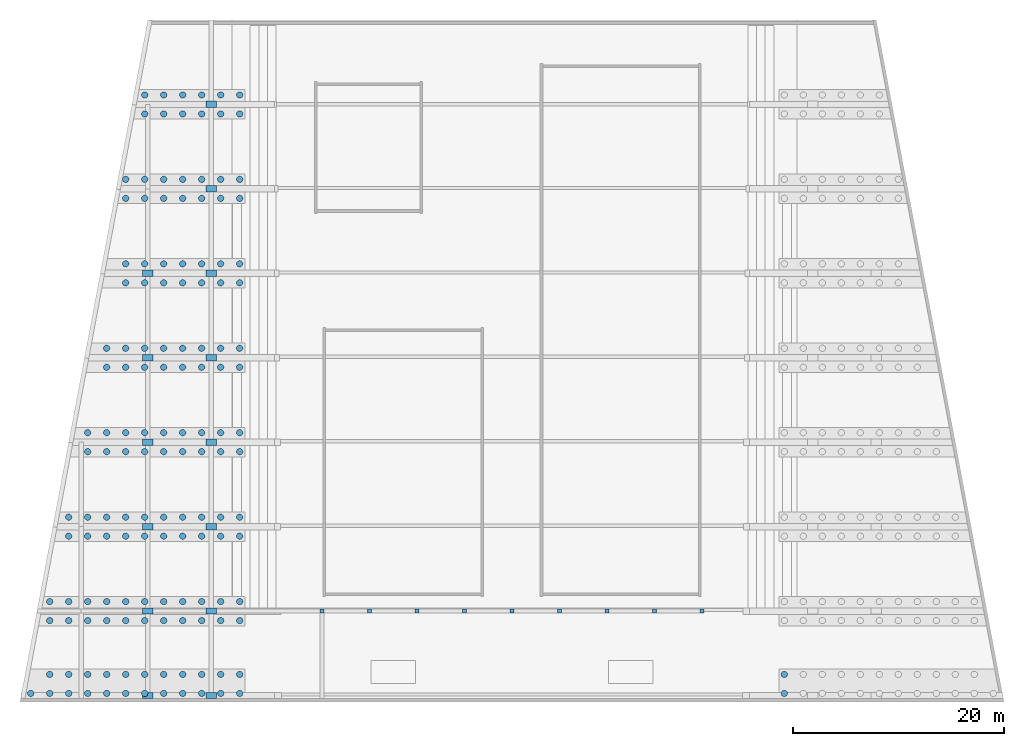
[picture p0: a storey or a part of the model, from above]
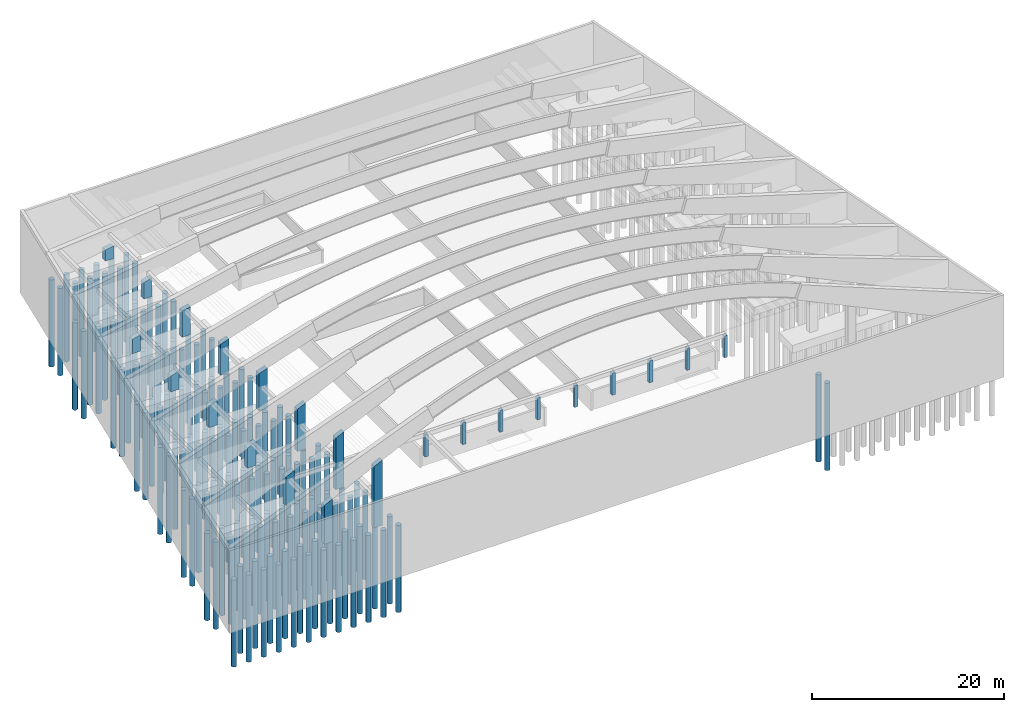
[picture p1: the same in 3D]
Properties of the parts of a building model (IFC2X3), part 1 of 5

# File
Description: ViewDefinition [CoordinationView_V2.0, QuantityTakeOffAddOnView]
File name: Project Number
Time: 2019-07-20T14:07:28
Written by: The EXPRESS Data Manager Version 5.02.0100.07 : 28 Aug 2013
Made in: 20170223_1515(x64) - Exporter 18.4.0.0 - Alternate UI 18.4.0.0
Comment: STEP Physical File produced by: The EXPRESS Data Manager Version 5.02.0100.07 : 28 Aug 2013 * Module: EDMstepFileFactory/EDMstandAlone * Creation date: Sat Jul 20 14:07:28 2019 * Host: ICIVEML714002 * Database: C:\Users\JL9E96~1.PON\AppData\Local\Temp\{ACF15B86-B727-4FDA-8734-9AC93CBAED3B}\ifc * Database version: 5507 * Database creation date: Sat Jul 20 14:07:22 2019 * Schema: IFC2X3 * Model: DataRepository.ifc * Model creation date: Sat Jul 20 14:07:23 2019 * Header model: DataRepository.ifc_HeaderModel * Header model creation date: Sat Jul 20 14:07:23 2019 * EDMuser: sdai-user * EDMgroup: sdai-group * License ID and type: 5605 : Permanent license. Expiry date: * EDMstepFileFactory options: 020000

# IfcProject, Project Number
LongName: Project Name; Phase: Project Status

# IfcSite, Default
RefLatitude: 42, 21, 31, 181945; RefLongitude: -71, -3, -24, -263305; RefElevation: 0 mm
Other - Category: Project Information; Client Name: Owner; Project Address: ## Street City, State Zip; Project Issue Date: Issue Date; Project Name: Project Name; Project Number: Project Number; Project Status: Project Status

# IfcBuilding
Pset_BuildingCommon - NumberOfStoreys: 2
Pset_ProductRequirements - Category: Project Information
Other - Category: Project Information; Client Name: Owner; Project Address: ## Street City, State Zip; Project Issue Date: Issue Date; Project Name: Project Name; Project Number: Project Number; Project Status: Project Status

# IfcBuildingStorey: Level:8mm Head, Default
LongName: Default; Elevation: 0 mm
Pset_AirSideSystemInformation - Name: Default
Pset_ProductRequirements - Name: Default; Category: Levels
Constraints - Elevation: 0 mm
Dimensions - Computation Height: 0 mm
Identity Data - Building Story: yes; Name: Default; Structural: no
Other - Category: Levels; Family: Level: 8mm Head; Family and Type: Level: 8mm Head; Type: Level: 8mm Head; Type Id: Level: 8mm Head
Constraints(Type) - Elevation Base: Project Base Point
Graphics(Type) - Color: 0; Line Pattern: Center; Line Weight: 1; Symbol: M_Level Head - Circle: M_Level Head - Circle; Symbol at End 1 Default: no; Symbol at End 2 Default: yes
Identity Data(Type) - Type Name: 8mm Head
Other(Type) - Category: Levels; Family Name: Level

# IfcBuildingElementProxy: 1000*2800, 1000*2800:1000*2800:212590
In: Default
Type - Classification: A1010130 Pile Caps (Uniformat); Material: CONCRETE/28MPa
Type - Identity Data - Assembly Code: A1010130; Assembly Description: Pile Caps; Type Name: 1000*2800
Type - Materials and Finishes - Material: CONCRETE/28MPa
Type - Other - Category: Structural Framing; Family Name: 1000*2800
Type - Structural - Section Shape: 0
Type - Pset_BuildingElementProxyCommon - Reference: 1000*2800
Type - Pset_ProductRequirements - Category: Structural Framing
Type - Pset_QuantityTakeOff - Reference: 1000*2800
Pset_BuildingElementProxyCommon - sets with these values: 2
Constraints - Moves With Nearby Elements: no; Level: Level: Default; Host: Level : Default; Offset: -3800 mm
Dimensions - Area: 65.1248 m2; Volume: 45.9055 m3
Other - Family: 1000*2800: 1000*2800; Family and Type: 1000*2800: 1000*2800; Type: 1000*2800: 1000*2800; Type Id: 1000*2800: 1000*2800
Phasing - Phase Created: New Construction
Structural - Rebar Cover - Other Faces: Rebar Cover Settings: Rebar Cover 1; Rebar Cover - Bottom Face: Rebar Cover Settings: Rebar Cover 1; Rebar Cover - Top Face: Rebar Cover Settings: Rebar Cover 1

# IfcBuildingElementProxy: 1000*2800 1594, 1000*2800 1594:1000*2800 1594:212589
In: Default
Type - Classification: A1010130 Pile Caps (Uniformat); Material: CONCRETE/28MPa
Type - Identity Data - Assembly Code: A1010130; Assembly Description: Pile Caps; Type Name: 1000*2800 1594
Type - Materials and Finishes - Material: CONCRETE/28MPa
Type - Other - Category: Structural Framing; Family Name: 1000*2800 1594
Type - Structural - Section Shape: 0
Type - Pset_BuildingElementProxyCommon - Reference: 1000*2800 1594
Type - Pset_ProductRequirements - Category: Structural Framing
Type - Pset_QuantityTakeOff - Reference: 1000*2800 1594
Pset_BuildingElementProxyCommon - sets with these values: 2
Constraints - Moves With Nearby Elements: no; Level: Level: Default; Host: Level : Default; Offset: -3800 mm
Dimensions - Area: 42.325 m2; Volume: 29.1057 m3
Other - Family: 1000*2800 1594: 1000*2800 1594; Family and Type: 1000*2800 1594: 1000*2800 1594; Type: 1000*2800 1594: 1000*2800 1594; Type Id: 1000*2800 1594: 1000*2800 1594
Phasing - Phase Created: New Construction
Structural - Rebar Cover - Other Faces: Rebar Cover Settings: Rebar Cover 1; Rebar Cover - Bottom Face: Rebar Cover Settings: Rebar Cover 1; Rebar Cover - Top Face: Rebar Cover Settings: Rebar Cover 1

# IfcBuildingElementProxy: 1000*2800 1628, 1000*2800 1628:1000*2800 1628:212588
In: Default
Type - Classification: A1010130 Pile Caps (Uniformat); Material: CONCRETE/28MPa
Type - Identity Data - Assembly Code: A1010130; Assembly Description: Pile Caps; Type Name: 1000*2800 1628
Type - Materials and Finishes - Material: CONCRETE/28MPa
Type - Other - Category: Structural Framing; Family Name: 1000*2800 1628
Type - Structural - Section Shape: 0
Type - Pset_BuildingElementProxyCommon - Reference: 1000*2800 1628
Type - Pset_ProductRequirements - Category: Structural Framing
Type - Pset_QuantityTakeOff - Reference: 1000*2800 1628
Pset_BuildingElementProxyCommon - sets with these values: 2
Constraints - Moves With Nearby Elements: no; Level: Level: Default; Host: Level : Default; Offset: -3800 mm
Dimensions - Area: 48.0363 m2; Volume: 33.3136 m3
Other - Family: 1000*2800 1628: 1000*2800 1628; Family and Type: 1000*2800 1628: 1000*2800 1628; Type: 1000*2800 1628: 1000*2800 1628; Type Id: 1000*2800 1628: 1000*2800 1628
Phasing - Phase Created: New Construction
Structural - Rebar Cover - Other Faces: Rebar Cover Settings: Rebar Cover 1; Rebar Cover - Bottom Face: Rebar Cover Settings: Rebar Cover 1; Rebar Cover - Top Face: Rebar Cover Settings: Rebar Cover 1

# IfcBuildingElementProxy: 1000*2800 1660, 1000*2800 1660:1000*2800 1660:212587
In: Default
Type - Classification: A1010130 Pile Caps (Uniformat); Material: CONCRETE/28MPa
Type - Identity Data - Assembly Code: A1010130; Assembly Description: Pile Caps; Type Name: 1000*2800 1660
Type - Materials and Finishes - Material: CONCRETE/28MPa
Type - Other - Category: Structural Framing; Family Name: 1000*2800 1660
Type - Structural - Section Shape: 0
Type - Pset_BuildingElementProxyCommon - Reference: 1000*2800 1660
Type - Pset_ProductRequirements - Category: Structural Framing
Type - Pset_QuantityTakeOff - Reference: 1000*2800 1660
Pset_BuildingElementProxyCommon - sets with these values: 2
Constraints - Moves With Nearby Elements: no; Level: Level: Default; Host: Level : Default; Offset: -3800 mm
Dimensions - Area: 53.7249 m2; Volume: 37.5056 m3
Other - Family: 1000*2800 1660: 1000*2800 1660; Family and Type: 1000*2800 1660: 1000*2800 1660; Type: 1000*2800 1660: 1000*2800 1660; Type Id: 1000*2800 1660: 1000*2800 1660
Phasing - Phase Created: New Construction
Structural - Rebar Cover - Other Faces: Rebar Cover Settings: Rebar Cover 1; Rebar Cover - Bottom Face: Rebar Cover Settings: Rebar Cover 1; Rebar Cover - Top Face: Rebar Cover Settings: Rebar Cover 1

# IfcBuildingElementProxy: 1000*2800 1692, 1000*2800 1692:1000*2800 1692:212586
In: Default
Type - Classification: A1010130 Pile Caps (Uniformat); Material: CONCRETE/28MPa
Type - Identity Data - Assembly Code: A1010130; Assembly Description: Pile Caps; Type Name: 1000*2800 1692
Type - Materials and Finishes - Material: CONCRETE/28MPa
Type - Other - Category: Structural Framing; Family Name: 1000*2800 1692
Type - Structural - Section Shape: 0
Type - Pset_BuildingElementProxyCommon - Reference: 1000*2800 1692
Type - Pset_ProductRequirements - Category: Structural Framing
Type - Pset_QuantityTakeOff - Reference: 1000*2800 1692
Pset_BuildingElementProxyCommon - sets with these values: 2
Constraints - Moves With Nearby Elements: no; Level: Level: Default; Host: Level : Default; Offset: -3800 mm
Dimensions - Area: 59.4248 m2; Volume: 41.7056 m3
Other - Family: 1000*2800 1692: 1000*2800 1692; Family and Type: 1000*2800 1692: 1000*2800 1692; Type: 1000*2800 1692: 1000*2800 1692; Type Id: 1000*2800 1692: 1000*2800 1692
Phasing - Phase Created: New Construction
Structural - Rebar Cover - Other Faces: Rebar Cover Settings: Rebar Cover 1; Rebar Cover - Bottom Face: Rebar Cover Settings: Rebar Cover 1; Rebar Cover - Top Face: Rebar Cover Settings: Rebar Cover 1

# IfcBuildingElementProxy: 1000*2800 1722, 1000*2800 1722:1000*2800 1722:212585
In: Default
Type - Classification: A1010130 Pile Caps (Uniformat); Material: CONCRETE/28MPa
Type - Identity Data - Assembly Code: A1010130; Assembly Description: Pile Caps; Type Name: 1000*2800 1722
Type - Materials and Finishes - Material: CONCRETE/28MPa
Type - Other - Category: Structural Framing; Family Name: 1000*2800 1722
Type - Structural - Section Shape: 0
Type - Pset_BuildingElementProxyCommon - Reference: 1000*2800 1722
Type - Pset_ProductRequirements - Category: Structural Framing
Type - Pset_QuantityTakeOff - Reference: 1000*2800 1722
Pset_BuildingElementProxyCommon - sets with these values: 2
Constraints - Moves With Nearby Elements: no; Level: Level: Default; Host: Level : Default; Offset: -3800 mm
Dimensions - Area: 70.8247 m2; Volume: 50.1055 m3
Other - Family: 1000*2800 1722: 1000*2800 1722; Family and Type: 1000*2800 1722: 1000*2800 1722; Type: 1000*2800 1722: 1000*2800 1722; Type Id: 1000*2800 1722: 1000*2800 1722
Phasing - Phase Created: New Construction
Structural - Rebar Cover - Other Faces: Rebar Cover Settings: Rebar Cover 1; Rebar Cover - Bottom Face: Rebar Cover Settings: Rebar Cover 1; Rebar Cover - Top Face: Rebar Cover Settings: Rebar Cover 1

# IfcBuildingElementProxy: 1000*2800 1754, 1000*2800 1754:1000*2800 1754:212584
In: Default
Type - Classification: A1010130 Pile Caps (Uniformat); Material: CONCRETE/28MPa
Type - Identity Data - Assembly Code: A1010130; Assembly Description: Pile Caps; Type Name: 1000*2800 1754
Type - Materials and Finishes - Material: CONCRETE/28MPa
Type - Other - Category: Structural Framing; Family Name: 1000*2800 1754
Type - Structural - Section Shape: 0
Type - Pset_BuildingElementProxyCommon - Reference: 1000*2800 1754
Type - Pset_ProductRequirements - Category: Structural Framing
Type - Pset_QuantityTakeOff - Reference: 1000*2800 1754
Pset_BuildingElementProxyCommon - sets with these values: 2
Constraints - Moves With Nearby Elements: no; Level: Level: Default; Host: Level : Default; Offset: -3800 mm
Dimensions - Area: 76.5246 m2; Volume: 54.3054 m3
Other - Family: 1000*2800 1754: 1000*2800 1754; Family and Type: 1000*2800 1754: 1000*2800 1754; Type: 1000*2800 1754: 1000*2800 1754; Type Id: 1000*2800 1754: 1000*2800 1754
Phasing - Phase Created: New Construction
Structural - Rebar Cover - Other Faces: Rebar Cover Settings: Rebar Cover 1; Rebar Cover - Bottom Face: Rebar Cover Settings: Rebar Cover 1; Rebar Cover - Top Face: Rebar Cover Settings: Rebar Cover 1

# IfcBuildingElementProxy: 1000*2800 1835, 1000*2800 1835:1000*2800 1835:212583
In: Default
Type - Classification: A1010130 Pile Caps (Uniformat); Material: CONCRETE/28MPa
Type - Identity Data - Assembly Code: A1010130; Assembly Description: Pile Caps; Type Name: 1000*2800 1835
Type - Materials and Finishes - Material: CONCRETE/28MPa
Type - Other - Category: Structural Framing; Family Name: 1000*2800 1835
Type - Structural - Section Shape: 0
Type - Pset_BuildingElementProxyCommon - Reference: 1000*2800 1835
Type - Pset_ProductRequirements - Category: Structural Framing
Type - Pset_QuantityTakeOff - Reference: 1000*2800 1835
Pset_BuildingElementProxyCommon - sets with these values: 2
Constraints - Moves With Nearby Elements: no; Level: Level: Default; Host: Level : Default; Offset: -3800 mm
Dimensions - Area: 81.4408 m2; Volume: 57.9279 m3
Other - Family: 1000*2800 1835: 1000*2800 1835; Family and Type: 1000*2800 1835: 1000*2800 1835; Type: 1000*2800 1835: 1000*2800 1835; Type Id: 1000*2800 1835: 1000*2800 1835
Phasing - Phase Created: New Construction
Structural - Rebar Cover - Other Faces: Rebar Cover Settings: Rebar Cover 1; Rebar Cover - Bottom Face: Rebar Cover Settings: Rebar Cover 1; Rebar Cover - Top Face: Rebar Cover Settings: Rebar Cover 1

# IfcBuildingElementProxy: 1000*2800 3217, 1000*2800 3217:1000*2800 3217:212544
In: Default
Type - Classification: A1010130 Pile Caps (Uniformat); Material: CONCRETE/28MPa
Type - Identity Data - Assembly Code: A1010130; Assembly Description: Pile Caps; Type Name: 1000*2800 3217
Type - Materials and Finishes - Material: CONCRETE/28MPa
Type - Other - Category: Structural Framing; Family Name: 1000*2800 3217
Type - Structural - Section Shape: 0
Type - Pset_BuildingElementProxyCommon - Reference: 1000*2800 3217
Type - Pset_ProductRequirements - Category: Structural Framing
Type - Pset_QuantityTakeOff - Reference: 1000*2800 3217
Pset_BuildingElementProxyCommon - sets with these values: 2
Constraints - Moves With Nearby Elements: no; Level: Level: Default; Host: Level : Default; Offset: -3800 mm
Dimensions - Area: 65.1248 m2; Volume: 45.9055 m3
Other - Family: 1000*2800 3217: 1000*2800 3217; Family and Type: 1000*2800 3217: 1000*2800 3217; Type: 1000*2800 3217: 1000*2800 3217; Type Id: 1000*2800 3217: 1000*2800 3217
Phasing - Phase Created: New Construction
Structural - Rebar Cover - Other Faces: Rebar Cover Settings: Rebar Cover 1; Rebar Cover - Bottom Face: Rebar Cover Settings: Rebar Cover 1; Rebar Cover - Top Face: Rebar Cover Settings: Rebar Cover 1

# IfcBuildingElementProxy: 1000*2800 4924, 1000*2800 4924:1000*2800 4924:212262
In: Default
Type - Classification: A1010130 Pile Caps (Uniformat); Material: CONCRETE/28MPa
Type - Identity Data - Assembly Code: A1010130; Assembly Description: Pile Caps; Type Name: 1000*2800 4924
Type - Materials and Finishes - Material: CONCRETE/28MPa
Type - Other - Category: Structural Framing; Family Name: 1000*2800 4924
Type - Structural - Section Shape: 0
Type - Pset_BuildingElementProxyCommon - Reference: 1000*2800 4924
Type - Pset_ProductRequirements - Category: Structural Framing
Type - Pset_QuantityTakeOff - Reference: 1000*2800 4924
Pset_BuildingElementProxyCommon - sets with these values: 2
Constraints - Moves With Nearby Elements: no; Level: Level: Default; Host: Level : Default; Offset: -3800 mm
Dimensions - Area: 42.325 m2; Volume: 29.1057 m3
Other - Family: 1000*2800 4924: 1000*2800 4924; Family and Type: 1000*2800 4924: 1000*2800 4924; Type: 1000*2800 4924: 1000*2800 4924; Type Id: 1000*2800 4924: 1000*2800 4924
Phasing - Phase Created: New Construction
Structural - Rebar Cover - Other Faces: Rebar Cover Settings: Rebar Cover 1; Rebar Cover - Bottom Face: Rebar Cover Settings: Rebar Cover 1; Rebar Cover - Top Face: Rebar Cover Settings: Rebar Cover 1

# IfcBuildingElementProxy: 1000*2800 4946, 1000*2800 4946:1000*2800 4946:212261
In: Default
Type - Classification: A1010130 Pile Caps (Uniformat); Material: CONCRETE/28MPa
Type - Identity Data - Assembly Code: A1010130; Assembly Description: Pile Caps; Type Name: 1000*2800 4946
Type - Materials and Finishes - Material: CONCRETE/28MPa
Type - Other - Category: Structural Framing; Family Name: 1000*2800 4946
Type - Structural - Section Shape: 0
Type - Pset_BuildingElementProxyCommon - Reference: 1000*2800 4946
Type - Pset_ProductRequirements - Category: Structural Framing
Type - Pset_QuantityTakeOff - Reference: 1000*2800 4946
Pset_BuildingElementProxyCommon - sets with these values: 2
Constraints - Moves With Nearby Elements: no; Level: Level: Default; Host: Level : Default; Offset: -3800 mm
Dimensions - Area: 48.0363 m2; Volume: 33.3136 m3
Other - Family: 1000*2800 4946: 1000*2800 4946; Family and Type: 1000*2800 4946: 1000*2800 4946; Type: 1000*2800 4946: 1000*2800 4946; Type Id: 1000*2800 4946: 1000*2800 4946
Phasing - Phase Created: New Construction
Structural - Rebar Cover - Other Faces: Rebar Cover Settings: Rebar Cover 1; Rebar Cover - Bottom Face: Rebar Cover Settings: Rebar Cover 1; Rebar Cover - Top Face: Rebar Cover Settings: Rebar Cover 1

# IfcBuildingElementProxy: 1000*2800 4966, 1000*2800 4966:1000*2800 4966:212260
In: Default
Type - Classification: A1010130 Pile Caps (Uniformat); Material: CONCRETE/28MPa
Type - Identity Data - Assembly Code: A1010130; Assembly Description: Pile Caps; Type Name: 1000*2800 4966
Type - Materials and Finishes - Material: CONCRETE/28MPa
Type - Other - Category: Structural Framing; Family Name: 1000*2800 4966
Type - Structural - Section Shape: 0
Type - Pset_BuildingElementProxyCommon - Reference: 1000*2800 4966
Type - Pset_ProductRequirements - Category: Structural Framing
Type - Pset_QuantityTakeOff - Reference: 1000*2800 4966
Pset_BuildingElementProxyCommon - sets with these values: 2
Constraints - Moves With Nearby Elements: no; Level: Level: Default; Host: Level : Default; Offset: -3800 mm
Dimensions - Area: 53.7249 m2; Volume: 37.5056 m3
Other - Family: 1000*2800 4966: 1000*2800 4966; Family and Type: 1000*2800 4966: 1000*2800 4966; Type: 1000*2800 4966: 1000*2800 4966; Type Id: 1000*2800 4966: 1000*2800 4966
Phasing - Phase Created: New Construction
Structural - Rebar Cover - Other Faces: Rebar Cover Settings: Rebar Cover 1; Rebar Cover - Bottom Face: Rebar Cover Settings: Rebar Cover 1; Rebar Cover - Top Face: Rebar Cover Settings: Rebar Cover 1

# IfcBuildingElementProxy: 1000*2800 4986, 1000*2800 4986:1000*2800 4986:212259
In: Default
Type - Classification: A1010130 Pile Caps (Uniformat); Material: CONCRETE/28MPa
Type - Identity Data - Assembly Code: A1010130; Assembly Description: Pile Caps; Type Name: 1000*2800 4986
Type - Materials and Finishes - Material: CONCRETE/28MPa
Type - Other - Category: Structural Framing; Family Name: 1000*2800 4986
Type - Structural - Section Shape: 0
Type - Pset_BuildingElementProxyCommon - Reference: 1000*2800 4986
Type - Pset_ProductRequirements - Category: Structural Framing
Type - Pset_QuantityTakeOff - Reference: 1000*2800 4986
Pset_BuildingElementProxyCommon - sets with these values: 2
Constraints - Moves With Nearby Elements: no; Level: Level: Default; Host: Level : Default; Offset: -3800 mm
Dimensions - Area: 59.4248 m2; Volume: 41.7056 m3
Other - Family: 1000*2800 4986: 1000*2800 4986; Family and Type: 1000*2800 4986: 1000*2800 4986; Type: 1000*2800 4986: 1000*2800 4986; Type Id: 1000*2800 4986: 1000*2800 4986
Phasing - Phase Created: New Construction
Structural - Rebar Cover - Other Faces: Rebar Cover Settings: Rebar Cover 1; Rebar Cover - Bottom Face: Rebar Cover Settings: Rebar Cover 1; Rebar Cover - Top Face: Rebar Cover Settings: Rebar Cover 1

# IfcBuildingElementProxy: 1000*2800 5003, 1000*2800 5003:1000*2800 5003:212258
In: Default
Type - Classification: A1010130 Pile Caps (Uniformat); Material: CONCRETE/28MPa
Type - Identity Data - Assembly Code: A1010130; Assembly Description: Pile Caps; Type Name: 1000*2800 5003
Type - Materials and Finishes - Material: CONCRETE/28MPa
Type - Other - Category: Structural Framing; Family Name: 1000*2800 5003
Type - Structural - Section Shape: 0
Type - Pset_BuildingElementProxyCommon - Reference: 1000*2800 5003
Type - Pset_ProductRequirements - Category: Structural Framing
Type - Pset_QuantityTakeOff - Reference: 1000*2800 5003
Pset_BuildingElementProxyCommon - sets with these values: 2
Constraints - Moves With Nearby Elements: no; Level: Level: Default; Host: Level : Default; Offset: -3800 mm
Dimensions - Area: 70.8247 m2; Volume: 50.1055 m3
Other - Family: 1000*2800 5003: 1000*2800 5003; Family and Type: 1000*2800 5003: 1000*2800 5003; Type: 1000*2800 5003: 1000*2800 5003; Type Id: 1000*2800 5003: 1000*2800 5003
Phasing - Phase Created: New Construction
Structural - Rebar Cover - Other Faces: Rebar Cover Settings: Rebar Cover 1; Rebar Cover - Bottom Face: Rebar Cover Settings: Rebar Cover 1; Rebar Cover - Top Face: Rebar Cover Settings: Rebar Cover 1

# IfcBuildingElementProxy: 1000*2800 5022, 1000*2800 5022:1000*2800 5022:212257
In: Default
Type - Classification: A1010130 Pile Caps (Uniformat); Material: CONCRETE/28MPa
Type - Identity Data - Assembly Code: A1010130; Assembly Description: Pile Caps; Type Name: 1000*2800 5022
Type - Materials and Finishes - Material: CONCRETE/28MPa
Type - Other - Category: Structural Framing; Family Name: 1000*2800 5022
Type - Structural - Section Shape: 0
Type - Pset_BuildingElementProxyCommon - Reference: 1000*2800 5022
Type - Pset_ProductRequirements - Category: Structural Framing
Type - Pset_QuantityTakeOff - Reference: 1000*2800 5022
Pset_BuildingElementProxyCommon - sets with these values: 2
Constraints - Moves With Nearby Elements: no; Host: Level : Default; Level: Level: Default; Offset: -3800 mm
Dimensions - Area: 76.5246 m2; Volume: 54.3054 m3
Other - Family: 1000*2800 5022: 1000*2800 5022; Family and Type: 1000*2800 5022: 1000*2800 5022; Type: 1000*2800 5022: 1000*2800 5022; Type Id: 1000*2800 5022: 1000*2800 5022
Phasing - Phase Created: New Construction
Structural - Rebar Cover - Other Faces: Rebar Cover Settings: Rebar Cover 1; Rebar Cover - Bottom Face: Rebar Cover Settings: Rebar Cover 1; Rebar Cover - Top Face: Rebar Cover Settings: Rebar Cover 1

# IfcBuildingElementProxy: 1000*2800 5068, 1000*2800 5068:1000*2800 5068:212256
In: Default
Type - Classification: A1010130 Pile Caps (Uniformat); Material: CONCRETE/28MPa
Type - Identity Data - Assembly Code: A1010130; Assembly Description: Pile Caps; Type Name: 1000*2800 5068
Type - Materials and Finishes - Material: CONCRETE/28MPa
Type - Other - Category: Structural Framing; Family Name: 1000*2800 5068
Type - Structural - Section Shape: 0
Type - Pset_BuildingElementProxyCommon - Reference: 1000*2800 5068
Type - Pset_ProductRequirements - Category: Structural Framing
Type - Pset_QuantityTakeOff - Reference: 1000*2800 5068
Pset_BuildingElementProxyCommon - sets with these values: 2
Constraints - Moves With Nearby Elements: no; Host: Level : Default; Level: Level: Default; Offset: -3800 mm
Dimensions - Area: 81.4408 m2; Volume: 57.9279 m3
Other - Family: 1000*2800 5068: 1000*2800 5068; Family and Type: 1000*2800 5068: 1000*2800 5068; Type: 1000*2800 5068: 1000*2800 5068; Type Id: 1000*2800 5068: 1000*2800 5068
Phasing - Phase Created: New Construction
Structural - Rebar Cover - Other Faces: Rebar Cover Settings: Rebar Cover 1; Rebar Cover - Bottom Face: Rebar Cover Settings: Rebar Cover 1; Rebar Cover - Top Face: Rebar Cover Settings: Rebar Cover 1

# IfcBuildingElementProxy: 500*400 (4)
In: Default
Type - Classification: B1010310 Beams - CIP (Uniformat); Material: CONCRETE/28MPa 4258
Type - Identity Data - Assembly Code: B1010310; Assembly Description: Beams - CIP; Type Name: 500*400
Type - Materials and Finishes - Material: CONCRETE/28MPa 4258
Type - Other - Category: Structural Framing; Family Name: 500*400
Type - Structural - Section Shape: 0
Type - Pset_BuildingElementProxyCommon - Reference: 500*400
Type - Pset_ProductRequirements - Category: Structural Framing
Type - Pset_QuantityTakeOff - Reference: 500*400
Pset_BuildingElementProxyCommon - sets with these values: 2
Constraints - Moves With Nearby Elements: no; Level: Level: Default; Host: Level : Default; Offset: -150 mm
Dimensions - Area: 7.67 m2; Volume: 1.66 m3
Other - Family: 500*400: 500*400; Family and Type: 500*400: 500*400; Type: 500*400: 500*400; Type Id: 500*400: 500*400
Phasing - Phase Created: New Construction
Structural - Rebar Cover - Other Faces: Rebar Cover Settings: Rebar Cover 1; Rebar Cover - Bottom Face: Rebar Cover Settings: Rebar Cover 1; Rebar Cover - Top Face: Rebar Cover Settings: Rebar Cover 1
Name (500*400:500*400:...)
212263
212271
212286
212301

# IfcBuildingElementProxy: 500*400 4300 (8)
In: Default
Type - Classification: B1010310 Beams - CIP (Uniformat); Material: CONCRETE/28MPa 4258
Type - Identity Data - Assembly Code: B1010310; Assembly Description: Beams - CIP; Type Name: 500*400 4300
Type - Materials and Finishes - Material: CONCRETE/28MPa 4258
Type - Other - Category: Structural Framing; Family Name: 500*400 4300
Type - Structural - Section Shape: 0
Type - Pset_BuildingElementProxyCommon - Reference: 500*400 4300
Type - Pset_ProductRequirements - Category: Structural Framing
Type - Pset_QuantityTakeOff - Reference: 500*400 4300
Pset_BuildingElementProxyCommon - sets with these values: 2
Constraints - Moves With Nearby Elements: no; Level: Level: Default; Host: Level : Default; Offset: -150 mm
Dimensions - Area: 4.25 m2; Volume: 0.9 m3
Other - Family: 500*400 4300: 500*400 4300; Family and Type: 500*400 4300: 500*400 4300; Type: 500*400 4300: 500*400 4300; Type Id: 500*400 4300: 500*400 4300
Phasing - Phase Created: New Construction
Structural - Rebar Cover - Other Faces: Rebar Cover Settings: Rebar Cover 1; Rebar Cover - Bottom Face: Rebar Cover Settings: Rebar Cover 1; Rebar Cover - Top Face: Rebar Cover Settings: Rebar Cover 1
Name (500*400 4300:500*400 4300:...)
212293
212294
212295
212296
212297
212298
212299
212300

# IfcBuildingElementProxy: 500*400 4394, 500*400 4394:500*400 4394:212292
In: Default
Type - Classification: B1010310 Beams - CIP (Uniformat); Material: CONCRETE/28MPa 4258
Type - Identity Data - Assembly Code: B1010310; Assembly Description: Beams - CIP; Type Name: 500*400 4394
Type - Materials and Finishes - Material: CONCRETE/28MPa 4258
Type - Other - Category: Structural Framing; Family Name: 500*400 4394
Type - Structural - Section Shape: 0
Type - Pset_BuildingElementProxyCommon - Reference: 500*400 4394
Type - Pset_ProductRequirements - Category: Structural Framing
Type - Pset_QuantityTakeOff - Reference: 500*400 4394
Pset_BuildingElementProxyCommon - sets with these values: 2
Constraints - Moves With Nearby Elements: no; Level: Level: Default; Host: Level : Default; Offset: -150 mm
Dimensions - Area: 9.65 m2; Volume: 2.1 m3
Other - Family: 500*400 4394: 500*400 4394; Family and Type: 500*400 4394: 500*400 4394; Type: 500*400 4394: 500*400 4394; Type Id: 500*400 4394: 500*400 4394
Phasing - Phase Created: New Construction
Structural - Rebar Cover - Other Faces: Rebar Cover Settings: Rebar Cover 1; Rebar Cover - Bottom Face: Rebar Cover Settings: Rebar Cover 1; Rebar Cover - Top Face: Rebar Cover Settings: Rebar Cover 1

# IfcBuildingElementProxy: 500*400 4419, 500*400 4419:500*400 4419:212291
In: Default
Type - Classification: B1010310 Beams - CIP (Uniformat); Material: CONCRETE/28MPa 4258
Type - Identity Data - Assembly Code: B1010310; Assembly Description: Beams - CIP; Type Name: 500*400 4419
Type - Materials and Finishes - Material: CONCRETE/28MPa 4258
Type - Other - Category: Structural Framing; Family Name: 500*400 4419
Type - Structural - Section Shape: 0
Type - Pset_BuildingElementProxyCommon - Reference: 500*400 4419
Type - Pset_ProductRequirements - Category: Structural Framing
Type - Pset_QuantityTakeOff - Reference: 500*400 4419
Pset_BuildingElementProxyCommon - sets with these values: 2
Constraints - Moves With Nearby Elements: no; Level: Level: Default; Host: Level : Default; Offset: -150 mm
Dimensions - Area: 5.6 m2; Volume: 1.2 m3
Other - Family: 500*400 4419: 500*400 4419; Family and Type: 500*400 4419: 500*400 4419; Type: 500*400 4419: 500*400 4419; Type Id: 500*400 4419: 500*400 4419
Phasing - Phase Created: New Construction
Structural - Rebar Cover - Other Faces: Rebar Cover Settings: Rebar Cover 1; Rebar Cover - Bottom Face: Rebar Cover Settings: Rebar Cover 1; Rebar Cover - Top Face: Rebar Cover Settings: Rebar Cover 1

# IfcBuildingElementProxy: 500*400 4444, 500*400 4444:500*400 4444:212290
In: Default
Type - Classification: B1010310 Beams - CIP (Uniformat); Material: CONCRETE/28MPa 4258
Type - Identity Data - Assembly Code: B1010310; Assembly Description: Beams - CIP; Type Name: 500*400 4444
Type - Materials and Finishes - Material: CONCRETE/28MPa 4258
Type - Other - Category: Structural Framing; Family Name: 500*400 4444
Type - Structural - Section Shape: 0
Type - Pset_BuildingElementProxyCommon - Reference: 500*400 4444
Type - Pset_ProductRequirements - Category: Structural Framing
Type - Pset_QuantityTakeOff - Reference: 500*400 4444
Pset_BuildingElementProxyCommon - sets with these values: 2
Constraints - Moves With Nearby Elements: no; Level: Level: Default; Host: Level : Default; Offset: -150 mm
Dimensions - Area: 5.879 m2; Volume: 1.262 m3
Other - Family: 500*400 4444: 500*400 4444; Family and Type: 500*400 4444: 500*400 4444; Type: 500*400 4444: 500*400 4444; Type Id: 500*400 4444: 500*400 4444
Phasing - Phase Created: New Construction
Structural - Rebar Cover - Other Faces: Rebar Cover Settings: Rebar Cover 1; Rebar Cover - Bottom Face: Rebar Cover Settings: Rebar Cover 1; Rebar Cover - Top Face: Rebar Cover Settings: Rebar Cover 1

# IfcBuildingElementProxy: 500*400 4468, 500*400 4468:500*400 4468:212289
In: Default
Type - Classification: B1010310 Beams - CIP (Uniformat); Material: CONCRETE/28MPa 4258
Type - Identity Data - Assembly Code: B1010310; Assembly Description: Beams - CIP; Type Name: 500*400 4468
Type - Materials and Finishes - Material: CONCRETE/28MPa 4258
Type - Other - Category: Structural Framing; Family Name: 500*400 4468
Type - Structural - Section Shape: 0
Type - Pset_BuildingElementProxyCommon - Reference: 500*400 4468
Type - Pset_ProductRequirements - Category: Structural Framing
Type - Pset_QuantityTakeOff - Reference: 500*400 4468
Pset_BuildingElementProxyCommon - sets with these values: 2
Constraints - Moves With Nearby Elements: no; Level: Level: Default; Host: Level : Default; Offset: -150 mm
Dimensions - Area: 3.93324 m2; Volume: 0.82961 m3
Other - Family: 500*400 4468: 500*400 4468; Family and Type: 500*400 4468: 500*400 4468; Type: 500*400 4468: 500*400 4468; Type Id: 500*400 4468: 500*400 4468
Phasing - Phase Created: New Construction
Structural - Rebar Cover - Other Faces: Rebar Cover Settings: Rebar Cover 1; Rebar Cover - Bottom Face: Rebar Cover Settings: Rebar Cover 1; Rebar Cover - Top Face: Rebar Cover Settings: Rebar Cover 1

# IfcBuildingElementProxy: 500*400 4495 (14)
In: Default
Type - Classification: B1010310 Beams - CIP (Uniformat); Material: CONCRETE/28MPa 4258
Type - Identity Data - Assembly Code: B1010310; Assembly Description: Beams - CIP; Type Name: 500*400 4495
Type - Materials and Finishes - Material: CONCRETE/28MPa 4258
Type - Other - Category: Structural Framing; Family Name: 500*400 4495
Type - Structural - Section Shape: 0
Type - Pset_BuildingElementProxyCommon - Reference: 500*400 4495
Type - Pset_ProductRequirements - Category: Structural Framing
Type - Pset_QuantityTakeOff - Reference: 500*400 4495
Pset_BuildingElementProxyCommon - sets with these values: 2
Constraints - Moves With Nearby Elements: no; Level: Level: Default; Host: Level : Default; Offset: -150 mm
Dimensions - Area: 7.4 m2; Volume: 1.6 m3
Other - Family: 500*400 4495: 500*400 4495; Family and Type: 500*400 4495: 500*400 4495; Type: 500*400 4495: 500*400 4495; Type Id: 500*400 4495: 500*400 4495
Phasing - Phase Created: New Construction
Structural - Rebar Cover - Other Faces: Rebar Cover Settings: Rebar Cover 1; Rebar Cover - Bottom Face: Rebar Cover Settings: Rebar Cover 1; Rebar Cover - Top Face: Rebar Cover Settings: Rebar Cover 1
Name (500*400 4495:500*400 4495:...)
212264
212265
212266
212267
212268
212269
212272
212273
212274
212275
212276
212277
212287
212288

# IfcBuildingElementProxy: 500*400 4543, 500*400 4543:500*400 4543:212285
In: Default
Type - Classification: B1010310 Beams - CIP (Uniformat); Material: CONCRETE/28MPa 4258
Type - Identity Data - Assembly Code: B1010310; Assembly Description: Beams - CIP; Type Name: 500*400 4543
Type - Materials and Finishes - Material: CONCRETE/28MPa 4258
Type - Other - Category: Structural Framing; Family Name: 500*400 4543
Type - Structural - Section Shape: 0
Type - Pset_BuildingElementProxyCommon - Reference: 500*400 4543
Type - Pset_ProductRequirements - Category: Structural Framing
Type - Pset_QuantityTakeOff - Reference: 500*400 4543
Pset_BuildingElementProxyCommon - sets with these values: 2
Constraints - Moves With Nearby Elements: no; Level: Level: Default; Host: Level : Default; Offset: -150 mm
Dimensions - Area: 7.52527 m2; Volume: 1.62784 m3
Other - Family: 500*400 4543: 500*400 4543; Family and Type: 500*400 4543: 500*400 4543; Type: 500*400 4543: 500*400 4543; Type Id: 500*400 4543: 500*400 4543
Phasing - Phase Created: New Construction
Structural - Rebar Cover - Other Faces: Rebar Cover Settings: Rebar Cover 1; Rebar Cover - Bottom Face: Rebar Cover Settings: Rebar Cover 1; Rebar Cover - Top Face: Rebar Cover Settings: Rebar Cover 1

# IfcBuildingElementProxy: 500*400 4569 (6)
In: Default
Type - Classification: B1010310 Beams - CIP (Uniformat); Material: CONCRETE/28MPa 4258
Type - Identity Data - Assembly Code: B1010310; Assembly Description: Beams - CIP; Type Name: 500*400 4569
Type - Materials and Finishes - Material: CONCRETE/28MPa 4258
Type - Other - Category: Structural Framing; Family Name: 500*400 4569
Type - Structural - Section Shape: 0
Type - Pset_BuildingElementProxyCommon - Reference: 500*400 4569
Type - Pset_ProductRequirements - Category: Structural Framing
Type - Pset_QuantityTakeOff - Reference: 500*400 4569
Pset_BuildingElementProxyCommon - sets with these values: 2
Constraints - Moves With Nearby Elements: no; Level: Level: Default; Host: Level : Default; Offset: -150 mm
Dimensions - Area: 7.52547 m2; Volume: 1.62788 m3
Other - Family: 500*400 4569: 500*400 4569; Family and Type: 500*400 4569: 500*400 4569; Type: 500*400 4569: 500*400 4569; Type Id: 500*400 4569: 500*400 4569
Phasing - Phase Created: New Construction
Structural - Rebar Cover - Other Faces: Rebar Cover Settings: Rebar Cover 1; Rebar Cover - Bottom Face: Rebar Cover Settings: Rebar Cover 1; Rebar Cover - Top Face: Rebar Cover Settings: Rebar Cover 1
Name (500*400 4569:500*400 4569:...)
212279
212280
212281
212282
212283
212284

# IfcBuildingElementProxy: 500*400 4658, 500*400 4658:500*400 4658:212278
In: Default
Type - Classification: B1010310 Beams - CIP (Uniformat); Material: CONCRETE/28MPa 4258
Type - Identity Data - Assembly Code: B1010310; Assembly Description: Beams - CIP; Type Name: 500*400 4658
Type - Materials and Finishes - Material: CONCRETE/28MPa 4258
Type - Other - Category: Structural Framing; Family Name: 500*400 4658
Type - Structural - Section Shape: 0
Type - Pset_BuildingElementProxyCommon - Reference: 500*400 4658
Type - Pset_ProductRequirements - Category: Structural Framing
Type - Pset_QuantityTakeOff - Reference: 500*400 4658
Pset_BuildingElementProxyCommon - sets with these values: 2
Constraints - Moves With Nearby Elements: no; Level: Level: Default; Host: Level : Default; Offset: -150 mm
Dimensions - Area: 7.72797 m2; Volume: 1.67288 m3
Other - Family: 500*400 4658: 500*400 4658; Family and Type: 500*400 4658: 500*400 4658; Type: 500*400 4658: 500*400 4658; Type Id: 500*400 4658: 500*400 4658
Phasing - Phase Created: New Construction
Structural - Rebar Cover - Other Faces: Rebar Cover Settings: Rebar Cover 1; Rebar Cover - Bottom Face: Rebar Cover Settings: Rebar Cover 1; Rebar Cover - Top Face: Rebar Cover Settings: Rebar Cover 1

# IfcBuildingElementProxy: 500*400 4752, 500*400 4752:500*400 4752:212270
In: Default
Type - Classification: B1010310 Beams - CIP (Uniformat); Material: CONCRETE/28MPa 4258
Type - Identity Data - Assembly Code: B1010310; Assembly Description: Beams - CIP; Type Name: 500*400 4752
Type - Materials and Finishes - Material: CONCRETE/28MPa 4258
Type - Other - Category: Structural Framing; Family Name: 500*400 4752
Type - Structural - Section Shape: 0
Type - Pset_BuildingElementProxyCommon - Reference: 500*400 4752
Type - Pset_ProductRequirements - Category: Structural Framing
Type - Pset_QuantityTakeOff - Reference: 500*400 4752
Pset_BuildingElementProxyCommon - sets with these values: 2
Constraints - Moves With Nearby Elements: no; Level: Level: Default; Host: Level : Default; Offset: -150 mm
Dimensions - Area: 7.39858 m2; Volume: 1.59968 m3
Other - Family: 500*400 4752: 500*400 4752; Family and Type: 500*400 4752: 500*400 4752; Type: 500*400 4752: 500*400 4752; Type Id: 500*400 4752: 500*400 4752
Phasing - Phase Created: New Construction
Structural - Rebar Cover - Other Faces: Rebar Cover Settings: Rebar Cover 1; Rebar Cover - Bottom Face: Rebar Cover Settings: Rebar Cover 1; Rebar Cover - Top Face: Rebar Cover Settings: Rebar Cover 1

# IfcBuildingElementProxy: VIGA, VIGA:VIGA:224966
In: Default
Type - Description: IARM1800; Classification: B1020250 Joists - Steel (Uniformat)
Type - Identity Data - Assembly Code: B1020250; Assembly Description: Joists - Steel; Type Name: VIGA
Type - Other - Category: Structural Framing; Family Name: VIGA
Type - Structural - Section Shape: 0
Type - Pset_BuildingElementProxyCommon - Reference: Pr/0(?)
Type - Pset_ProductRequirements - Name: VIGA; Category: Structural Framing
Type - Pset_QuantityTakeOff - Reference: Pr/0(?)
Pset_BuildingElementProxyCommon - sets with these values: 2
Constraints - Moves With Nearby Elements: no
Dimensions - Area: 106.863 m2
Other - Family: VIGA: VIGA; Family and Type: VIGA: VIGA; Type: VIGA: VIGA; Type Id: VIGA: VIGA
Phasing - Phase Created: New Construction
Structural - Rebar Cover: Rebar Cover Settings: Rebar Cover 1

# IfcBuildingElementProxy: VIGA, VIGA 189:VIGA 189:224973
In: Default
Type - Description: IARM1800; Classification: B1020250 Joists - Steel (Uniformat)
Type - Identity Data - Assembly Code: B1020250; Assembly Description: Joists - Steel; Type Name: VIGA 189
Type - Other - Category: Structural Framing; Family Name: VIGA 189
Type - Structural - Section Shape: 0
Type - Pset_BuildingElementProxyCommon - Reference: Pr/0(?)
Type - Pset_ProductRequirements - Name: VIGA; Category: Structural Framing
Type - Pset_QuantityTakeOff - Reference: Pr/0(?)
Pset_BuildingElementProxyCommon - sets with these values: 2
Constraints - Moves With Nearby Elements: no
Dimensions - Area: 106.797 m2
Other - Family: VIGA 189: VIGA 189; Family and Type: VIGA 189: VIGA 189; Type: VIGA 189: VIGA 189; Type Id: VIGA 189: VIGA 189
Phasing - Phase Created: New Construction
Structural - Rebar Cover: Rebar Cover Settings: Rebar Cover 1

# IfcBuildingElementProxy: VIGA, VIGA 221:VIGA 221:224980
In: Default
Type - Description: IARM1800; Classification: B1020250 Joists - Steel (Uniformat)
Type - Identity Data - Assembly Code: B1020250; Assembly Description: Joists - Steel; Type Name: VIGA 221
Type - Other - Category: Structural Framing; Family Name: VIGA 221
Type - Structural - Section Shape: 0
Type - Pset_BuildingElementProxyCommon - Reference: Pr/0(?)
Type - Pset_ProductRequirements - Name: VIGA; Category: Structural Framing
Type - Pset_QuantityTakeOff - Reference: Pr/0(?)
Pset_BuildingElementProxyCommon - sets with these values: 2
Constraints - Moves With Nearby Elements: no
Dimensions - Area: 106.814 m2
Other - Family: VIGA 221: VIGA 221; Family and Type: VIGA 221: VIGA 221; Type: VIGA 221: VIGA 221; Type Id: VIGA 221: VIGA 221
Phasing - Phase Created: New Construction
Structural - Rebar Cover: Rebar Cover Settings: Rebar Cover 1

# IfcBuildingElementProxy: VIGA, VIGA 252:VIGA 252:224987
In: Default
Type - Description: IARM1800; Classification: B1020250 Joists - Steel (Uniformat)
Type - Identity Data - Assembly Code: B1020250; Assembly Description: Joists - Steel; Type Name: VIGA 252
Type - Other - Category: Structural Framing; Family Name: VIGA 252
Type - Structural - Section Shape: 0
Type - Pset_BuildingElementProxyCommon - Reference: Pr/0(?)
Type - Pset_ProductRequirements - Name: VIGA; Category: Structural Framing
Type - Pset_QuantityTakeOff - Reference: Pr/0(?)
Pset_BuildingElementProxyCommon - sets with these values: 2
Constraints - Moves With Nearby Elements: no
Dimensions - Area: 106.917 m2
Other - Family: VIGA 252: VIGA 252; Family and Type: VIGA 252: VIGA 252; Type: VIGA 252: VIGA 252; Type Id: VIGA 252: VIGA 252
Phasing - Phase Created: New Construction
Structural - Rebar Cover: Rebar Cover Settings: Rebar Cover 1

# IfcBuildingElementProxy: VIGA, VIGA 284:VIGA 284:224994
In: Default
Type - Description: IARM1800; Classification: B1020250 Joists - Steel (Uniformat)
Type - Identity Data - Assembly Code: B1020250; Assembly Description: Joists - Steel; Type Name: VIGA 284
Type - Other - Category: Structural Framing; Family Name: VIGA 284
Type - Structural - Section Shape: 0
Type - Pset_BuildingElementProxyCommon - Reference: Pr/0(?)
Type - Pset_ProductRequirements - Name: VIGA; Category: Structural Framing
Type - Pset_QuantityTakeOff - Reference: Pr/0(?)
Pset_BuildingElementProxyCommon - sets with these values: 2
Constraints - Moves With Nearby Elements: no
Dimensions - Area: 107.111 m2
Other - Family: VIGA 284: VIGA 284; Family and Type: VIGA 284: VIGA 284; Type: VIGA 284: VIGA 284; Type Id: VIGA 284: VIGA 284
Phasing - Phase Created: New Construction
Structural - Rebar Cover: Rebar Cover Settings: Rebar Cover 1

# IfcBuildingElementProxy: VIGA, VIGA 316:VIGA 316:225001
In: Default
Type - Description: IARM1800; Classification: B1020250 Joists - Steel (Uniformat)
Type - Identity Data - Assembly Code: B1020250; Assembly Description: Joists - Steel; Type Name: VIGA 316
Type - Other - Category: Structural Framing; Family Name: VIGA 316
Type - Structural - Section Shape: 0
Type - Pset_BuildingElementProxyCommon - Reference: Pr/0(?)
Type - Pset_ProductRequirements - Name: VIGA; Category: Structural Framing
Type - Pset_QuantityTakeOff - Reference: Pr/0(?)
Pset_BuildingElementProxyCommon - sets with these values: 2
Constraints - Moves With Nearby Elements: no
Dimensions - Area: 107.395 m2
Other - Family: VIGA 316: VIGA 316; Family and Type: VIGA 316: VIGA 316; Type: VIGA 316: VIGA 316; Type Id: VIGA 316: VIGA 316
Phasing - Phase Created: New Construction
Structural - Rebar Cover: Rebar Cover Settings: Rebar Cover 1

# IfcBuildingElementProxy: VIGA, VIGA 348:VIGA 348:225008
In: Default
Type - Description: IARM1800; Classification: B1020250 Joists - Steel (Uniformat)
Type - Identity Data - Assembly Code: B1020250; Assembly Description: Joists - Steel; Type Name: VIGA 348
Type - Other - Category: Structural Framing; Family Name: VIGA 348
Type - Structural - Section Shape: 0
Type - Pset_BuildingElementProxyCommon - Reference: Pr/0(?)
Type - Pset_ProductRequirements - Name: VIGA; Category: Structural Framing
Type - Pset_QuantityTakeOff - Reference: Pr/0(?)
Pset_BuildingElementProxyCommon - sets with these values: 2
Constraints - Moves With Nearby Elements: no
Dimensions - Area: 108.232 m2
Other - Family: VIGA 348: VIGA 348; Family and Type: VIGA 348: VIGA 348; Type: VIGA 348: VIGA 348; Type Id: VIGA 348: VIGA 348
Phasing - Phase Created: New Construction
Structural - Rebar Cover: Rebar Cover Settings: Rebar Cover 1

# IfcBuildingElementProxy: VIGA, VIGA 380:VIGA 380:225015
In: Default
Type - Description: IARM1800; Classification: B1020250 Joists - Steel (Uniformat)
Type - Identity Data - Assembly Code: B1020250; Assembly Description: Joists - Steel; Type Name: VIGA 380
Type - Other - Category: Structural Framing; Family Name: VIGA 380
Type - Structural - Section Shape: 0
Type - Pset_BuildingElementProxyCommon - Reference: Pr/0(?)
Type - Pset_ProductRequirements - Name: VIGA; Category: Structural Framing
Type - Pset_QuantityTakeOff - Reference: Pr/0(?)
Pset_BuildingElementProxyCommon - sets with these values: 2
Constraints - Moves With Nearby Elements: no
Dimensions - Area: 107.768 m2
Other - Family: VIGA 380: VIGA 380; Family and Type: VIGA 380: VIGA 380; Type: VIGA 380: VIGA 380; Type Id: VIGA 380: VIGA 380
Phasing - Phase Created: New Construction
Structural - Rebar Cover: Rebar Cover Settings: Rebar Cover 1

# IfcColumn: 400*400 (9)
In: Default
Type - PredefinedType: COLUMN
Type - Graphics - Coarse Scale Fill Color: 0
Type - Identity Data - Assembly Code: B1010240; Assembly Description: Columns - CIP; Type Name: 400*400
Type - Materials and Finishes - Material: CONCRETE/28MPa 1864
Type - Other - Category: Structural Columns; Family Name: 400*400
Type - Structural - Section Shape: 0
Type - Pset_ColumnCommon - IsExternal: no; LoadBearing: yes; Reference: 400*400
Type - Pset_ProductRequirements - Category: Structural Columns
Type - Pset_QuantityTakeOff - Reference: 400*400
Type - Pset_ReinforcementBarPitchOfColumn - Reference: 400*400
Classification: B1010240 Columns - CIP (Uniformat); Material: CONCRETE/28MPa 1864
BaseQuantities - GrossVolume: 0.448 m3
Pset_ColumnCommon - Slope: 0 rad
Pset_QuantityTakeOff - sets with these values: 2
Constraints - Moves With Grids: yes; Base Level: Level: Default; Base Offset: -3000 mm; Column Style: Vertical; Top Level: Level: Default; Top Offset: -200 mm
Dimensions - Area: 2.4 m2; Length: 2800 mm; Volume: 0.448 m3
Materials and Finishes - Structural Material: CONCRETE/28MPa 1864
Other - Family: 400*400: 400*400; Family and Type: 400*400: 400*400; Type: 400*400: 400*400; Type Id: 400*400: 400*400
Phasing - Phase Created: New Construction
Structural - Enable Analytical Model: yes
Name (400*400:400*400:...)
212214
212240
212242
212244
212246
212248
212250
212252
212254

# IfcColumn: COLUMNA, COLUMNA:COLUMNA:202887
In: Default
Type - Description: 600*1000; PredefinedType: COLUMN; Classification: B1010240 Columns - CIP (Uniformat)
Type - Graphics - Coarse Scale Fill Color: 0
Type - Identity Data - Assembly Code: B1010240; Assembly Description: Columns - CIP; Type Name: COLUMNA
Type - Other - Category: Columns; Family Name: COLUMNA
Type - Pset_ColumnCommon - IsExternal: no; LoadBearing: yes; Reference: CC/0(?)
Type - Pset_ProductRequirements - Name: COLUMNA; Category: Columns
Type - Pset_QuantityTakeOff - Reference: CC/0(?)
Type - Pset_ReinforcementBarPitchOfColumn - Reference: CC/0(?)
BaseQuantities - GrossVolume: 0.890212 m3
Pset_ColumnCommon - Slope: 0 rad
Pset_QuantityTakeOff - sets with these values: 2
Constraints - Moves With Grids: yes; Moves With Nearby Elements: yes; Room Bounding: yes
Dimensions - Area: 0.604563 m2; Volume: 0.890212 m3
Other - Family: COLUMNA: COLUMNA; Family and Type: COLUMNA: COLUMNA; Type: COLUMNA: COLUMNA; Type Id: COLUMNA: COLUMNA
Phasing - Phase Created: New Construction

# IfcColumn: COLUMNA, COLUMNA 1923:COLUMNA 1923:202909
In: Default
Type - Description: 600*1000; PredefinedType: COLUMN; Classification: B1010240 Columns - CIP (Uniformat)
Type - Graphics - Coarse Scale Fill Color: 0
Type - Identity Data - Assembly Code: B1010240; Assembly Description: Columns - CIP; Type Name: COLUMNA 1923
Type - Other - Category: Columns; Family Name: COLUMNA 1923
Type - Pset_ColumnCommon - IsExternal: no; LoadBearing: yes; Reference: CC/0(?)
Type - Pset_ProductRequirements - Name: COLUMNA; Category: Columns
Type - Pset_QuantityTakeOff - Reference: CC/0(?)
Type - Pset_ReinforcementBarPitchOfColumn - Reference: CC/0(?)
BaseQuantities - GrossVolume: 1.35017 m3
Pset_ColumnCommon - Slope: 0 rad
Pset_QuantityTakeOff - sets with these values: 2
Constraints - Moves With Grids: yes; Moves With Nearby Elements: yes; Room Bounding: yes
Dimensions - Area: 0.608904 m2; Volume: 1.35017 m3
Other - Family: COLUMNA 1923: COLUMNA 1923; Family and Type: COLUMNA 1923: COLUMNA 1923; Type: COLUMNA 1923: COLUMNA 1923; Type Id: COLUMNA 1923: COLUMNA 1923
Phasing - Phase Created: New Construction

# IfcColumn: COLUMNA, COLUMNA 1958:COLUMNA 1958:202931
In: Default
Type - Description: 600*1000; PredefinedType: COLUMN; Classification: B1010240 Columns - CIP (Uniformat)
Type - Graphics - Coarse Scale Fill Color: 0
Type - Identity Data - Assembly Code: B1010240; Assembly Description: Columns - CIP; Type Name: COLUMNA 1958
Type - Other - Category: Columns; Family Name: COLUMNA 1958
Type - Pset_ColumnCommon - IsExternal: no; LoadBearing: yes; Reference: P/0(?)
Type - Pset_ProductRequirements - Name: COLUMNA; Category: Columns
Type - Pset_QuantityTakeOff - Reference: P/0(?)
Type - Pset_ReinforcementBarPitchOfColumn - Reference: P/0(?)
BaseQuantities - GrossVolume: 4.83015 m3
Pset_ColumnCommon - Slope: 0 rad
Pset_QuantityTakeOff - sets with these values: 2
Constraints - Moves With Grids: yes; Moves With Nearby Elements: yes; Room Bounding: yes
Dimensions - Area: 0.632119 m2; Volume: 4.83015 m3
Other - Family: COLUMNA 1958: COLUMNA 1958; Family and Type: COLUMNA 1958: COLUMNA 1958; Type: COLUMNA 1958: COLUMNA 1958; Type Id: COLUMNA 1958: COLUMNA 1958
Phasing - Phase Created: New Construction

# IfcColumn: COLUMNA, COLUMNA 1994:COLUMNA 1994:202953
In: Default
Type - Description: 600*1000; PredefinedType: COLUMN; Classification: B1010240 Columns - CIP (Uniformat)
Type - Graphics - Coarse Scale Fill Color: 0
Type - Identity Data - Assembly Code: B1010240; Assembly Description: Columns - CIP; Type Name: COLUMNA 1994
Type - Other - Category: Columns; Family Name: COLUMNA 1994
Type - Pset_ColumnCommon - IsExternal: no; LoadBearing: yes; Reference: P/0(?)
Type - Pset_ProductRequirements - Name: COLUMNA; Category: Columns
Type - Pset_QuantityTakeOff - Reference: P/0(?)
Type - Pset_ReinforcementBarPitchOfColumn - Reference: P/0(?)
BaseQuantities - GrossVolume: 4.0901 m3
Pset_ColumnCommon - Slope: 0 rad
Pset_QuantityTakeOff - sets with these values: 2
Constraints - Moves With Grids: yes; Moves With Nearby Elements: yes; Room Bounding: yes
Dimensions - Area: 0.632119 m2; Volume: 4.0901 m3
Other - Family: COLUMNA 1994: COLUMNA 1994; Family and Type: COLUMNA 1994: COLUMNA 1994; Type: COLUMNA 1994: COLUMNA 1994; Type Id: COLUMNA 1994: COLUMNA 1994
Phasing - Phase Created: New Construction

# IfcColumn: COLUMNA, COLUMNA 2029:COLUMNA 2029:202975
In: Default
Type - Description: 600*1000; PredefinedType: COLUMN; Classification: B1010240 Columns - CIP (Uniformat)
Type - Graphics - Coarse Scale Fill Color: 0
Type - Identity Data - Assembly Code: B1010240; Assembly Description: Columns - CIP; Type Name: COLUMNA 2029
Type - Other - Category: Columns; Family Name: COLUMNA 2029
Type - Pset_ColumnCommon - IsExternal: no; LoadBearing: yes; Reference: CC/0(?)
Type - Pset_ProductRequirements - Name: COLUMNA; Category: Columns
Type - Pset_QuantityTakeOff - Reference: CC/0(?)
Type - Pset_ReinforcementBarPitchOfColumn - Reference: CC/0(?)
BaseQuantities - GrossVolume: 2.0634 m3
Pset_ColumnCommon - Slope: 0 rad
Pset_QuantityTakeOff - sets with these values: 2
Constraints - Moves With Grids: yes; Moves With Nearby Elements: yes; Room Bounding: yes
Dimensions - Area: 0.608904 m2; Volume: 2.0634 m3
Other - Family: COLUMNA 2029: COLUMNA 2029; Family and Type: COLUMNA 2029: COLUMNA 2029; Type: COLUMNA 2029: COLUMNA 2029; Type Id: COLUMNA 2029: COLUMNA 2029
Phasing - Phase Created: New Construction

# IfcColumn: COLUMNA, COLUMNA 2064:COLUMNA 2064:202997
In: Default
Type - Description: 600*1000; PredefinedType: COLUMN; Classification: B1010240 Columns - CIP (Uniformat)
Type - Graphics - Coarse Scale Fill Color: 0
Type - Identity Data - Assembly Code: B1010240; Assembly Description: Columns - CIP; Type Name: COLUMNA 2064
Type - Other - Category: Columns; Family Name: COLUMNA 2064
Type - Pset_ColumnCommon - IsExternal: no; LoadBearing: yes; Reference: CC/0(?)
Type - Pset_ProductRequirements - Name: COLUMNA; Category: Columns
Type - Pset_QuantityTakeOff - Reference: CC/0(?)
Type - Pset_ReinforcementBarPitchOfColumn - Reference: CC/0(?)
BaseQuantities - GrossVolume: 2.4857 m3
Pset_ColumnCommon - Slope: 0 rad
Pset_QuantityTakeOff - sets with these values: 2
Constraints - Moves With Grids: yes; Moves With Nearby Elements: yes; Room Bounding: yes
Dimensions - Area: 0.615557 m2; Volume: 2.4857 m3
Other - Family: COLUMNA 2064: COLUMNA 2064; Family and Type: COLUMNA 2064: COLUMNA 2064; Type: COLUMNA 2064: COLUMNA 2064; Type Id: COLUMNA 2064: COLUMNA 2064
Phasing - Phase Created: New Construction

# IfcColumn: COLUMNA, COLUMNA 2100:COLUMNA 2100:203019
In: Default
Type - Description: 600*1000; PredefinedType: COLUMN; Classification: B1010240 Columns - CIP (Uniformat)
Type - Graphics - Coarse Scale Fill Color: 0
Type - Identity Data - Assembly Code: B1010240; Assembly Description: Columns - CIP; Type Name: COLUMNA 2100
Type - Other - Category: Columns; Family Name: COLUMNA 2100
Type - Pset_ColumnCommon - IsExternal: no; LoadBearing: yes; Reference: CC/0(?)
Type - Pset_ProductRequirements - Name: COLUMNA; Category: Columns
Type - Pset_QuantityTakeOff - Reference: CC/0(?)
Type - Pset_ReinforcementBarPitchOfColumn - Reference: CC/0(?)
BaseQuantities - GrossVolume: 2.9668 m3
Pset_ColumnCommon - Slope: 0 rad
Pset_QuantityTakeOff - sets with these values: 2
Constraints - Moves With Grids: yes; Moves With Nearby Elements: yes; Room Bounding: yes
Dimensions - Area: 0.616662 m2; Volume: 2.9668 m3
Other - Family: COLUMNA 2100: COLUMNA 2100; Family and Type: COLUMNA 2100: COLUMNA 2100; Type: COLUMNA 2100: COLUMNA 2100; Type Id: COLUMNA 2100: COLUMNA 2100
Phasing - Phase Created: New Construction

# IfcColumn: COLUMNA, COLUMNA 2136:COLUMNA 2136:203041
In: Default
Type - Description: 600*1000; PredefinedType: COLUMN; Classification: B1010240 Columns - CIP (Uniformat)
Type - Graphics - Coarse Scale Fill Color: 0
Type - Identity Data - Assembly Code: B1010240; Assembly Description: Columns - CIP; Type Name: COLUMNA 2136
Type - Other - Category: Columns; Family Name: COLUMNA 2136
Type - Pset_ColumnCommon - IsExternal: no; LoadBearing: yes; Reference: P/0(?)
Type - Pset_ProductRequirements - Name: COLUMNA; Category: Columns
Type - Pset_QuantityTakeOff - Reference: P/0(?)
Type - Pset_ReinforcementBarPitchOfColumn - Reference: P/0(?)
BaseQuantities - GrossVolume: 3.37685 m3
Pset_ColumnCommon - Slope: 0 rad
Pset_QuantityTakeOff - sets with these values: 2
Constraints - Moves With Grids: yes; Moves With Nearby Elements: yes; Room Bounding: yes
Dimensions - Area: 0.632118 m2; Volume: 3.37685 m3
Other - Family: COLUMNA 2136: COLUMNA 2136; Family and Type: COLUMNA 2136: COLUMNA 2136; Type: COLUMNA 2136: COLUMNA 2136; Type Id: COLUMNA 2136: COLUMNA 2136
Phasing - Phase Created: New Construction

# IfcColumn: COLUMNA, COLUMNA 2170:COLUMNA 2170:203063
In: Default
Type - Description: 600*1000; PredefinedType: COLUMN; Classification: B1010240 Columns - CIP (Uniformat)
Type - Graphics - Coarse Scale Fill Color: 0
Type - Identity Data - Assembly Code: B1010240; Assembly Description: Columns - CIP; Type Name: COLUMNA 2170
Type - Other - Category: Columns; Family Name: COLUMNA 2170
Type - Pset_ColumnCommon - IsExternal: no; LoadBearing: yes; Reference: P/0(?)
Type - Pset_ProductRequirements - Name: COLUMNA; Category: Columns
Type - Pset_QuantityTakeOff - Reference: P/0(?)
Type - Pset_ReinforcementBarPitchOfColumn - Reference: P/0(?)
BaseQuantities - GrossVolume: 3.12031 m3
Pset_ColumnCommon - Slope: 0 rad
Pset_QuantityTakeOff - sets with these values: 2
Constraints - Moves With Grids: yes; Moves With Nearby Elements: yes; Room Bounding: yes
Dimensions - Area: 0.632118 m2; Volume: 3.12031 m3
Other - Family: COLUMNA 2170: COLUMNA 2170; Family and Type: COLUMNA 2170: COLUMNA 2170; Type: COLUMNA 2170: COLUMNA 2170; Type Id: COLUMNA 2170: COLUMNA 2170
Phasing - Phase Created: New Construction

# IfcColumn: COLUMNA, COLUMNA 2203:COLUMNA 2203:203085
In: Default
Type - Description: 600*1000; PredefinedType: COLUMN; Classification: B1010240 Columns - CIP (Uniformat)
Type - Graphics - Coarse Scale Fill Color: 0
Type - Identity Data - Assembly Code: B1010240; Assembly Description: Columns - CIP; Type Name: COLUMNA 2203
Type - Other - Category: Columns; Family Name: COLUMNA 2203
Type - Pset_ColumnCommon - IsExternal: no; LoadBearing: yes; Reference: P/0(?)
Type - Pset_ProductRequirements - Name: COLUMNA; Category: Columns
Type - Pset_QuantityTakeOff - Reference: P/0(?)
Type - Pset_ReinforcementBarPitchOfColumn - Reference: P/0(?)
BaseQuantities - GrossVolume: 2.38025 m3
Pset_ColumnCommon - Slope: 0 rad
Pset_QuantityTakeOff - sets with these values: 2
Constraints - Moves With Grids: yes; Moves With Nearby Elements: yes; Room Bounding: yes
Dimensions - Area: 0.632118 m2; Volume: 2.38025 m3
Other - Family: COLUMNA 2203: COLUMNA 2203; Family and Type: COLUMNA 2203: COLUMNA 2203; Type: COLUMNA 2203: COLUMNA 2203; Type Id: COLUMNA 2203: COLUMNA 2203
Phasing - Phase Created: New Construction

# IfcColumn: COLUMNA, COLUMNA 2498:COLUMNA 2498:203305
In: Default
Type - Description: 600*1000; PredefinedType: COLUMN; Classification: B1010240 Columns - CIP (Uniformat)
Type - Graphics - Coarse Scale Fill Color: 0
Type - Identity Data - Assembly Code: B1010240; Assembly Description: Columns - CIP; Type Name: COLUMNA 2498
Type - Other - Category: Columns; Family Name: COLUMNA 2498
Type - Pset_ColumnCommon - IsExternal: no; LoadBearing: yes; Reference: CC/0(?)
Type - Pset_ProductRequirements - Name: COLUMNA; Category: Columns
Type - Pset_QuantityTakeOff - Reference: CC/0(?)
Type - Pset_ReinforcementBarPitchOfColumn - Reference: CC/0(?)
BaseQuantities - GrossVolume: 1.17984 m3
Pset_ColumnCommon - Slope: 0 rad
Pset_QuantityTakeOff - sets with these values: 2
Constraints - Moves With Grids: yes; Moves With Nearby Elements: yes; Room Bounding: yes
Dimensions - Area: 0.608909 m2; Volume: 1.17984 m3
Other - Family: COLUMNA 2498: COLUMNA 2498; Family and Type: COLUMNA 2498: COLUMNA 2498; Type: COLUMNA 2498: COLUMNA 2498; Type Id: COLUMNA 2498: COLUMNA 2498
Phasing - Phase Created: New Construction

# IfcColumn: COLUMNA, COLUMNA 2534:COLUMNA 2534:203327
In: Default
Type - Description: 600*1000; PredefinedType: COLUMN; Classification: B1010240 Columns - CIP (Uniformat)
Type - Graphics - Coarse Scale Fill Color: 0
Type - Identity Data - Assembly Code: B1010240; Assembly Description: Columns - CIP; Type Name: COLUMNA 2534
Type - Other - Category: Columns; Family Name: COLUMNA 2534
Type - Pset_ColumnCommon - IsExternal: no; LoadBearing: yes; Reference: CC/0(?)
Type - Pset_ProductRequirements - Name: COLUMNA; Category: Columns
Type - Pset_QuantityTakeOff - Reference: CC/0(?)
Type - Pset_ReinforcementBarPitchOfColumn - Reference: CC/0(?)
BaseQuantities - GrossVolume: 1.31141 m3
Pset_ColumnCommon - Slope: 0 rad
Pset_QuantityTakeOff - sets with these values: 2
Constraints - Moves With Grids: yes; Moves With Nearby Elements: yes; Room Bounding: yes
Dimensions - Area: 0.615557 m2; Volume: 1.31141 m3
Other - Family: COLUMNA 2534: COLUMNA 2534; Family and Type: COLUMNA 2534: COLUMNA 2534; Type: COLUMNA 2534: COLUMNA 2534; Type Id: COLUMNA 2534: COLUMNA 2534
Phasing - Phase Created: New Construction

# IfcColumn: COLUMNA, COLUMNA 2567:COLUMNA 2567:203349
In: Default
Type - Description: 600*1000; PredefinedType: COLUMN; Classification: B1010240 Columns - CIP (Uniformat)
Type - Graphics - Coarse Scale Fill Color: 0
Type - Identity Data - Assembly Code: B1010240; Assembly Description: Columns - CIP; Type Name: COLUMNA 2567
Type - Other - Category: Columns; Family Name: COLUMNA 2567
Type - Pset_ColumnCommon - IsExternal: no; LoadBearing: yes; Reference: CC/0(?)
Type - Pset_ProductRequirements - Name: COLUMNA; Category: Columns
Type - Pset_QuantityTakeOff - Reference: CC/0(?)
Type - Pset_ReinforcementBarPitchOfColumn - Reference: CC/0(?)
BaseQuantities - GrossVolume: 1.75044 m3
Pset_ColumnCommon - Slope: 0 rad
Pset_QuantityTakeOff - sets with these values: 2
Constraints - Moves With Grids: yes; Moves With Nearby Elements: yes; Room Bounding: yes
Dimensions - Area: 0.616662 m2; Volume: 1.75044 m3
Other - Family: COLUMNA 2567: COLUMNA 2567; Family and Type: COLUMNA 2567: COLUMNA 2567; Type: COLUMNA 2567: COLUMNA 2567; Type Id: COLUMNA 2567: COLUMNA 2567
Phasing - Phase Created: New Construction

# IfcColumn: COLUMNA, COLUMNA 2600:COLUMNA 2600:203371
In: Default
Type - Description: 600*1000; PredefinedType: COLUMN; Classification: B1010240 Columns - CIP (Uniformat)
Type - Graphics - Coarse Scale Fill Color: 0
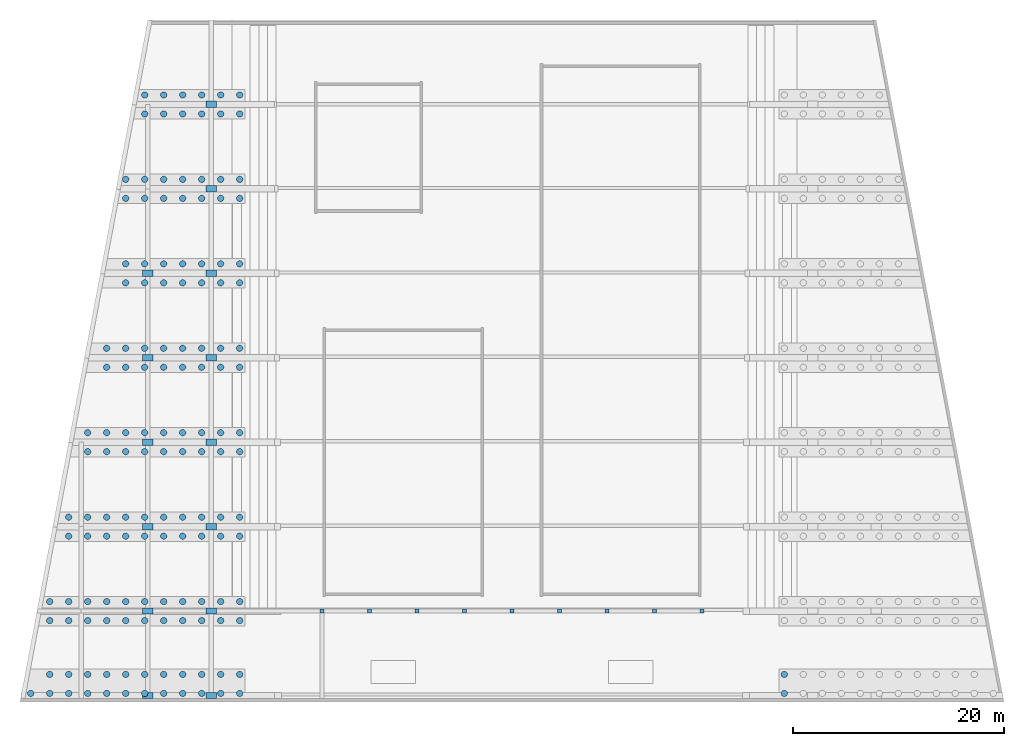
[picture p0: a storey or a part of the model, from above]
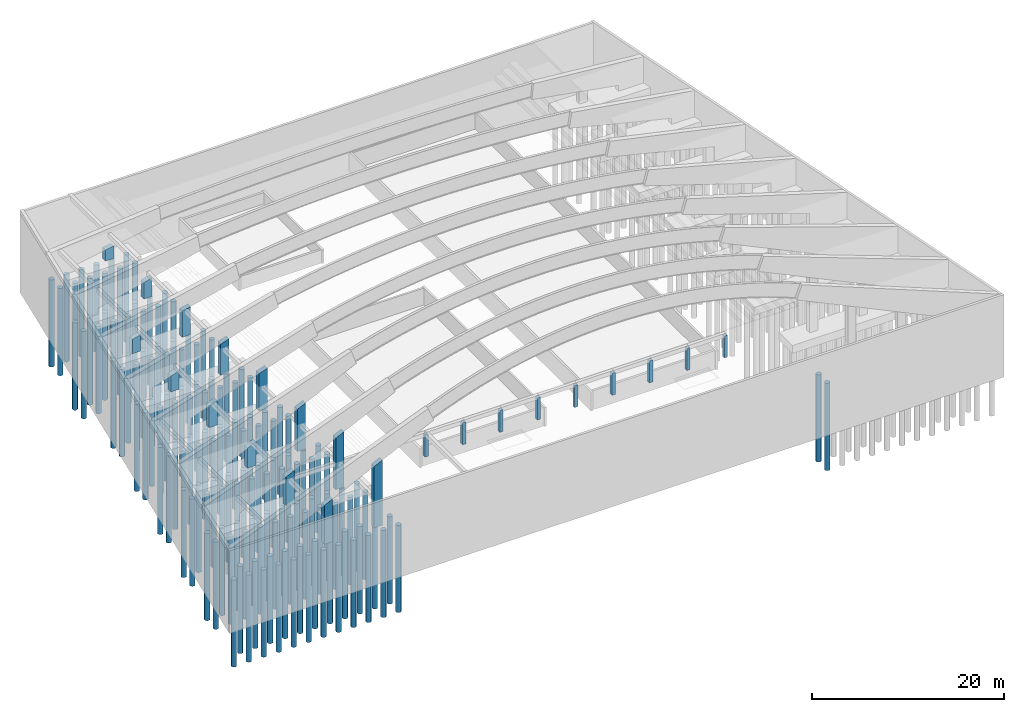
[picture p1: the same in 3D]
Properties of the parts of a building model (IFC2X3), part 2 of 5

# IfcColumn: COLUMNA, COLUMNA 2600:COLUMNA 2600:203371
Type - Identity Data - Assembly Code: B1010240; Assembly Description: Columns - CIP; Type Name: COLUMNA 2600
Type - Other - Category: Columns; Family Name: COLUMNA 2600
Type - Pset_ColumnCommon - IsExternal: no; LoadBearing: yes; Reference: P/0(?)
Type - Pset_ProductRequirements - Name: COLUMNA; Category: Columns
Type - Pset_QuantityTakeOff - Reference: P/0(?)
Type - Pset_ReinforcementBarPitchOfColumn - Reference: P/0(?)
BaseQuantities - GrossVolume: 1.66701 m3
Pset_ColumnCommon - Slope: 0 rad
Pset_QuantityTakeOff - sets with these values: 2
Constraints - Moves With Grids: yes; Moves With Nearby Elements: yes; Room Bounding: yes
Dimensions - Area: 0.632118 m2; Volume: 1.66701 m3
Other - Family: COLUMNA 2600: COLUMNA 2600; Family and Type: COLUMNA 2600: COLUMNA 2600; Type: COLUMNA 2600: COLUMNA 2600; Type Id: COLUMNA 2600: COLUMNA 2600
Phasing - Phase Created: New Construction

# IfcColumn: COLUMNA, COLUMNA 5091:COLUMNA 5091:203524
In: Default
Type - Description: 600*1000; PredefinedType: COLUMN; Classification: B1010240 Columns - CIP (Uniformat)
Type - Graphics - Coarse Scale Fill Color: 0
Type - Identity Data - Assembly Code: B1010240; Assembly Description: Columns - CIP; Type Name: COLUMNA 5091
Type - Other - Category: Columns; Family Name: COLUMNA 5091
Type - Pset_ColumnCommon - IsExternal: no; LoadBearing: yes; Reference: CC/0(?)
Type - Pset_ProductRequirements - Name: COLUMNA; Category: Columns
Type - Pset_QuantityTakeOff - Reference: CC/0(?)
Type - Pset_ReinforcementBarPitchOfColumn - Reference: CC/0(?)
BaseQuantities - GrossVolume: 0.890212 m3
Pset_ColumnCommon - Slope: 0 rad
Pset_QuantityTakeOff - sets with these values: 2
Constraints - Moves With Grids: yes; Moves With Nearby Elements: yes; Room Bounding: yes
Dimensions - Area: 0.604563 m2; Volume: 0.890212 m3
Other - Family: COLUMNA 5091: COLUMNA 5091; Family and Type: COLUMNA 5091: COLUMNA 5091; Type: COLUMNA 5091: COLUMNA 5091; Type Id: COLUMNA 5091: COLUMNA 5091
Phasing - Phase Created: New Construction

# IfcColumn: COLUMNA, COLUMNA 5110:COLUMNA 5110:203546
In: Default
Type - Description: 600*1000; PredefinedType: COLUMN; Classification: B1010240 Columns - CIP (Uniformat)
Type - Graphics - Coarse Scale Fill Color: 0
Type - Identity Data - Assembly Code: B1010240; Assembly Description: Columns - CIP; Type Name: COLUMNA 5110
Type - Other - Category: Columns; Family Name: COLUMNA 5110
Type - Pset_ColumnCommon - IsExternal: no; LoadBearing: yes; Reference: CC/0(?)
Type - Pset_ProductRequirements - Name: COLUMNA; Category: Columns
Type - Pset_QuantityTakeOff - Reference: CC/0(?)
Type - Pset_ReinforcementBarPitchOfColumn - Reference: CC/0(?)
BaseQuantities - GrossVolume: 1.35017 m3
Pset_ColumnCommon - Slope: 0 rad
Pset_QuantityTakeOff - sets with these values: 2
Constraints - Moves With Grids: yes; Moves With Nearby Elements: yes; Room Bounding: yes
Dimensions - Area: 0.608904 m2; Volume: 1.35017 m3
Other - Family: COLUMNA 5110: COLUMNA 5110; Family and Type: COLUMNA 5110: COLUMNA 5110; Type: COLUMNA 5110: COLUMNA 5110; Type Id: COLUMNA 5110: COLUMNA 5110
Phasing - Phase Created: New Construction

# IfcColumn: COLUMNA, COLUMNA 5129:COLUMNA 5129:203568
In: Default
Type - Description: 600*1000; PredefinedType: COLUMN; Classification: B1010240 Columns - CIP (Uniformat)
Type - Graphics - Coarse Scale Fill Color: 0
Type - Identity Data - Assembly Code: B1010240; Assembly Description: Columns - CIP; Type Name: COLUMNA 5129
Type - Other - Category: Columns; Family Name: COLUMNA 5129
Type - Pset_ColumnCommon - IsExternal: no; LoadBearing: yes; Reference: P/0(?)
Type - Pset_ProductRequirements - Name: COLUMNA; Category: Columns
Type - Pset_QuantityTakeOff - Reference: P/0(?)
Type - Pset_ReinforcementBarPitchOfColumn - Reference: P/0(?)
BaseQuantities - GrossVolume: 4.83015 m3
Pset_ColumnCommon - Slope: 0 rad
Pset_QuantityTakeOff - sets with these values: 2
Constraints - Moves With Grids: yes; Moves With Nearby Elements: yes; Room Bounding: yes
Dimensions - Area: 0.632119 m2; Volume: 4.83015 m3
Other - Family: COLUMNA 5129: COLUMNA 5129; Family and Type: COLUMNA 5129: COLUMNA 5129; Type: COLUMNA 5129: COLUMNA 5129; Type Id: COLUMNA 5129: COLUMNA 5129
Phasing - Phase Created: New Construction

# IfcColumn: COLUMNA, COLUMNA 5144:COLUMNA 5144:203590
In: Default
Type - Description: 600*1000; PredefinedType: COLUMN; Classification: B1010240 Columns - CIP (Uniformat)
Type - Graphics - Coarse Scale Fill Color: 0
Type - Identity Data - Assembly Code: B1010240; Assembly Description: Columns - CIP; Type Name: COLUMNA 5144
Type - Other - Category: Columns; Family Name: COLUMNA 5144
Type - Pset_ColumnCommon - IsExternal: no; LoadBearing: yes; Reference: P/0(?)
Type - Pset_ProductRequirements - Name: COLUMNA; Category: Columns
Type - Pset_QuantityTakeOff - Reference: P/0(?)
Type - Pset_ReinforcementBarPitchOfColumn - Reference: P/0(?)
BaseQuantities - GrossVolume: 4.0901 m3
Pset_ColumnCommon - Slope: 0 rad
Pset_QuantityTakeOff - sets with these values: 2
Constraints - Moves With Grids: yes; Moves With Nearby Elements: yes; Room Bounding: yes
Dimensions - Area: 0.632119 m2; Volume: 4.0901 m3
Other - Family: COLUMNA 5144: COLUMNA 5144; Family and Type: COLUMNA 5144: COLUMNA 5144; Type: COLUMNA 5144: COLUMNA 5144; Type Id: COLUMNA 5144: COLUMNA 5144
Phasing - Phase Created: New Construction

# IfcColumn: COLUMNA, COLUMNA 5165:COLUMNA 5165:203612
In: Default
Type - Description: 600*1000; PredefinedType: COLUMN; Classification: B1010240 Columns - CIP (Uniformat)
Type - Graphics - Coarse Scale Fill Color: 0
Type - Identity Data - Assembly Code: B1010240; Assembly Description: Columns - CIP; Type Name: COLUMNA 5165
Type - Other - Category: Columns; Family Name: COLUMNA 5165
Type - Pset_ColumnCommon - IsExternal: no; LoadBearing: yes; Reference: CC/0(?)
Type - Pset_ProductRequirements - Name: COLUMNA; Category: Columns
Type - Pset_QuantityTakeOff - Reference: CC/0(?)
Type - Pset_ReinforcementBarPitchOfColumn - Reference: CC/0(?)
BaseQuantities - GrossVolume: 2.0634 m3
Pset_ColumnCommon - Slope: 0 rad
Pset_QuantityTakeOff - sets with these values: 2
Constraints - Moves With Grids: yes; Moves With Nearby Elements: yes; Room Bounding: yes
Dimensions - Area: 0.608904 m2; Volume: 2.0634 m3
Other - Family: COLUMNA 5165: COLUMNA 5165; Family and Type: COLUMNA 5165: COLUMNA 5165; Type: COLUMNA 5165: COLUMNA 5165; Type Id: COLUMNA 5165: COLUMNA 5165
Phasing - Phase Created: New Construction

# IfcColumn: COLUMNA, COLUMNA 5184:COLUMNA 5184:203634
In: Default
Type - Description: 600*1000; PredefinedType: COLUMN; Classification: B1010240 Columns - CIP (Uniformat)
Type - Graphics - Coarse Scale Fill Color: 0
Type - Identity Data - Assembly Code: B1010240; Assembly Description: Columns - CIP; Type Name: COLUMNA 5184
Type - Other - Category: Columns; Family Name: COLUMNA 5184
Type - Pset_ColumnCommon - IsExternal: no; LoadBearing: yes; Reference: CC/0(?)
Type - Pset_ProductRequirements - Name: COLUMNA; Category: Columns
Type - Pset_QuantityTakeOff - Reference: CC/0(?)
Type - Pset_ReinforcementBarPitchOfColumn - Reference: CC/0(?)
BaseQuantities - GrossVolume: 2.4857 m3
Pset_ColumnCommon - Slope: 0 rad
Pset_QuantityTakeOff - sets with these values: 2
Constraints - Moves With Grids: yes; Moves With Nearby Elements: yes; Room Bounding: yes
Dimensions - Area: 0.615557 m2; Volume: 2.4857 m3
Other - Family: COLUMNA 5184: COLUMNA 5184; Family and Type: COLUMNA 5184: COLUMNA 5184; Type: COLUMNA 5184: COLUMNA 5184; Type Id: COLUMNA 5184: COLUMNA 5184
Phasing - Phase Created: New Construction

# IfcColumn: COLUMNA, COLUMNA 5203:COLUMNA 5203:203656
In: Default
Type - Description: 600*1000; PredefinedType: COLUMN; Classification: B1010240 Columns - CIP (Uniformat)
Type - Graphics - Coarse Scale Fill Color: 0
Type - Identity Data - Assembly Code: B1010240; Assembly Description: Columns - CIP; Type Name: COLUMNA 5203
Type - Other - Category: Columns; Family Name: COLUMNA 5203
Type - Pset_ColumnCommon - IsExternal: no; LoadBearing: yes; Reference: CC/0(?)
Type - Pset_ProductRequirements - Name: COLUMNA; Category: Columns
Type - Pset_QuantityTakeOff - Reference: CC/0(?)
Type - Pset_ReinforcementBarPitchOfColumn - Reference: CC/0(?)
BaseQuantities - GrossVolume: 2.9668 m3
Pset_ColumnCommon - Slope: 0 rad
Pset_QuantityTakeOff - sets with these values: 2
Constraints - Moves With Grids: yes; Moves With Nearby Elements: yes; Room Bounding: yes
Dimensions - Area: 0.616662 m2; Volume: 2.9668 m3
Other - Family: COLUMNA 5203: COLUMNA 5203; Family and Type: COLUMNA 5203: COLUMNA 5203; Type: COLUMNA 5203: COLUMNA 5203; Type Id: COLUMNA 5203: COLUMNA 5203
Phasing - Phase Created: New Construction

# IfcColumn: COLUMNA, COLUMNA 5224:COLUMNA 5224:203678
In: Default
Type - Description: 600*1000; PredefinedType: COLUMN; Classification: B1010240 Columns - CIP (Uniformat)
Type - Graphics - Coarse Scale Fill Color: 0
Type - Identity Data - Assembly Code: B1010240; Assembly Description: Columns - CIP; Type Name: COLUMNA 5224
Type - Other - Category: Columns; Family Name: COLUMNA 5224
Type - Pset_ColumnCommon - IsExternal: no; LoadBearing: yes; Reference: P/0(?)
Type - Pset_ProductRequirements - Name: COLUMNA; Category: Columns
Type - Pset_QuantityTakeOff - Reference: P/0(?)
Type - Pset_ReinforcementBarPitchOfColumn - Reference: P/0(?)
BaseQuantities - GrossVolume: 3.37685 m3
Pset_ColumnCommon - Slope: 0 rad
Pset_QuantityTakeOff - sets with these values: 2
Constraints - Moves With Grids: yes; Moves With Nearby Elements: yes; Room Bounding: yes
Dimensions - Area: 0.632118 m2; Volume: 3.37685 m3
Other - Family: COLUMNA 5224: COLUMNA 5224; Family and Type: COLUMNA 5224: COLUMNA 5224; Type: COLUMNA 5224: COLUMNA 5224; Type Id: COLUMNA 5224: COLUMNA 5224
Phasing - Phase Created: New Construction

# IfcColumn: COLUMNA, COLUMNA 5244:COLUMNA 5244:203700
In: Default
Type - Description: 600*1000; PredefinedType: COLUMN; Classification: B1010240 Columns - CIP (Uniformat)
Type - Graphics - Coarse Scale Fill Color: 0
Type - Identity Data - Assembly Code: B1010240; Assembly Description: Columns - CIP; Type Name: COLUMNA 5244
Type - Other - Category: Columns; Family Name: COLUMNA 5244
Type - Pset_ColumnCommon - IsExternal: no; LoadBearing: yes; Reference: P/0(?)
Type - Pset_ProductRequirements - Name: COLUMNA; Category: Columns
Type - Pset_QuantityTakeOff - Reference: P/0(?)
Type - Pset_ReinforcementBarPitchOfColumn - Reference: P/0(?)
BaseQuantities - GrossVolume: 3.12031 m3
Pset_ColumnCommon - Slope: 0 rad
Pset_QuantityTakeOff - sets with these values: 2
Constraints - Moves With Grids: yes; Moves With Nearby Elements: yes; Room Bounding: yes
Dimensions - Area: 0.632118 m2; Volume: 3.12031 m3
Other - Family: COLUMNA 5244: COLUMNA 5244; Family and Type: COLUMNA 5244: COLUMNA 5244; Type: COLUMNA 5244: COLUMNA 5244; Type Id: COLUMNA 5244: COLUMNA 5244
Phasing - Phase Created: New Construction

# IfcColumn: COLUMNA, COLUMNA 5262:COLUMNA 5262:203722
In: Default
Type - Description: 600*1000; PredefinedType: COLUMN; Classification: B1010240 Columns - CIP (Uniformat)
Type - Graphics - Coarse Scale Fill Color: 0
Type - Identity Data - Assembly Code: B1010240; Assembly Description: Columns - CIP; Type Name: COLUMNA 5262
Type - Other - Category: Columns; Family Name: COLUMNA 5262
Type - Pset_ColumnCommon - IsExternal: no; LoadBearing: yes; Reference: P/0(?)
Type - Pset_ProductRequirements - Name: COLUMNA; Category: Columns
Type - Pset_QuantityTakeOff - Reference: P/0(?)
Type - Pset_ReinforcementBarPitchOfColumn - Reference: P/0(?)
BaseQuantities - GrossVolume: 2.38025 m3
Pset_ColumnCommon - Slope: 0 rad
Pset_QuantityTakeOff - sets with these values: 2
Constraints - Moves With Grids: yes; Moves With Nearby Elements: yes; Room Bounding: yes
Dimensions - Area: 0.632118 m2; Volume: 2.38025 m3
Other - Family: COLUMNA 5262: COLUMNA 5262; Family and Type: COLUMNA 5262: COLUMNA 5262; Type: COLUMNA 5262: COLUMNA 5262; Type Id: COLUMNA 5262: COLUMNA 5262
Phasing - Phase Created: New Construction

# IfcColumn: COLUMNA, COLUMNA 5800:COLUMNA 5800:204014
In: Default
Type - Description: 600*1000; PredefinedType: COLUMN; Classification: B1010240 Columns - CIP (Uniformat)
Type - Graphics - Coarse Scale Fill Color: 0
Type - Identity Data - Assembly Code: B1010240; Assembly Description: Columns - CIP; Type Name: COLUMNA 5800
Type - Other - Category: Columns; Family Name: COLUMNA 5800
Type - Pset_ColumnCommon - IsExternal: no; LoadBearing: yes; Reference: CC/0(?)
Type - Pset_ProductRequirements - Name: COLUMNA; Category: Columns
Type - Pset_QuantityTakeOff - Reference: CC/0(?)
Type - Pset_ReinforcementBarPitchOfColumn - Reference: CC/0(?)
BaseQuantities - GrossVolume: 1.17984 m3
Pset_ColumnCommon - Slope: 0 rad
Pset_QuantityTakeOff - sets with these values: 2
Constraints - Moves With Grids: yes; Moves With Nearby Elements: yes; Room Bounding: yes
Dimensions - Area: 0.608909 m2; Volume: 1.17984 m3
Other - Family: COLUMNA 5800: COLUMNA 5800; Family and Type: COLUMNA 5800: COLUMNA 5800; Type: COLUMNA 5800: COLUMNA 5800; Type Id: COLUMNA 5800: COLUMNA 5800
Phasing - Phase Created: New Construction

# IfcColumn: COLUMNA, COLUMNA 5822:COLUMNA 5822:204037
In: Default
Type - Description: 600*1000; PredefinedType: COLUMN; Classification: B1010240 Columns - CIP (Uniformat)
Type - Graphics - Coarse Scale Fill Color: 0
Type - Identity Data - Assembly Code: B1010240; Assembly Description: Columns - CIP; Type Name: COLUMNA 5822
Type - Other - Category: Columns; Family Name: COLUMNA 5822
Type - Pset_ColumnCommon - IsExternal: no; LoadBearing: yes; Reference: CC/0(?)
Type - Pset_ProductRequirements - Name: COLUMNA; Category: Columns
Type - Pset_QuantityTakeOff - Reference: CC/0(?)
Type - Pset_ReinforcementBarPitchOfColumn - Reference: CC/0(?)
BaseQuantities - GrossVolume: 1.31141 m3
Pset_ColumnCommon - Slope: 0 rad
Pset_QuantityTakeOff - sets with these values: 2
Constraints - Moves With Grids: yes; Moves With Nearby Elements: yes; Room Bounding: yes
Dimensions - Area: 0.615557 m2; Volume: 1.31141 m3
Other - Family: COLUMNA 5822: COLUMNA 5822; Family and Type: COLUMNA 5822: COLUMNA 5822; Type: COLUMNA 5822: COLUMNA 5822; Type Id: COLUMNA 5822: COLUMNA 5822
Phasing - Phase Created: New Construction

# IfcColumn: COLUMNA, COLUMNA 5844:COLUMNA 5844:204059
In: Default
Type - Description: 600*1000; PredefinedType: COLUMN; Classification: B1010240 Columns - CIP (Uniformat)
Type - Graphics - Coarse Scale Fill Color: 0
Type - Identity Data - Assembly Code: B1010240; Assembly Description: Columns - CIP; Type Name: COLUMNA 5844
Type - Other - Category: Columns; Family Name: COLUMNA 5844
Type - Pset_ColumnCommon - IsExternal: no; LoadBearing: yes; Reference: CC/0(?)
Type - Pset_ProductRequirements - Name: COLUMNA; Category: Columns
Type - Pset_QuantityTakeOff - Reference: CC/0(?)
Type - Pset_ReinforcementBarPitchOfColumn - Reference: CC/0(?)
BaseQuantities - GrossVolume: 1.75044 m3
Pset_ColumnCommon - Slope: 0 rad
Pset_QuantityTakeOff - sets with these values: 2
Constraints - Moves With Grids: yes; Moves With Nearby Elements: yes; Room Bounding: yes
Dimensions - Area: 0.616662 m2; Volume: 1.75044 m3
Other - Family: COLUMNA 5844: COLUMNA 5844; Family and Type: COLUMNA 5844: COLUMNA 5844; Type: COLUMNA 5844: COLUMNA 5844; Type Id: COLUMNA 5844: COLUMNA 5844
Phasing - Phase Created: New Construction

# IfcColumn: COLUMNA, COLUMNA 5866:COLUMNA 5866:204081
In: Default
Type - Description: 600*1000; PredefinedType: COLUMN; Classification: B1010240 Columns - CIP (Uniformat)
Type - Graphics - Coarse Scale Fill Color: 0
Type - Identity Data - Assembly Code: B1010240; Assembly Description: Columns - CIP; Type Name: COLUMNA 5866
Type - Other - Category: Columns; Family Name: COLUMNA 5866
Type - Pset_ColumnCommon - IsExternal: no; LoadBearing: yes; Reference: P/0(?)
Type - Pset_ProductRequirements - Name: COLUMNA; Category: Columns
Type - Pset_QuantityTakeOff - Reference: P/0(?)
Type - Pset_ReinforcementBarPitchOfColumn - Reference: P/0(?)
BaseQuantities - GrossVolume: 1.66701 m3
Pset_ColumnCommon - Slope: 0 rad
Pset_QuantityTakeOff - sets with these values: 2
Constraints - Moves With Grids: yes; Moves With Nearby Elements: yes; Room Bounding: yes
Dimensions - Area: 0.632118 m2; Volume: 1.66701 m3
Other - Family: COLUMNA 5866: COLUMNA 5866; Family and Type: COLUMNA 5866: COLUMNA 5866; Type: COLUMNA 5866: COLUMNA 5866; Type Id: COLUMNA 5866: COLUMNA 5866
Phasing - Phase Created: New Construction

# IfcColumn: D600 (139)
In: Default
Type - PredefinedType: COLUMN
Type - Graphics - Coarse Scale Fill Color: 0
Type - Identity Data - Assembly Code: A1020110; Assembly Description: Piles - CIP; Type Name: D600
Type - Materials and Finishes - Material: CONCRETE/28MPa 117
Type - Other - Category: Structural Columns; Family Name: D600
Type - Structural - Section Shape: 0
Type - Pset_ColumnCommon - IsExternal: no; LoadBearing: yes; Reference: D600
Type - Pset_ProductRequirements - Category: Structural Columns
Type - Pset_QuantityTakeOff - Reference: D600
Type - Pset_ReinforcementBarPitchOfColumn - Reference: D600
Classification: A1020110 Piles - CIP (Uniformat); Material: CONCRETE/28MPa 117
BaseQuantities - GrossVolume: 3.13841 m3
Pset_ColumnCommon - Slope: 0 rad
Pset_QuantityTakeOff - sets with these values: 2
Constraints - Moves With Grids: yes; Column Style: Vertical; Top Level: Level: Default; Base Level: Level: Default; Base Offset: -15300 mm; Top Offset: -4200 mm
Dimensions - Area: 10.7442 m2; Length: 11100 mm; Volume: 3.13841 m3
Materials and Finishes - Structural Material: CONCRETE/28MPa 117
Other - Family: D600: D600; Family and Type: D600: D600; Type: D600: D600; Type Id: D600: D600
Phasing - Phase Created: New Construction
Structural - Enable Analytical Model: yes
Name (D600:D600:...)
212302
212304
212306
212308
212310
212312
212314
212316
212318
212320
212322
212324
212326
212328
212330
212332
212334
212336
212338
212340
212342
212344
212346
212348
212350
212352
212354
212356
212358
212360
212362
212364
212366
212368
212370
212372
212374
212376
212378
212380
212382
212384
212386
212388
212390
212392
212394
212396
212398
212400
212402
212404
212406
212408
212410
212412
212414
212416
212418
212420
212422
212424
212426
212428
212430
212432
212434
212436
212438
212440
212442
212444
212446
212448
212450
212452
212454
212456
212458
212460
212462
212464
212466
212468
212470
212472
212474
212476
212478
212480
212482
212484
212486
212488
212490
212492
212494
212496
212498
212500
212502
212504
212506
212508
212510
212512
212514
212516
212518
212520
212522
212524
212526
212528
212530
212532
212534
212536
212538
212540
212542
212545
212547
212549
212551
212553
212555
212557
212559
212561
212563
212565
212567
212569
212571
212573
212575
212577
212579

# IfcColumn: PILOTE, PILOTE:PILOTE:201082
In: Default
Type - Description: D600; PredefinedType: COLUMN; Classification: A1020110 Piles - CIP (Uniformat)
Type - Graphics - Coarse Scale Fill Color: 0
Type - Identity Data - Assembly Code: A1020110; Assembly Description: Piles - CIP; Type Name: PILOTE
Type - Other - Category: Columns; Family Name: PILOTE
Type - Pset_ColumnCommon - Reference: Hormigón_PI-1/0(?); IsExternal: no; LoadBearing: yes
Type - Pset_ProductRequirements - Name: PILOTE; Category: Columns
Type - Pset_QuantityTakeOff - Reference: Hormigón_PI-1/0(?)
Type - Pset_ReinforcementBarPitchOfColumn - Reference: Hormigón_PI-1/0(?)
Material: CONCRETE/28MPa 117
BaseQuantities - GrossVolume: 3.13841 m3
Pset_ColumnCommon - Slope: 0 rad
Pset_QuantityTakeOff - sets with these values: 2
Constraints - Moves With Grids: yes; Moves With Nearby Elements: yes; Room Bounding: yes
Dimensions - Area: 0.282732 m2; Volume: 3.13841 m3
Other - Family: PILOTE: PILOTE; Family and Type: PILOTE: PILOTE; Type: PILOTE: PILOTE; Type Id: PILOTE: PILOTE
Phasing - Phase Created: New Construction

# IfcColumn: PILOTE, PILOTE 1002:PILOTE 1002:202305
In: Default
Type - Description: D600; PredefinedType: COLUMN; Classification: A1020110 Piles - CIP (Uniformat)
Type - Graphics - Coarse Scale Fill Color: 0
Type - Identity Data - Assembly Code: A1020110; Assembly Description: Piles - CIP; Type Name: PILOTE 1002
Type - Other - Category: Columns; Family Name: PILOTE 1002
Type - Pset_ColumnCommon - Reference: Hormigón_PI-1/0(?); IsExternal: no; LoadBearing: yes
Type - Pset_ProductRequirements - Name: PILOTE; Category: Columns
Type - Pset_QuantityTakeOff - Reference: Hormigón_PI-1/0(?)
Type - Pset_ReinforcementBarPitchOfColumn - Reference: Hormigón_PI-1/0(?)
Material: CONCRETE/28MPa 117
BaseQuantities - GrossVolume: 3.13841 m3
Pset_ColumnCommon - Slope: 0 rad
Pset_QuantityTakeOff - sets with these values: 2
Constraints - Moves With Grids: yes; Moves With Nearby Elements: yes; Room Bounding: yes
Dimensions - Area: 0.282732 m2; Volume: 3.13841 m3
Other - Family: PILOTE 1002: PILOTE 1002; Family and Type: PILOTE 1002: PILOTE 1002; Type: PILOTE 1002: PILOTE 1002; Type Id: PILOTE 1002: PILOTE 1002
Phasing - Phase Created: New Construction

# IfcColumn: PILOTE, PILOTE 1010:PILOTE 1010:202317
In: Default
Type - Description: D600; PredefinedType: COLUMN; Classification: A1020110 Piles - CIP (Uniformat)
Type - Graphics - Coarse Scale Fill Color: 0
Type - Identity Data - Assembly Code: A1020110; Assembly Description: Piles - CIP; Type Name: PILOTE 1010
Type - Other - Category: Columns; Family Name: PILOTE 1010
Type - Pset_ColumnCommon - Reference: Hormigón_PI-1/0(?); IsExternal: no; LoadBearing: yes
Type - Pset_ProductRequirements - Name: PILOTE; Category: Columns
Type - Pset_QuantityTakeOff - Reference: Hormigón_PI-1/0(?)
Type - Pset_ReinforcementBarPitchOfColumn - Reference: Hormigón_PI-1/0(?)
Material: CONCRETE/28MPa 117
BaseQuantities - GrossVolume: 3.13841 m3
Pset_ColumnCommon - Slope: 0 rad
Pset_QuantityTakeOff - sets with these values: 2
Constraints - Moves With Grids: yes; Moves With Nearby Elements: yes; Room Bounding: yes
Dimensions - Area: 0.282732 m2; Volume: 3.13841 m3
Other - Family: PILOTE 1010: PILOTE 1010; Family and Type: PILOTE 1010: PILOTE 1010; Type: PILOTE 1010: PILOTE 1010; Type Id: PILOTE 1010: PILOTE 1010
Phasing - Phase Created: New Construction

# IfcColumn: PILOTE, PILOTE 1018:PILOTE 1018:202329
In: Default
Type - Description: D600; PredefinedType: COLUMN; Classification: A1020110 Piles - CIP (Uniformat)
Type - Graphics - Coarse Scale Fill Color: 0
Type - Identity Data - Assembly Code: A1020110; Assembly Description: Piles - CIP; Type Name: PILOTE 1018
Type - Other - Category: Columns; Family Name: PILOTE 1018
Type - Pset_ColumnCommon - Reference: Hormigón_PI-1/0(?); IsExternal: no; LoadBearing: yes
Type - Pset_ProductRequirements - Name: PILOTE; Category: Columns
Type - Pset_QuantityTakeOff - Reference: Hormigón_PI-1/0(?)
Type - Pset_ReinforcementBarPitchOfColumn - Reference: Hormigón_PI-1/0(?)
Material: CONCRETE/28MPa 117
BaseQuantities - GrossVolume: 3.13841 m3
Pset_ColumnCommon - Slope: 0 rad
Pset_QuantityTakeOff - sets with these values: 2
Constraints - Moves With Grids: yes; Moves With Nearby Elements: yes; Room Bounding: yes
Dimensions - Area: 0.282732 m2; Volume: 3.13841 m3
Other - Family: PILOTE 1018: PILOTE 1018; Family and Type: PILOTE 1018: PILOTE 1018; Type: PILOTE 1018: PILOTE 1018; Type Id: PILOTE 1018: PILOTE 1018
Phasing - Phase Created: New Construction

# IfcColumn: PILOTE, PILOTE 1026:PILOTE 1026:202341
In: Default
Type - Description: D600; PredefinedType: COLUMN; Classification: A1020110 Piles - CIP (Uniformat)
Type - Graphics - Coarse Scale Fill Color: 0
Type - Identity Data - Assembly Code: A1020110; Assembly Description: Piles - CIP; Type Name: PILOTE 1026
Type - Other - Category: Columns; Family Name: PILOTE 1026
Type - Pset_ColumnCommon - Reference: Hormigón_PI-1/0(?); IsExternal: no; LoadBearing: yes
Type - Pset_ProductRequirements - Name: PILOTE; Category: Columns
Type - Pset_QuantityTakeOff - Reference: Hormigón_PI-1/0(?)
Type - Pset_ReinforcementBarPitchOfColumn - Reference: Hormigón_PI-1/0(?)
Material: CONCRETE/28MPa 117
BaseQuantities - GrossVolume: 3.13841 m3
Pset_ColumnCommon - Slope: 0 rad
Pset_QuantityTakeOff - sets with these values: 2
Constraints - Moves With Grids: yes; Moves With Nearby Elements: yes; Room Bounding: yes
Dimensions - Area: 0.282732 m2; Volume: 3.13841 m3
Other - Family: PILOTE 1026: PILOTE 1026; Family and Type: PILOTE 1026: PILOTE 1026; Type: PILOTE 1026: PILOTE 1026; Type Id: PILOTE 1026: PILOTE 1026
Phasing - Phase Created: New Construction

# IfcColumn: PILOTE, PILOTE 1034:PILOTE 1034:202353
In: Default
Type - Description: D600; PredefinedType: COLUMN; Classification: A1020110 Piles - CIP (Uniformat)
Type - Graphics - Coarse Scale Fill Color: 0
Type - Identity Data - Assembly Code: A1020110; Assembly Description: Piles - CIP; Type Name: PILOTE 1034
Type - Other - Category: Columns; Family Name: PILOTE 1034
Type - Pset_ColumnCommon - Reference: Hormigón_PI-1/0(?); IsExternal: no; LoadBearing: yes
Type - Pset_ProductRequirements - Name: PILOTE; Category: Columns
Type - Pset_QuantityTakeOff - Reference: Hormigón_PI-1/0(?)
Type - Pset_ReinforcementBarPitchOfColumn - Reference: Hormigón_PI-1/0(?)
Material: CONCRETE/28MPa 117
BaseQuantities - GrossVolume: 3.13841 m3
Pset_ColumnCommon - Slope: 0 rad
Pset_QuantityTakeOff - sets with these values: 2
Constraints - Moves With Grids: yes; Moves With Nearby Elements: yes; Room Bounding: yes
Dimensions - Area: 0.282732 m2; Volume: 3.13841 m3
Other - Family: PILOTE 1034: PILOTE 1034; Family and Type: PILOTE 1034: PILOTE 1034; Type: PILOTE 1034: PILOTE 1034; Type Id: PILOTE 1034: PILOTE 1034
Phasing - Phase Created: New Construction

# IfcColumn: PILOTE, PILOTE 1042:PILOTE 1042:202365
In: Default
Type - Description: D600; PredefinedType: COLUMN; Classification: A1020110 Piles - CIP (Uniformat)
Type - Graphics - Coarse Scale Fill Color: 0
Type - Identity Data - Assembly Code: A1020110; Assembly Description: Piles - CIP; Type Name: PILOTE 1042
Type - Other - Category: Columns; Family Name: PILOTE 1042
Type - Pset_ColumnCommon - Reference: Hormigón_PI-1/0(?); IsExternal: no; LoadBearing: yes
Type - Pset_ProductRequirements - Name: PILOTE; Category: Columns
Type - Pset_QuantityTakeOff - Reference: Hormigón_PI-1/0(?)
Type - Pset_ReinforcementBarPitchOfColumn - Reference: Hormigón_PI-1/0(?)
Material: CONCRETE/28MPa 117
BaseQuantities - GrossVolume: 3.13841 m3
Pset_ColumnCommon - Slope: 0 rad
Pset_QuantityTakeOff - sets with these values: 2
Constraints - Moves With Grids: yes; Moves With Nearby Elements: yes; Room Bounding: yes
Dimensions - Area: 0.282732 m2; Volume: 3.13841 m3
Other - Family: PILOTE 1042: PILOTE 1042; Family and Type: PILOTE 1042: PILOTE 1042; Type: PILOTE 1042: PILOTE 1042; Type Id: PILOTE 1042: PILOTE 1042
Phasing - Phase Created: New Construction

# IfcColumn: PILOTE, PILOTE 1050:PILOTE 1050:202377
In: Default
Type - Description: D600; PredefinedType: COLUMN; Classification: A1020110 Piles - CIP (Uniformat)
Type - Graphics - Coarse Scale Fill Color: 0
Type - Identity Data - Assembly Code: A1020110; Assembly Description: Piles - CIP; Type Name: PILOTE 1050
Type - Other - Category: Columns; Family Name: PILOTE 1050
Type - Pset_ColumnCommon - Reference: Hormigón_PI-1/0(?); IsExternal: no; LoadBearing: yes
Type - Pset_ProductRequirements - Name: PILOTE; Category: Columns
Type - Pset_QuantityTakeOff - Reference: Hormigón_PI-1/0(?)
Type - Pset_ReinforcementBarPitchOfColumn - Reference: Hormigón_PI-1/0(?)
Material: CONCRETE/28MPa 117
BaseQuantities - GrossVolume: 3.13841 m3
Pset_ColumnCommon - Slope: 0 rad
Pset_QuantityTakeOff - sets with these values: 2
Constraints - Moves With Grids: yes; Moves With Nearby Elements: yes; Room Bounding: yes
Dimensions - Area: 0.282732 m2; Volume: 3.13841 m3
Other - Family: PILOTE 1050: PILOTE 1050; Family and Type: PILOTE 1050: PILOTE 1050; Type: PILOTE 1050: PILOTE 1050; Type Id: PILOTE 1050: PILOTE 1050
Phasing - Phase Created: New Construction

# IfcColumn: PILOTE, PILOTE 1060:PILOTE 1060:202389
In: Default
Type - Description: D600; PredefinedType: COLUMN; Classification: A1020110 Piles - CIP (Uniformat)
Type - Graphics - Coarse Scale Fill Color: 0
Type - Identity Data - Assembly Code: A1020110; Assembly Description: Piles - CIP; Type Name: PILOTE 1060
Type - Other - Category: Columns; Family Name: PILOTE 1060
Type - Pset_ColumnCommon - Reference: Hormigón_PI-1/0(?); IsExternal: no; LoadBearing: yes
Type - Pset_ProductRequirements - Name: PILOTE; Category: Columns
Type - Pset_QuantityTakeOff - Reference: Hormigón_PI-1/0(?)
Type - Pset_ReinforcementBarPitchOfColumn - Reference: Hormigón_PI-1/0(?)
Material: CONCRETE/28MPa 117
BaseQuantities - GrossVolume: 3.13841 m3
Pset_ColumnCommon - Slope: 0 rad
Pset_QuantityTakeOff - sets with these values: 2
Constraints - Moves With Grids: yes; Moves With Nearby Elements: yes; Room Bounding: yes
Dimensions - Area: 0.282732 m2; Volume: 3.13841 m3
Other - Family: PILOTE 1060: PILOTE 1060; Family and Type: PILOTE 1060: PILOTE 1060; Type: PILOTE 1060: PILOTE 1060; Type Id: PILOTE 1060: PILOTE 1060
Phasing - Phase Created: New Construction

# IfcColumn: PILOTE, PILOTE 1070:PILOTE 1070:202401
In: Default
Type - Description: D600; PredefinedType: COLUMN; Classification: A1020110 Piles - CIP (Uniformat)
Type - Graphics - Coarse Scale Fill Color: 0
Type - Identity Data - Assembly Code: A1020110; Assembly Description: Piles - CIP; Type Name: PILOTE 1070
Type - Other - Category: Columns; Family Name: PILOTE 1070
Type - Pset_ColumnCommon - Reference: Hormigón_PI-1/0(?); IsExternal: no; LoadBearing: yes
Type - Pset_ProductRequirements - Name: PILOTE; Category: Columns
Type - Pset_QuantityTakeOff - Reference: Hormigón_PI-1/0(?)
Type - Pset_ReinforcementBarPitchOfColumn - Reference: Hormigón_PI-1/0(?)
Material: CONCRETE/28MPa 117
BaseQuantities - GrossVolume: 3.13841 m3
Pset_ColumnCommon - Slope: 0 rad
Pset_QuantityTakeOff - sets with these values: 2
Constraints - Moves With Grids: yes; Moves With Nearby Elements: yes; Room Bounding: yes
Dimensions - Area: 0.282732 m2; Volume: 3.13841 m3
Other - Family: PILOTE 1070: PILOTE 1070; Family and Type: PILOTE 1070: PILOTE 1070; Type: PILOTE 1070: PILOTE 1070; Type Id: PILOTE 1070: PILOTE 1070
Phasing - Phase Created: New Construction

# IfcColumn: PILOTE, PILOTE 1078:PILOTE 1078:202413
In: Default
Type - Description: D600; PredefinedType: COLUMN; Classification: A1020110 Piles - CIP (Uniformat)
Type - Graphics - Coarse Scale Fill Color: 0
Type - Identity Data - Assembly Code: A1020110; Assembly Description: Piles - CIP; Type Name: PILOTE 1078
Type - Other - Category: Columns; Family Name: PILOTE 1078
Type - Pset_ColumnCommon - Reference: Hormigón_PI-1/0(?); IsExternal: no; LoadBearing: yes
Type - Pset_ProductRequirements - Name: PILOTE; Category: Columns
Type - Pset_QuantityTakeOff - Reference: Hormigón_PI-1/0(?)
Type - Pset_ReinforcementBarPitchOfColumn - Reference: Hormigón_PI-1/0(?)
Material: CONCRETE/28MPa 117
BaseQuantities - GrossVolume: 3.13841 m3
Pset_ColumnCommon - Slope: 0 rad
Pset_QuantityTakeOff - sets with these values: 2
Constraints - Moves With Grids: yes; Moves With Nearby Elements: yes; Room Bounding: yes
Dimensions - Area: 0.282732 m2; Volume: 3.13841 m3
Other - Family: PILOTE 1078: PILOTE 1078; Family and Type: PILOTE 1078: PILOTE 1078; Type: PILOTE 1078: PILOTE 1078; Type Id: PILOTE 1078: PILOTE 1078
Phasing - Phase Created: New Construction

# IfcColumn: PILOTE, PILOTE 1086:PILOTE 1086:202425
In: Default
Type - Description: D600; PredefinedType: COLUMN; Classification: A1020110 Piles - CIP (Uniformat)
Type - Graphics - Coarse Scale Fill Color: 0
Type - Identity Data - Assembly Code: A1020110; Assembly Description: Piles - CIP; Type Name: PILOTE 1086
Type - Other - Category: Columns; Family Name: PILOTE 1086
Type - Pset_ColumnCommon - Reference: Hormigón_PI-1/0(?); IsExternal: no; LoadBearing: yes
Type - Pset_ProductRequirements - Name: PILOTE; Category: Columns
Type - Pset_QuantityTakeOff - Reference: Hormigón_PI-1/0(?)
Type - Pset_ReinforcementBarPitchOfColumn - Reference: Hormigón_PI-1/0(?)
Material: CONCRETE/28MPa 117
BaseQuantities - GrossVolume: 3.13841 m3
Pset_ColumnCommon - Slope: 0 rad
Pset_QuantityTakeOff - sets with these values: 2
Constraints - Moves With Grids: yes; Moves With Nearby Elements: yes; Room Bounding: yes
Dimensions - Area: 0.282732 m2; Volume: 3.13841 m3
Other - Family: PILOTE 1086: PILOTE 1086; Family and Type: PILOTE 1086: PILOTE 1086; Type: PILOTE 1086: PILOTE 1086; Type Id: PILOTE 1086: PILOTE 1086
Phasing - Phase Created: New Construction

# IfcColumn: PILOTE, PILOTE 1094:PILOTE 1094:202437
In: Default
Type - Description: D600; PredefinedType: COLUMN; Classification: A1020110 Piles - CIP (Uniformat)
Type - Graphics - Coarse Scale Fill Color: 0
Type - Identity Data - Assembly Code: A1020110; Assembly Description: Piles - CIP; Type Name: PILOTE 1094
Type - Other - Category: Columns; Family Name: PILOTE 1094
Type - Pset_ColumnCommon - Reference: Hormigón_PI-1/0(?); IsExternal: no; LoadBearing: yes
Type - Pset_ProductRequirements - Name: PILOTE; Category: Columns
Type - Pset_QuantityTakeOff - Reference: Hormigón_PI-1/0(?)
Type - Pset_ReinforcementBarPitchOfColumn - Reference: Hormigón_PI-1/0(?)
Material: CONCRETE/28MPa 117
BaseQuantities - GrossVolume: 3.13841 m3
Pset_ColumnCommon - Slope: 0 rad
Pset_QuantityTakeOff - sets with these values: 2
Constraints - Moves With Grids: yes; Moves With Nearby Elements: yes; Room Bounding: yes
Dimensions - Area: 0.282732 m2; Volume: 3.13841 m3
Other - Family: PILOTE 1094: PILOTE 1094; Family and Type: PILOTE 1094: PILOTE 1094; Type: PILOTE 1094: PILOTE 1094; Type Id: PILOTE 1094: PILOTE 1094
Phasing - Phase Created: New Construction

# IfcColumn: PILOTE, PILOTE 1102:PILOTE 1102:202449
In: Default
Type - Description: D600; PredefinedType: COLUMN; Classification: A1020110 Piles - CIP (Uniformat)
Type - Graphics - Coarse Scale Fill Color: 0
Type - Identity Data - Assembly Code: A1020110; Assembly Description: Piles - CIP; Type Name: PILOTE 1102
Type - Other - Category: Columns; Family Name: PILOTE 1102
Type - Pset_ColumnCommon - Reference: Hormigón_PI-1/0(?); IsExternal: no; LoadBearing: yes
Type - Pset_ProductRequirements - Name: PILOTE; Category: Columns
Type - Pset_QuantityTakeOff - Reference: Hormigón_PI-1/0(?)
Type - Pset_ReinforcementBarPitchOfColumn - Reference: Hormigón_PI-1/0(?)
Material: CONCRETE/28MPa 117
BaseQuantities - GrossVolume: 3.13841 m3
Pset_ColumnCommon - Slope: 0 rad
Pset_QuantityTakeOff - sets with these values: 2
Constraints - Moves With Grids: yes; Moves With Nearby Elements: yes; Room Bounding: yes
Dimensions - Area: 0.282732 m2; Volume: 3.13841 m3
Other - Family: PILOTE 1102: PILOTE 1102; Family and Type: PILOTE 1102: PILOTE 1102; Type: PILOTE 1102: PILOTE 1102; Type Id: PILOTE 1102: PILOTE 1102
Phasing - Phase Created: New Construction

# IfcColumn: PILOTE, PILOTE 1112:PILOTE 1112:202461
In: Default
Type - Description: D600; PredefinedType: COLUMN; Classification: A1020110 Piles - CIP (Uniformat)
Type - Graphics - Coarse Scale Fill Color: 0
Type - Identity Data - Assembly Code: A1020110; Assembly Description: Piles - CIP; Type Name: PILOTE 1112
Type - Other - Category: Columns; Family Name: PILOTE 1112
Type - Pset_ColumnCommon - Reference: Hormigón_PI-1/0(?); IsExternal: no; LoadBearing: yes
Type - Pset_ProductRequirements - Name: PILOTE; Category: Columns
Type - Pset_QuantityTakeOff - Reference: Hormigón_PI-1/0(?)
Type - Pset_ReinforcementBarPitchOfColumn - Reference: Hormigón_PI-1/0(?)
Material: CONCRETE/28MPa 117
BaseQuantities - GrossVolume: 3.13841 m3
Pset_ColumnCommon - Slope: 0 rad
Pset_QuantityTakeOff - sets with these values: 2
Constraints - Moves With Grids: yes; Moves With Nearby Elements: yes; Room Bounding: yes
Dimensions - Area: 0.282732 m2; Volume: 3.13841 m3
Other - Family: PILOTE 1112: PILOTE 1112; Family and Type: PILOTE 1112: PILOTE 1112; Type: PILOTE 1112: PILOTE 1112; Type Id: PILOTE 1112: PILOTE 1112
Phasing - Phase Created: New Construction

# IfcColumn: PILOTE, PILOTE 1120:PILOTE 1120:202473
In: Default
Type - Description: D600; PredefinedType: COLUMN; Classification: A1020110 Piles - CIP (Uniformat)
Type - Graphics - Coarse Scale Fill Color: 0
Type - Identity Data - Assembly Code: A1020110; Assembly Description: Piles - CIP; Type Name: PILOTE 1120
Type - Other - Category: Columns; Family Name: PILOTE 1120
Type - Pset_ColumnCommon - Reference: Hormigón_PI-1/0(?); IsExternal: no; LoadBearing: yes
Type - Pset_ProductRequirements - Name: PILOTE; Category: Columns
Type - Pset_QuantityTakeOff - Reference: Hormigón_PI-1/0(?)
Type - Pset_ReinforcementBarPitchOfColumn - Reference: Hormigón_PI-1/0(?)
Material: CONCRETE/28MPa 117
BaseQuantities - GrossVolume: 3.13841 m3
Pset_ColumnCommon - Slope: 0 rad
Pset_QuantityTakeOff - sets with these values: 2
Constraints - Moves With Grids: yes; Moves With Nearby Elements: yes; Room Bounding: yes
Dimensions - Area: 0.282732 m2; Volume: 3.13841 m3
Other - Family: PILOTE 1120: PILOTE 1120; Family and Type: PILOTE 1120: PILOTE 1120; Type: PILOTE 1120: PILOTE 1120; Type Id: PILOTE 1120: PILOTE 1120
Phasing - Phase Created: New Construction

# IfcColumn: PILOTE, PILOTE 1130:PILOTE 1130:202485
In: Default
Type - Description: D600; PredefinedType: COLUMN; Classification: A1020110 Piles - CIP (Uniformat)
Type - Graphics - Coarse Scale Fill Color: 0
Type - Identity Data - Assembly Code: A1020110; Assembly Description: Piles - CIP; Type Name: PILOTE 1130
Type - Other - Category: Columns; Family Name: PILOTE 1130
Type - Pset_ColumnCommon - Reference: Hormigón_PI-1/0(?); IsExternal: no; LoadBearing: yes
Type - Pset_ProductRequirements - Name: PILOTE; Category: Columns
Type - Pset_QuantityTakeOff - Reference: Hormigón_PI-1/0(?)
Type - Pset_ReinforcementBarPitchOfColumn - Reference: Hormigón_PI-1/0(?)
Material: CONCRETE/28MPa 117
BaseQuantities - GrossVolume: 3.13841 m3
Pset_ColumnCommon - Slope: 0 rad
Pset_QuantityTakeOff - sets with these values: 2
Constraints - Moves With Grids: yes; Moves With Nearby Elements: yes; Room Bounding: yes
Dimensions - Area: 0.282732 m2; Volume: 3.13841 m3
Other - Family: PILOTE 1130: PILOTE 1130; Family and Type: PILOTE 1130: PILOTE 1130; Type: PILOTE 1130: PILOTE 1130; Type Id: PILOTE 1130: PILOTE 1130
Phasing - Phase Created: New Construction

# IfcColumn: PILOTE, PILOTE 1138:PILOTE 1138:202497
In: Default
Type - Description: D600; PredefinedType: COLUMN; Classification: A1020110 Piles - CIP (Uniformat)
Type - Graphics - Coarse Scale Fill Color: 0
Type - Identity Data - Assembly Code: A1020110; Assembly Description: Piles - CIP; Type Name: PILOTE 1138
Type - Other - Category: Columns; Family Name: PILOTE 1138
Type - Pset_ColumnCommon - Reference: Hormigón_PI-1/0(?); IsExternal: no; LoadBearing: yes
Type - Pset_ProductRequirements - Name: PILOTE; Category: Columns
Type - Pset_QuantityTakeOff - Reference: Hormigón_PI-1/0(?)
Type - Pset_ReinforcementBarPitchOfColumn - Reference: Hormigón_PI-1/0(?)
Material: CONCRETE/28MPa 117
BaseQuantities - GrossVolume: 3.13841 m3
Pset_ColumnCommon - Slope: 0 rad
Pset_QuantityTakeOff - sets with these values: 2
Constraints - Moves With Grids: yes; Moves With Nearby Elements: yes; Room Bounding: yes
Dimensions - Area: 0.282732 m2; Volume: 3.13841 m3
Other - Family: PILOTE 1138: PILOTE 1138; Family and Type: PILOTE 1138: PILOTE 1138; Type: PILOTE 1138: PILOTE 1138; Type Id: PILOTE 1138: PILOTE 1138
Phasing - Phase Created: New Construction

# IfcColumn: PILOTE, PILOTE 1146:PILOTE 1146:202509
In: Default
Type - Description: D600; PredefinedType: COLUMN; Classification: A1020110 Piles - CIP (Uniformat)
Type - Graphics - Coarse Scale Fill Color: 0
Type - Identity Data - Assembly Code: A1020110; Assembly Description: Piles - CIP; Type Name: PILOTE 1146
Type - Other - Category: Columns; Family Name: PILOTE 1146
Type - Pset_ColumnCommon - Reference: Hormigón_PI-1/0(?); IsExternal: no; LoadBearing: yes
Type - Pset_ProductRequirements - Name: PILOTE; Category: Columns
Type - Pset_QuantityTakeOff - Reference: Hormigón_PI-1/0(?)
Type - Pset_ReinforcementBarPitchOfColumn - Reference: Hormigón_PI-1/0(?)
Material: CONCRETE/28MPa 117
BaseQuantities - GrossVolume: 3.13841 m3
Pset_ColumnCommon - Slope: 0 rad
Pset_QuantityTakeOff - sets with these values: 2
Constraints - Moves With Grids: yes; Moves With Nearby Elements: yes; Room Bounding: yes
Dimensions - Area: 0.282732 m2; Volume: 3.13841 m3
Other - Family: PILOTE 1146: PILOTE 1146; Family and Type: PILOTE 1146: PILOTE 1146; Type: PILOTE 1146: PILOTE 1146; Type Id: PILOTE 1146: PILOTE 1146
Phasing - Phase Created: New Construction

# IfcColumn: PILOTE, PILOTE 1154:PILOTE 1154:202521
In: Default
Type - Description: D600; PredefinedType: COLUMN; Classification: A1020110 Piles - CIP (Uniformat)
Type - Graphics - Coarse Scale Fill Color: 0
Type - Identity Data - Assembly Code: A1020110; Assembly Description: Piles - CIP; Type Name: PILOTE 1154
Type - Other - Category: Columns; Family Name: PILOTE 1154
Type - Pset_ColumnCommon - Reference: Hormigón_PI-1/0(?); IsExternal: no; LoadBearing: yes
Type - Pset_ProductRequirements - Name: PILOTE; Category: Columns
Type - Pset_QuantityTakeOff - Reference: Hormigón_PI-1/0(?)
Type - Pset_ReinforcementBarPitchOfColumn - Reference: Hormigón_PI-1/0(?)
Material: CONCRETE/28MPa 117
BaseQuantities - GrossVolume: 3.13841 m3
Pset_ColumnCommon - Slope: 0 rad
Pset_QuantityTakeOff - sets with these values: 2
Constraints - Moves With Grids: yes; Moves With Nearby Elements: yes; Room Bounding: yes
Dimensions - Area: 0.282732 m2; Volume: 3.13841 m3
Other - Family: PILOTE 1154: PILOTE 1154; Family and Type: PILOTE 1154: PILOTE 1154; Type: PILOTE 1154: PILOTE 1154; Type Id: PILOTE 1154: PILOTE 1154
Phasing - Phase Created: New Construction

# IfcColumn: PILOTE, PILOTE 1162:PILOTE 1162:202533
In: Default
Type - Description: D600; PredefinedType: COLUMN; Classification: A1020110 Piles - CIP (Uniformat)
Type - Graphics - Coarse Scale Fill Color: 0
Type - Identity Data - Assembly Code: A1020110; Assembly Description: Piles - CIP; Type Name: PILOTE 1162
Type - Other - Category: Columns; Family Name: PILOTE 1162
Type - Pset_ColumnCommon - Reference: Hormigón_PI-1/0(?); IsExternal: no; LoadBearing: yes
Type - Pset_ProductRequirements - Name: PILOTE; Category: Columns
Type - Pset_QuantityTakeOff - Reference: Hormigón_PI-1/0(?)
Type - Pset_ReinforcementBarPitchOfColumn - Reference: Hormigón_PI-1/0(?)
Material: CONCRETE/28MPa 117
BaseQuantities - GrossVolume: 3.13841 m3
Pset_ColumnCommon - Slope: 0 rad
Pset_QuantityTakeOff - sets with these values: 2
Constraints - Moves With Grids: yes; Moves With Nearby Elements: yes; Room Bounding: yes
Dimensions - Area: 0.282732 m2; Volume: 3.13841 m3
Other - Family: PILOTE 1162: PILOTE 1162; Family and Type: PILOTE 1162: PILOTE 1162; Type: PILOTE 1162: PILOTE 1162; Type Id: PILOTE 1162: PILOTE 1162
Phasing - Phase Created: New Construction

# IfcColumn: PILOTE, PILOTE 1170:PILOTE 1170:202545
In: Default
Type - Description: D600; PredefinedType: COLUMN; Classification: A1020110 Piles - CIP (Uniformat)
Type - Graphics - Coarse Scale Fill Color: 0
Type - Identity Data - Assembly Code: A1020110; Assembly Description: Piles - CIP; Type Name: PILOTE 1170
Type - Other - Category: Columns; Family Name: PILOTE 1170
Type - Pset_ColumnCommon - Reference: Hormigón_PI-1/0(?); IsExternal: no; LoadBearing: yes
Type - Pset_ProductRequirements - Name: PILOTE; Category: Columns
Type - Pset_QuantityTakeOff - Reference: Hormigón_PI-1/0(?)
Type - Pset_ReinforcementBarPitchOfColumn - Reference: Hormigón_PI-1/0(?)
Material: CONCRETE/28MPa 117
BaseQuantities - GrossVolume: 3.13841 m3
Pset_ColumnCommon - Slope: 0 rad
Pset_QuantityTakeOff - sets with these values: 2
Constraints - Moves With Grids: yes; Moves With Nearby Elements: yes; Room Bounding: yes
Dimensions - Area: 0.282732 m2; Volume: 3.13841 m3
Other - Family: PILOTE 1170: PILOTE 1170; Family and Type: PILOTE 1170: PILOTE 1170; Type: PILOTE 1170: PILOTE 1170; Type Id: PILOTE 1170: PILOTE 1170
Phasing - Phase Created: New Construction

# IfcColumn: PILOTE, PILOTE 1178:PILOTE 1178:202557
In: Default
Type - Description: D600; PredefinedType: COLUMN; Classification: A1020110 Piles - CIP (Uniformat)
Type - Graphics - Coarse Scale Fill Color: 0
Type - Identity Data - Assembly Code: A1020110; Assembly Description: Piles - CIP; Type Name: PILOTE 1178
Type - Other - Category: Columns; Family Name: PILOTE 1178
Type - Pset_ColumnCommon - Reference: Hormigón_PI-1/0(?); IsExternal: no; LoadBearing: yes
Type - Pset_ProductRequirements - Name: PILOTE; Category: Columns
Type - Pset_QuantityTakeOff - Reference: Hormigón_PI-1/0(?)
Type - Pset_ReinforcementBarPitchOfColumn - Reference: Hormigón_PI-1/0(?)
Material: CONCRETE/28MPa 117
BaseQuantities - GrossVolume: 3.13841 m3
Pset_ColumnCommon - Slope: 0 rad
Pset_QuantityTakeOff - sets with these values: 2
Constraints - Moves With Grids: yes; Moves With Nearby Elements: yes; Room Bounding: yes
Dimensions - Area: 0.282732 m2; Volume: 3.13841 m3
Other - Family: PILOTE 1178: PILOTE 1178; Family and Type: PILOTE 1178: PILOTE 1178; Type: PILOTE 1178: PILOTE 1178; Type Id: PILOTE 1178: PILOTE 1178
Phasing - Phase Created: New Construction

# IfcColumn: PILOTE, PILOTE 1186:PILOTE 1186:202569
In: Default
Type - Description: D600; PredefinedType: COLUMN; Classification: A1020110 Piles - CIP (Uniformat)
Type - Graphics - Coarse Scale Fill Color: 0
Type - Identity Data - Assembly Code: A1020110; Assembly Description: Piles - CIP; Type Name: PILOTE 1186
Type - Other - Category: Columns; Family Name: PILOTE 1186
Type - Pset_ColumnCommon - Reference: Hormigón_PI-1/0(?); IsExternal: no; LoadBearing: yes
Type - Pset_ProductRequirements - Name: PILOTE; Category: Columns
Type - Pset_QuantityTakeOff - Reference: Hormigón_PI-1/0(?)
Type - Pset_ReinforcementBarPitchOfColumn - Reference: Hormigón_PI-1/0(?)
Material: CONCRETE/28MPa 117
BaseQuantities - GrossVolume: 3.13841 m3
Pset_ColumnCommon - Slope: 0 rad
Pset_QuantityTakeOff - sets with these values: 2
Constraints - Moves With Grids: yes; Moves With Nearby Elements: yes; Room Bounding: yes
Dimensions - Area: 0.282732 m2; Volume: 3.13841 m3
Other - Family: PILOTE 1186: PILOTE 1186; Family and Type: PILOTE 1186: PILOTE 1186; Type: PILOTE 1186: PILOTE 1186; Type Id: PILOTE 1186: PILOTE 1186
Phasing - Phase Created: New Construction

# IfcColumn: PILOTE, PILOTE 1194:PILOTE 1194:202581
In: Default
Type - Description: D600; PredefinedType: COLUMN; Classification: A1020110 Piles - CIP (Uniformat)
Type - Graphics - Coarse Scale Fill Color: 0
Type - Identity Data - Assembly Code: A1020110; Assembly Description: Piles - CIP; Type Name: PILOTE 1194
Type - Other - Category: Columns; Family Name: PILOTE 1194
Type - Pset_ColumnCommon - Reference: Hormigón_PI-1/0(?); IsExternal: no; LoadBearing: yes
Type - Pset_ProductRequirements - Name: PILOTE; Category: Columns
Type - Pset_QuantityTakeOff - Reference: Hormigón_PI-1/0(?)
Type - Pset_ReinforcementBarPitchOfColumn - Reference: Hormigón_PI-1/0(?)
Material: CONCRETE/28MPa 117
BaseQuantities - GrossVolume: 3.13841 m3
Pset_ColumnCommon - Slope: 0 rad
Pset_QuantityTakeOff - sets with these values: 2
Constraints - Moves With Grids: yes; Moves With Nearby Elements: yes; Room Bounding: yes
Dimensions - Area: 0.282732 m2; Volume: 3.13841 m3
Other - Family: PILOTE 1194: PILOTE 1194; Family and Type: PILOTE 1194: PILOTE 1194; Type: PILOTE 1194: PILOTE 1194; Type Id: PILOTE 1194: PILOTE 1194
Phasing - Phase Created: New Construction

# IfcColumn: PILOTE, PILOTE 1202:PILOTE 1202:202593
In: Default
Type - Description: D600; PredefinedType: COLUMN; Classification: A1020110 Piles - CIP (Uniformat)
Type - Graphics - Coarse Scale Fill Color: 0
Type - Identity Data - Assembly Code: A1020110; Assembly Description: Piles - CIP; Type Name: PILOTE 1202
Type - Other - Category: Columns; Family Name: PILOTE 1202
Type - Pset_ColumnCommon - Reference: Hormigón_PI-1/0(?); IsExternal: no; LoadBearing: yes
Type - Pset_ProductRequirements - Name: PILOTE; Category: Columns
Type - Pset_QuantityTakeOff - Reference: Hormigón_PI-1/0(?)
Type - Pset_ReinforcementBarPitchOfColumn - Reference: Hormigón_PI-1/0(?)
Material: CONCRETE/28MPa 117
BaseQuantities - GrossVolume: 3.13841 m3
Pset_ColumnCommon - Slope: 0 rad
Pset_QuantityTakeOff - sets with these values: 2
Constraints - Moves With Grids: yes; Moves With Nearby Elements: yes; Room Bounding: yes
Dimensions - Area: 0.282732 m2; Volume: 3.13841 m3
Other - Family: PILOTE 1202: PILOTE 1202; Family and Type: PILOTE 1202: PILOTE 1202; Type: PILOTE 1202: PILOTE 1202; Type Id: PILOTE 1202: PILOTE 1202
Phasing - Phase Created: New Construction

# IfcColumn: PILOTE, PILOTE 1210:PILOTE 1210:202605
In: Default
Type - Description: D600; PredefinedType: COLUMN; Classification: A1020110 Piles - CIP (Uniformat)
Type - Graphics - Coarse Scale Fill Color: 0
Type - Identity Data - Assembly Code: A1020110; Assembly Description: Piles - CIP; Type Name: PILOTE 1210
Type - Other - Category: Columns; Family Name: PILOTE 1210
Type - Pset_ColumnCommon - Reference: Hormigón_PI-1/0(?); IsExternal: no; LoadBearing: yes
Type - Pset_ProductRequirements - Name: PILOTE; Category: Columns
Type - Pset_QuantityTakeOff - Reference: Hormigón_PI-1/0(?)
Type - Pset_ReinforcementBarPitchOfColumn - Reference: Hormigón_PI-1/0(?)
Material: CONCRETE/28MPa 117
BaseQuantities - GrossVolume: 3.13841 m3
Pset_ColumnCommon - Slope: 0 rad
Pset_QuantityTakeOff - sets with these values: 2
Constraints - Moves With Grids: yes; Moves With Nearby Elements: yes; Room Bounding: yes
Dimensions - Area: 0.282732 m2; Volume: 3.13841 m3
Other - Family: PILOTE 1210: PILOTE 1210; Family and Type: PILOTE 1210: PILOTE 1210; Type: PILOTE 1210: PILOTE 1210; Type Id: PILOTE 1210: PILOTE 1210
Phasing - Phase Created: New Construction

# IfcColumn: PILOTE, PILOTE 1218:PILOTE 1218:202617
In: Default
Type - Description: D600; PredefinedType: COLUMN; Classification: A1020110 Piles - CIP (Uniformat)
Type - Graphics - Coarse Scale Fill Color: 0
Type - Identity Data - Assembly Code: A1020110; Assembly Description: Piles - CIP; Type Name: PILOTE 1218
Type - Other - Category: Columns; Family Name: PILOTE 1218
Type - Pset_ColumnCommon - Reference: Hormigón_PI-1/0(?); IsExternal: no; LoadBearing: yes
Type - Pset_ProductRequirements - Name: PILOTE; Category: Columns
Type - Pset_QuantityTakeOff - Reference: Hormigón_PI-1/0(?)
Type - Pset_ReinforcementBarPitchOfColumn - Reference: Hormigón_PI-1/0(?)
Material: CONCRETE/28MPa 117
BaseQuantities - GrossVolume: 3.13841 m3
Pset_ColumnCommon - Slope: 0 rad
Pset_QuantityTakeOff - sets with these values: 2
Constraints - Moves With Grids: yes; Moves With Nearby Elements: yes; Room Bounding: yes
Dimensions - Area: 0.282732 m2; Volume: 3.13841 m3
Other - Family: PILOTE 1218: PILOTE 1218; Family and Type: PILOTE 1218: PILOTE 1218; Type: PILOTE 1218: PILOTE 1218; Type Id: PILOTE 1218: PILOTE 1218
Phasing - Phase Created: New Construction

# IfcColumn: PILOTE, PILOTE 1226:PILOTE 1226:202629
In: Default
Type - Description: D600; PredefinedType: COLUMN; Classification: A1020110 Piles - CIP (Uniformat)
Type - Graphics - Coarse Scale Fill Color: 0
Type - Identity Data - Assembly Code: A1020110; Assembly Description: Piles - CIP; Type Name: PILOTE 1226
Type - Other - Category: Columns; Family Name: PILOTE 1226
Type - Pset_ColumnCommon - Reference: Hormigón_PI-1/0(?); IsExternal: no; LoadBearing: yes
Type - Pset_ProductRequirements - Name: PILOTE; Category: Columns
Type - Pset_QuantityTakeOff - Reference: Hormigón_PI-1/0(?)
Type - Pset_ReinforcementBarPitchOfColumn - Reference: Hormigón_PI-1/0(?)
Material: CONCRETE/28MPa 117
BaseQuantities - GrossVolume: 3.13841 m3
Pset_ColumnCommon - Slope: 0 rad
Pset_QuantityTakeOff - sets with these values: 2
Constraints - Moves With Grids: yes; Moves With Nearby Elements: yes; Room Bounding: yes
Dimensions - Area: 0.282732 m2; Volume: 3.13841 m3
Other - Family: PILOTE 1226: PILOTE 1226; Family and Type: PILOTE 1226: PILOTE 1226; Type: PILOTE 1226: PILOTE 1226; Type Id: PILOTE 1226: PILOTE 1226
Phasing - Phase Created: New Construction

# IfcColumn: PILOTE, PILOTE 1234:PILOTE 1234:202641
In: Default
Type - Description: D600; PredefinedType: COLUMN; Classification: A1020110 Piles - CIP (Uniformat)
Type - Graphics - Coarse Scale Fill Color: 0
Type - Identity Data - Assembly Code: A1020110; Assembly Description: Piles - CIP; Type Name: PILOTE 1234
Type - Other - Category: Columns; Family Name: PILOTE 1234
Type - Pset_ColumnCommon - Reference: Hormigón_PI-1/0(?); IsExternal: no; LoadBearing: yes
Type - Pset_ProductRequirements - Name: PILOTE; Category: Columns
Type - Pset_QuantityTakeOff - Reference: Hormigón_PI-1/0(?)
Type - Pset_ReinforcementBarPitchOfColumn - Reference: Hormigón_PI-1/0(?)
Material: CONCRETE/28MPa 117
BaseQuantities - GrossVolume: 3.13841 m3
Pset_ColumnCommon - Slope: 0 rad
Pset_QuantityTakeOff - sets with these values: 2
Constraints - Moves With Grids: yes; Moves With Nearby Elements: yes; Room Bounding: yes
Dimensions - Area: 0.282732 m2; Volume: 3.13841 m3
Other - Family: PILOTE 1234: PILOTE 1234; Family and Type: PILOTE 1234: PILOTE 1234; Type: PILOTE 1234: PILOTE 1234; Type Id: PILOTE 1234: PILOTE 1234
Phasing - Phase Created: New Construction

# IfcColumn: PILOTE, PILOTE 1242:PILOTE 1242:202653
In: Default
Type - Description: D600; PredefinedType: COLUMN; Classification: A1020110 Piles - CIP (Uniformat)
Type - Graphics - Coarse Scale Fill Color: 0
Type - Identity Data - Assembly Code: A1020110; Assembly Description: Piles - CIP; Type Name: PILOTE 1242
Type - Other - Category: Columns; Family Name: PILOTE 1242
Type - Pset_ColumnCommon - Reference: Hormigón_PI-1/0(?); IsExternal: no; LoadBearing: yes
Type - Pset_ProductRequirements - Name: PILOTE; Category: Columns
Type - Pset_QuantityTakeOff - Reference: Hormigón_PI-1/0(?)
Type - Pset_ReinforcementBarPitchOfColumn - Reference: Hormigón_PI-1/0(?)
Material: CONCRETE/28MPa 117
BaseQuantities - GrossVolume: 3.13841 m3
Pset_ColumnCommon - Slope: 0 rad
Pset_QuantityTakeOff - sets with these values: 2
Constraints - Moves With Grids: yes; Moves With Nearby Elements: yes; Room Bounding: yes
Dimensions - Area: 0.282732 m2; Volume: 3.13841 m3
Other - Family: PILOTE 1242: PILOTE 1242; Family and Type: PILOTE 1242: PILOTE 1242; Type: PILOTE 1242: PILOTE 1242; Type Id: PILOTE 1242: PILOTE 1242
Phasing - Phase Created: New Construction

# IfcColumn: PILOTE, PILOTE 1250:PILOTE 1250:202665
In: Default
Type - Description: D600; PredefinedType: COLUMN; Classification: A1020110 Piles - CIP (Uniformat)
Type - Graphics - Coarse Scale Fill Color: 0
Type - Identity Data - Assembly Code: A1020110; Assembly Description: Piles - CIP; Type Name: PILOTE 1250
Type - Other - Category: Columns; Family Name: PILOTE 1250
Type - Pset_ColumnCommon - Reference: Hormigón_PI-1/0(?); IsExternal: no; LoadBearing: yes
Type - Pset_ProductRequirements - Name: PILOTE; Category: Columns
Type - Pset_QuantityTakeOff - Reference: Hormigón_PI-1/0(?)
Type - Pset_ReinforcementBarPitchOfColumn - Reference: Hormigón_PI-1/0(?)
Material: CONCRETE/28MPa 117
BaseQuantities - GrossVolume: 3.13841 m3
Pset_ColumnCommon - Slope: 0 rad
Pset_QuantityTakeOff - sets with these values: 2
Constraints - Moves With Grids: yes; Moves With Nearby Elements: yes; Room Bounding: yes
Dimensions - Area: 0.282732 m2; Volume: 3.13841 m3
Other - Family: PILOTE 1250: PILOTE 1250; Family and Type: PILOTE 1250: PILOTE 1250; Type: PILOTE 1250: PILOTE 1250; Type Id: PILOTE 1250: PILOTE 1250
Phasing - Phase Created: New Construction

# IfcColumn: PILOTE, PILOTE 1258:PILOTE 1258:202677
In: Default
Type - Description: D600; PredefinedType: COLUMN; Classification: A1020110 Piles - CIP (Uniformat)
Type - Graphics - Coarse Scale Fill Color: 0
Type - Identity Data - Assembly Code: A1020110; Assembly Description: Piles - CIP; Type Name: PILOTE 1258
Type - Other - Category: Columns; Family Name: PILOTE 1258
Type - Pset_ColumnCommon - Reference: Hormigón_PI-1/0(?); IsExternal: no; LoadBearing: yes
Type - Pset_ProductRequirements - Name: PILOTE; Category: Columns
Type - Pset_QuantityTakeOff - Reference: Hormigón_PI-1/0(?)
Type - Pset_ReinforcementBarPitchOfColumn - Reference: Hormigón_PI-1/0(?)
Material: CONCRETE/28MPa 117
BaseQuantities - GrossVolume: 3.13841 m3
Pset_ColumnCommon - Slope: 0 rad
Pset_QuantityTakeOff - sets with these values: 2
Constraints - Moves With Grids: yes; Moves With Nearby Elements: yes; Room Bounding: yes
Dimensions - Area: 0.282732 m2; Volume: 3.13841 m3
Other - Family: PILOTE 1258: PILOTE 1258; Family and Type: PILOTE 1258: PILOTE 1258; Type: PILOTE 1258: PILOTE 1258; Type Id: PILOTE 1258: PILOTE 1258
Phasing - Phase Created: New Construction

# IfcColumn: PILOTE, PILOTE 1266:PILOTE 1266:202689
In: Default
Type - Description: D600; PredefinedType: COLUMN; Classification: A1020110 Piles - CIP (Uniformat)
Type - Graphics - Coarse Scale Fill Color: 0
Type - Identity Data - Assembly Code: A1020110; Assembly Description: Piles - CIP; Type Name: PILOTE 1266
Type - Other - Category: Columns; Family Name: PILOTE 1266
Type - Pset_ColumnCommon - Reference: Hormigón_PI-1/0(?); IsExternal: no; LoadBearing: yes
Type - Pset_ProductRequirements - Name: PILOTE; Category: Columns
Type - Pset_QuantityTakeOff - Reference: Hormigón_PI-1/0(?)
Type - Pset_ReinforcementBarPitchOfColumn - Reference: Hormigón_PI-1/0(?)
Material: CONCRETE/28MPa 117
BaseQuantities - GrossVolume: 3.13841 m3
Pset_ColumnCommon - Slope: 0 rad
Pset_QuantityTakeOff - sets with these values: 2
Constraints - Moves With Grids: yes; Moves With Nearby Elements: yes; Room Bounding: yes
Dimensions - Area: 0.282732 m2; Volume: 3.13841 m3
Other - Family: PILOTE 1266: PILOTE 1266; Family and Type: PILOTE 1266: PILOTE 1266; Type: PILOTE 1266: PILOTE 1266; Type Id: PILOTE 1266: PILOTE 1266
Phasing - Phase Created: New Construction

# IfcColumn: PILOTE, PILOTE 1274:PILOTE 1274:202701
In: Default
Type - Description: D600; PredefinedType: COLUMN; Classification: A1020110 Piles - CIP (Uniformat)
Type - Graphics - Coarse Scale Fill Color: 0
Type - Identity Data - Assembly Code: A1020110; Assembly Description: Piles - CIP; Type Name: PILOTE 1274
Type - Other - Category: Columns; Family Name: PILOTE 1274
Type - Pset_ColumnCommon - Reference: Hormigón_PI-1/0(?); IsExternal: no; LoadBearing: yes
Type - Pset_ProductRequirements - Name: PILOTE; Category: Columns
Type - Pset_QuantityTakeOff - Reference: Hormigón_PI-1/0(?)
Type - Pset_ReinforcementBarPitchOfColumn - Reference: Hormigón_PI-1/0(?)
Material: CONCRETE/28MPa 117
BaseQuantities - GrossVolume: 3.13841 m3
Pset_ColumnCommon - Slope: 0 rad
Pset_QuantityTakeOff - sets with these values: 2
Constraints - Moves With Grids: yes; Moves With Nearby Elements: yes; Room Bounding: yes
Dimensions - Area: 0.282732 m2; Volume: 3.13841 m3
Other - Family: PILOTE 1274: PILOTE 1274; Family and Type: PILOTE 1274: PILOTE 1274; Type: PILOTE 1274: PILOTE 1274; Type Id: PILOTE 1274: PILOTE 1274
Phasing - Phase Created: New Construction

# IfcColumn: PILOTE, PILOTE 1282:PILOTE 1282:202713
In: Default
Type - Description: D600; PredefinedType: COLUMN; Classification: A1020110 Piles - CIP (Uniformat)
Type - Graphics - Coarse Scale Fill Color: 0
Type - Identity Data - Assembly Code: A1020110; Assembly Description: Piles - CIP; Type Name: PILOTE 1282
Type - Other - Category: Columns; Family Name: PILOTE 1282
Type - Pset_ColumnCommon - Reference: Hormigón_PI-1/0(?); IsExternal: no; LoadBearing: yes
Type - Pset_ProductRequirements - Name: PILOTE; Category: Columns
Type - Pset_QuantityTakeOff - Reference: Hormigón_PI-1/0(?)
Type - Pset_ReinforcementBarPitchOfColumn - Reference: Hormigón_PI-1/0(?)
Material: CONCRETE/28MPa 117
BaseQuantities - GrossVolume: 3.13841 m3
Pset_ColumnCommon - Slope: 0 rad
Pset_QuantityTakeOff - sets with these values: 2
Constraints - Moves With Grids: yes; Moves With Nearby Elements: yes; Room Bounding: yes
Dimensions - Area: 0.282732 m2; Volume: 3.13841 m3
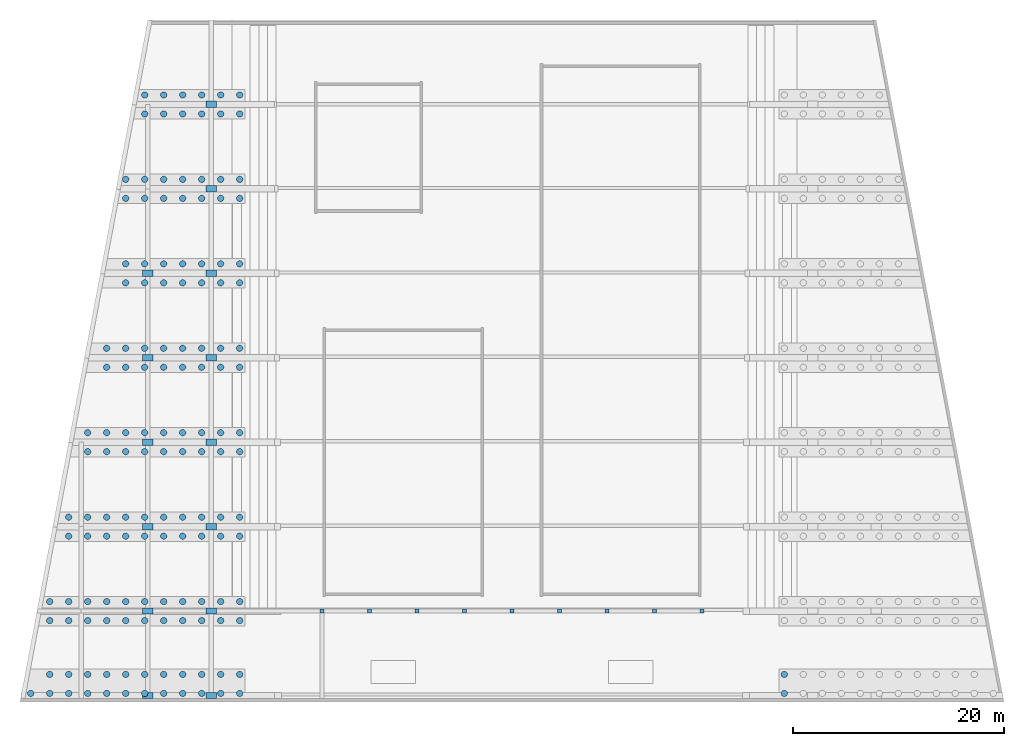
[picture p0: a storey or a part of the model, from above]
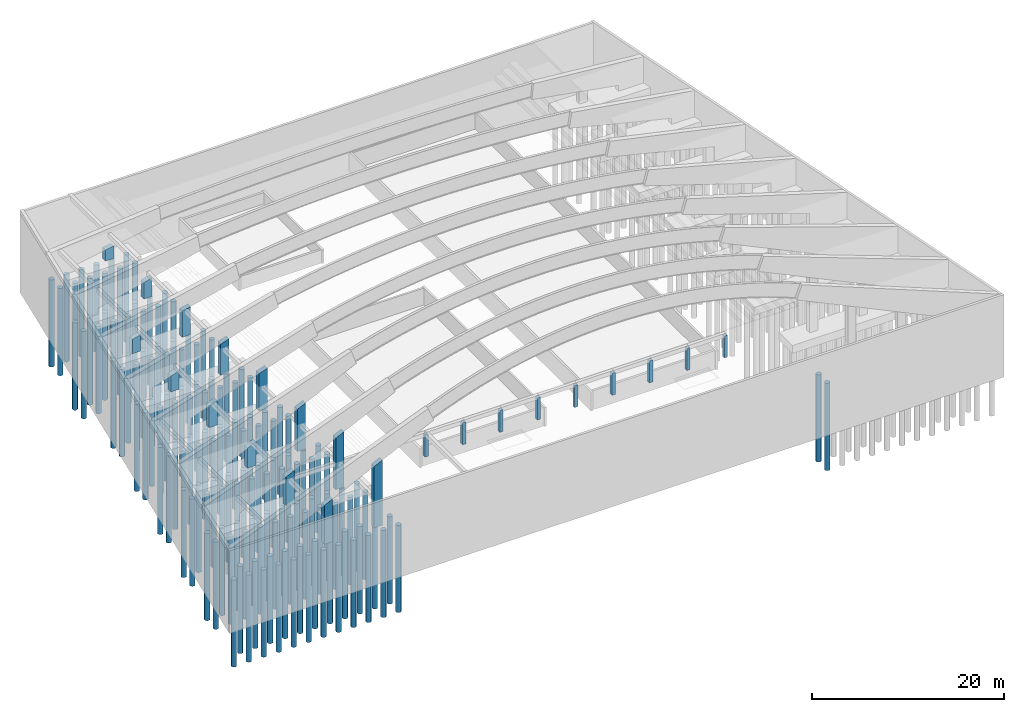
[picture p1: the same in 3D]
Properties of the parts of a building model (IFC2X3), part 3 of 5

# IfcColumn: PILOTE, PILOTE 1282:PILOTE 1282:202713
Other - Family: PILOTE 1282: PILOTE 1282; Family and Type: PILOTE 1282: PILOTE 1282; Type: PILOTE 1282: PILOTE 1282; Type Id: PILOTE 1282: PILOTE 1282
Phasing - Phase Created: New Construction

# IfcColumn: PILOTE, PILOTE 1290:PILOTE 1290:202725
In: Default
Type - Description: D600; PredefinedType: COLUMN; Classification: A1020110 Piles - CIP (Uniformat)
Type - Graphics - Coarse Scale Fill Color: 0
Type - Identity Data - Assembly Code: A1020110; Assembly Description: Piles - CIP; Type Name: PILOTE 1290
Type - Other - Category: Columns; Family Name: PILOTE 1290
Type - Pset_ColumnCommon - Reference: Hormigón_PI-1/0(?); IsExternal: no; LoadBearing: yes
Type - Pset_ProductRequirements - Name: PILOTE; Category: Columns
Type - Pset_QuantityTakeOff - Reference: Hormigón_PI-1/0(?)
Type - Pset_ReinforcementBarPitchOfColumn - Reference: Hormigón_PI-1/0(?)
Material: CONCRETE/28MPa 117
BaseQuantities - GrossVolume: 3.13841 m3
Pset_ColumnCommon - Slope: 0 rad
Pset_QuantityTakeOff - sets with these values: 2
Constraints - Moves With Grids: yes; Moves With Nearby Elements: yes; Room Bounding: yes
Dimensions - Area: 0.282732 m2; Volume: 3.13841 m3
Other - Family: PILOTE 1290: PILOTE 1290; Family and Type: PILOTE 1290: PILOTE 1290; Type: PILOTE 1290: PILOTE 1290; Type Id: PILOTE 1290: PILOTE 1290
Phasing - Phase Created: New Construction

# IfcColumn: PILOTE, PILOTE 1298:PILOTE 1298:202737
In: Default
Type - Description: D600; PredefinedType: COLUMN; Classification: A1020110 Piles - CIP (Uniformat)
Type - Graphics - Coarse Scale Fill Color: 0
Type - Identity Data - Assembly Code: A1020110; Assembly Description: Piles - CIP; Type Name: PILOTE 1298
Type - Other - Category: Columns; Family Name: PILOTE 1298
Type - Pset_ColumnCommon - Reference: Hormigón_PI-1/0(?); IsExternal: no; LoadBearing: yes
Type - Pset_ProductRequirements - Name: PILOTE; Category: Columns
Type - Pset_QuantityTakeOff - Reference: Hormigón_PI-1/0(?)
Type - Pset_ReinforcementBarPitchOfColumn - Reference: Hormigón_PI-1/0(?)
Material: CONCRETE/28MPa 117
BaseQuantities - GrossVolume: 3.13841 m3
Pset_ColumnCommon - Slope: 0 rad
Pset_QuantityTakeOff - sets with these values: 2
Constraints - Moves With Grids: yes; Moves With Nearby Elements: yes; Room Bounding: yes
Dimensions - Area: 0.282732 m2; Volume: 3.13841 m3
Other - Family: PILOTE 1298: PILOTE 1298; Family and Type: PILOTE 1298: PILOTE 1298; Type: PILOTE 1298: PILOTE 1298; Type Id: PILOTE 1298: PILOTE 1298
Phasing - Phase Created: New Construction

# IfcColumn: PILOTE, PILOTE 1306:PILOTE 1306:202749
In: Default
Type - Description: D600; PredefinedType: COLUMN; Classification: A1020110 Piles - CIP (Uniformat)
Type - Graphics - Coarse Scale Fill Color: 0
Type - Identity Data - Assembly Code: A1020110; Assembly Description: Piles - CIP; Type Name: PILOTE 1306
Type - Other - Category: Columns; Family Name: PILOTE 1306
Type - Pset_ColumnCommon - Reference: Hormigón_PI-1/0(?); IsExternal: no; LoadBearing: yes
Type - Pset_ProductRequirements - Name: PILOTE; Category: Columns
Type - Pset_QuantityTakeOff - Reference: Hormigón_PI-1/0(?)
Type - Pset_ReinforcementBarPitchOfColumn - Reference: Hormigón_PI-1/0(?)
Material: CONCRETE/28MPa 117
BaseQuantities - GrossVolume: 3.13841 m3
Pset_ColumnCommon - Slope: 0 rad
Pset_QuantityTakeOff - sets with these values: 2
Constraints - Moves With Grids: yes; Moves With Nearby Elements: yes; Room Bounding: yes
Dimensions - Area: 0.282732 m2; Volume: 3.13841 m3
Other - Family: PILOTE 1306: PILOTE 1306; Family and Type: PILOTE 1306: PILOTE 1306; Type: PILOTE 1306: PILOTE 1306; Type Id: PILOTE 1306: PILOTE 1306
Phasing - Phase Created: New Construction

# IfcColumn: PILOTE, PILOTE 1314:PILOTE 1314:202761
In: Default
Type - Description: D600; PredefinedType: COLUMN; Classification: A1020110 Piles - CIP (Uniformat)
Type - Graphics - Coarse Scale Fill Color: 0
Type - Identity Data - Assembly Code: A1020110; Assembly Description: Piles - CIP; Type Name: PILOTE 1314
Type - Other - Category: Columns; Family Name: PILOTE 1314
Type - Pset_ColumnCommon - Reference: Hormigón_PI-1/0(?); IsExternal: no; LoadBearing: yes
Type - Pset_ProductRequirements - Name: PILOTE; Category: Columns
Type - Pset_QuantityTakeOff - Reference: Hormigón_PI-1/0(?)
Type - Pset_ReinforcementBarPitchOfColumn - Reference: Hormigón_PI-1/0(?)
Material: CONCRETE/28MPa 117
BaseQuantities - GrossVolume: 3.13841 m3
Pset_ColumnCommon - Slope: 0 rad
Pset_QuantityTakeOff - sets with these values: 2
Constraints - Moves With Grids: yes; Moves With Nearby Elements: yes; Room Bounding: yes
Dimensions - Area: 0.282732 m2; Volume: 3.13841 m3
Other - Family: PILOTE 1314: PILOTE 1314; Family and Type: PILOTE 1314: PILOTE 1314; Type: PILOTE 1314: PILOTE 1314; Type Id: PILOTE 1314: PILOTE 1314
Phasing - Phase Created: New Construction

# IfcColumn: PILOTE, PILOTE 160:PILOTE 160:201117
In: Default
Type - Description: D600; PredefinedType: COLUMN; Classification: A1020110 Piles - CIP (Uniformat)
Type - Graphics - Coarse Scale Fill Color: 0
Type - Identity Data - Assembly Code: A1020110; Assembly Description: Piles - CIP; Type Name: PILOTE 160
Type - Other - Category: Columns; Family Name: PILOTE 160
Type - Pset_ColumnCommon - Reference: Hormigón_PI-1/0(?); IsExternal: no; LoadBearing: yes
Type - Pset_ProductRequirements - Name: PILOTE; Category: Columns
Type - Pset_QuantityTakeOff - Reference: Hormigón_PI-1/0(?)
Type - Pset_ReinforcementBarPitchOfColumn - Reference: Hormigón_PI-1/0(?)
Material: CONCRETE/28MPa 117
BaseQuantities - GrossVolume: 3.13841 m3
Pset_ColumnCommon - Slope: 0 rad
Pset_QuantityTakeOff - sets with these values: 2
Constraints - Moves With Grids: yes; Moves With Nearby Elements: yes; Room Bounding: yes
Dimensions - Area: 0.282732 m2; Volume: 3.13841 m3
Other - Family: PILOTE 160: PILOTE 160; Family and Type: PILOTE 160: PILOTE 160; Type: PILOTE 160: PILOTE 160; Type Id: PILOTE 160: PILOTE 160
Phasing - Phase Created: New Construction

# IfcColumn: PILOTE, PILOTE 168:PILOTE 168:201129
In: Default
Type - Description: D600; PredefinedType: COLUMN; Classification: A1020110 Piles - CIP (Uniformat)
Type - Graphics - Coarse Scale Fill Color: 0
Type - Identity Data - Assembly Code: A1020110; Assembly Description: Piles - CIP; Type Name: PILOTE 168
Type - Other - Category: Columns; Family Name: PILOTE 168
Type - Pset_ColumnCommon - Reference: Hormigón_PI-1/0(?); IsExternal: no; LoadBearing: yes
Type - Pset_ProductRequirements - Name: PILOTE; Category: Columns
Type - Pset_QuantityTakeOff - Reference: Hormigón_PI-1/0(?)
Type - Pset_ReinforcementBarPitchOfColumn - Reference: Hormigón_PI-1/0(?)
Material: CONCRETE/28MPa 117
BaseQuantities - GrossVolume: 3.13841 m3
Pset_ColumnCommon - Slope: 0 rad
Pset_QuantityTakeOff - sets with these values: 2
Constraints - Moves With Grids: yes; Moves With Nearby Elements: yes; Room Bounding: yes
Dimensions - Area: 0.282732 m2; Volume: 3.13841 m3
Other - Family: PILOTE 168: PILOTE 168; Family and Type: PILOTE 168: PILOTE 168; Type: PILOTE 168: PILOTE 168; Type Id: PILOTE 168: PILOTE 168
Phasing - Phase Created: New Construction

# IfcColumn: PILOTE, PILOTE 176:PILOTE 176:201141
In: Default
Type - Description: D600; PredefinedType: COLUMN; Classification: A1020110 Piles - CIP (Uniformat)
Type - Graphics - Coarse Scale Fill Color: 0
Type - Identity Data - Assembly Code: A1020110; Assembly Description: Piles - CIP; Type Name: PILOTE 176
Type - Other - Category: Columns; Family Name: PILOTE 176
Type - Pset_ColumnCommon - Reference: Hormigón_PI-1/0(?); IsExternal: no; LoadBearing: yes
Type - Pset_ProductRequirements - Name: PILOTE; Category: Columns
Type - Pset_QuantityTakeOff - Reference: Hormigón_PI-1/0(?)
Type - Pset_ReinforcementBarPitchOfColumn - Reference: Hormigón_PI-1/0(?)
Material: CONCRETE/28MPa 117
BaseQuantities - GrossVolume: 3.13841 m3
Pset_ColumnCommon - Slope: 0 rad
Pset_QuantityTakeOff - sets with these values: 2
Constraints - Moves With Grids: yes; Moves With Nearby Elements: yes; Room Bounding: yes
Dimensions - Area: 0.282732 m2; Volume: 3.13841 m3
Other - Family: PILOTE 176: PILOTE 176; Family and Type: PILOTE 176: PILOTE 176; Type: PILOTE 176: PILOTE 176; Type Id: PILOTE 176: PILOTE 176
Phasing - Phase Created: New Construction

# IfcColumn: PILOTE, PILOTE 184:PILOTE 184:201153
In: Default
Type - Description: D600; PredefinedType: COLUMN; Classification: A1020110 Piles - CIP (Uniformat)
Type - Graphics - Coarse Scale Fill Color: 0
Type - Identity Data - Assembly Code: A1020110; Assembly Description: Piles - CIP; Type Name: PILOTE 184
Type - Other - Category: Columns; Family Name: PILOTE 184
Type - Pset_ColumnCommon - Reference: Hormigón_PI-1/0(?); IsExternal: no; LoadBearing: yes
Type - Pset_ProductRequirements - Name: PILOTE; Category: Columns
Type - Pset_QuantityTakeOff - Reference: Hormigón_PI-1/0(?)
Type - Pset_ReinforcementBarPitchOfColumn - Reference: Hormigón_PI-1/0(?)
Material: CONCRETE/28MPa 117
BaseQuantities - GrossVolume: 3.13841 m3
Pset_ColumnCommon - Slope: 0 rad
Pset_QuantityTakeOff - sets with these values: 2
Constraints - Moves With Grids: yes; Moves With Nearby Elements: yes; Room Bounding: yes
Dimensions - Area: 0.282732 m2; Volume: 3.13841 m3
Other - Family: PILOTE 184: PILOTE 184; Family and Type: PILOTE 184: PILOTE 184; Type: PILOTE 184: PILOTE 184; Type Id: PILOTE 184: PILOTE 184
Phasing - Phase Created: New Construction

# IfcColumn: PILOTE, PILOTE 192:PILOTE 192:201165
In: Default
Type - Description: D600; PredefinedType: COLUMN; Classification: A1020110 Piles - CIP (Uniformat)
Type - Graphics - Coarse Scale Fill Color: 0
Type - Identity Data - Assembly Code: A1020110; Assembly Description: Piles - CIP; Type Name: PILOTE 192
Type - Other - Category: Columns; Family Name: PILOTE 192
Type - Pset_ColumnCommon - Reference: Hormigón_PI-1/0(?); IsExternal: no; LoadBearing: yes
Type - Pset_ProductRequirements - Name: PILOTE; Category: Columns
Type - Pset_QuantityTakeOff - Reference: Hormigón_PI-1/0(?)
Type - Pset_ReinforcementBarPitchOfColumn - Reference: Hormigón_PI-1/0(?)
Material: CONCRETE/28MPa 117
BaseQuantities - GrossVolume: 3.13841 m3
Pset_ColumnCommon - Slope: 0 rad
Pset_QuantityTakeOff - sets with these values: 2
Constraints - Moves With Grids: yes; Moves With Nearby Elements: yes; Room Bounding: yes
Dimensions - Area: 0.282732 m2; Volume: 3.13841 m3
Other - Family: PILOTE 192: PILOTE 192; Family and Type: PILOTE 192: PILOTE 192; Type: PILOTE 192: PILOTE 192; Type Id: PILOTE 192: PILOTE 192
Phasing - Phase Created: New Construction

# IfcColumn: PILOTE, PILOTE 200:PILOTE 200:201177
In: Default
Type - Description: D600; PredefinedType: COLUMN; Classification: A1020110 Piles - CIP (Uniformat)
Type - Graphics - Coarse Scale Fill Color: 0
Type - Identity Data - Assembly Code: A1020110; Assembly Description: Piles - CIP; Type Name: PILOTE 200
Type - Other - Category: Columns; Family Name: PILOTE 200
Type - Pset_ColumnCommon - Reference: Hormigón_PI-1/0(?); IsExternal: no; LoadBearing: yes
Type - Pset_ProductRequirements - Name: PILOTE; Category: Columns
Type - Pset_QuantityTakeOff - Reference: Hormigón_PI-1/0(?)
Type - Pset_ReinforcementBarPitchOfColumn - Reference: Hormigón_PI-1/0(?)
Material: CONCRETE/28MPa 117
BaseQuantities - GrossVolume: 3.13841 m3
Pset_ColumnCommon - Slope: 0 rad
Pset_QuantityTakeOff - sets with these values: 2
Constraints - Moves With Grids: yes; Moves With Nearby Elements: yes; Room Bounding: yes
Dimensions - Area: 0.282732 m2; Volume: 3.13841 m3
Other - Family: PILOTE 200: PILOTE 200; Family and Type: PILOTE 200: PILOTE 200; Type: PILOTE 200: PILOTE 200; Type Id: PILOTE 200: PILOTE 200
Phasing - Phase Created: New Construction

# IfcColumn: PILOTE, PILOTE 208:PILOTE 208:201189
In: Default
Type - Description: D600; PredefinedType: COLUMN; Classification: A1020110 Piles - CIP (Uniformat)
Type - Graphics - Coarse Scale Fill Color: 0
Type - Identity Data - Assembly Code: A1020110; Assembly Description: Piles - CIP; Type Name: PILOTE 208
Type - Other - Category: Columns; Family Name: PILOTE 208
Type - Pset_ColumnCommon - Reference: Hormigón_PI-1/0(?); IsExternal: no; LoadBearing: yes
Type - Pset_ProductRequirements - Name: PILOTE; Category: Columns
Type - Pset_QuantityTakeOff - Reference: Hormigón_PI-1/0(?)
Type - Pset_ReinforcementBarPitchOfColumn - Reference: Hormigón_PI-1/0(?)
Material: CONCRETE/28MPa 117
BaseQuantities - GrossVolume: 3.13841 m3
Pset_ColumnCommon - Slope: 0 rad
Pset_QuantityTakeOff - sets with these values: 2
Constraints - Moves With Grids: yes; Moves With Nearby Elements: yes; Room Bounding: yes
Dimensions - Area: 0.282732 m2; Volume: 3.13841 m3
Other - Family: PILOTE 208: PILOTE 208; Family and Type: PILOTE 208: PILOTE 208; Type: PILOTE 208: PILOTE 208; Type Id: PILOTE 208: PILOTE 208
Phasing - Phase Created: New Construction

# IfcColumn: PILOTE, PILOTE 218:PILOTE 218:201201
In: Default
Type - Description: D600; PredefinedType: COLUMN; Classification: A1020110 Piles - CIP (Uniformat)
Type - Graphics - Coarse Scale Fill Color: 0
Type - Identity Data - Assembly Code: A1020110; Assembly Description: Piles - CIP; Type Name: PILOTE 218
Type - Other - Category: Columns; Family Name: PILOTE 218
Type - Pset_ColumnCommon - Reference: Hormigón_PI-1/0(?); IsExternal: no; LoadBearing: yes
Type - Pset_ProductRequirements - Name: PILOTE; Category: Columns
Type - Pset_QuantityTakeOff - Reference: Hormigón_PI-1/0(?)
Type - Pset_ReinforcementBarPitchOfColumn - Reference: Hormigón_PI-1/0(?)
Material: CONCRETE/28MPa 117
BaseQuantities - GrossVolume: 3.13841 m3
Pset_ColumnCommon - Slope: 0 rad
Pset_QuantityTakeOff - sets with these values: 2
Constraints - Moves With Grids: yes; Moves With Nearby Elements: yes; Room Bounding: yes
Dimensions - Area: 0.282732 m2; Volume: 3.13841 m3
Other - Family: PILOTE 218: PILOTE 218; Family and Type: PILOTE 218: PILOTE 218; Type: PILOTE 218: PILOTE 218; Type Id: PILOTE 218: PILOTE 218
Phasing - Phase Created: New Construction

# IfcColumn: PILOTE, PILOTE 228:PILOTE 228:201213
In: Default
Type - Description: D600; PredefinedType: COLUMN; Classification: A1020110 Piles - CIP (Uniformat)
Type - Graphics - Coarse Scale Fill Color: 0
Type - Identity Data - Assembly Code: A1020110; Assembly Description: Piles - CIP; Type Name: PILOTE 228
Type - Other - Category: Columns; Family Name: PILOTE 228
Type - Pset_ColumnCommon - Reference: Hormigón_PI-1/0(?); IsExternal: no; LoadBearing: yes
Type - Pset_ProductRequirements - Name: PILOTE; Category: Columns
Type - Pset_QuantityTakeOff - Reference: Hormigón_PI-1/0(?)
Type - Pset_ReinforcementBarPitchOfColumn - Reference: Hormigón_PI-1/0(?)
Material: CONCRETE/28MPa 117
BaseQuantities - GrossVolume: 3.13841 m3
Pset_ColumnCommon - Slope: 0 rad
Pset_QuantityTakeOff - sets with these values: 2
Constraints - Moves With Grids: yes; Moves With Nearby Elements: yes; Room Bounding: yes
Dimensions - Area: 0.282732 m2; Volume: 3.13841 m3
Other - Family: PILOTE 228: PILOTE 228; Family and Type: PILOTE 228: PILOTE 228; Type: PILOTE 228: PILOTE 228; Type Id: PILOTE 228: PILOTE 228
Phasing - Phase Created: New Construction

# IfcColumn: PILOTE, PILOTE 236:PILOTE 236:201225
In: Default
Type - Description: D600; PredefinedType: COLUMN; Classification: A1020110 Piles - CIP (Uniformat)
Type - Graphics - Coarse Scale Fill Color: 0
Type - Identity Data - Assembly Code: A1020110; Assembly Description: Piles - CIP; Type Name: PILOTE 236
Type - Other - Category: Columns; Family Name: PILOTE 236
Type - Pset_ColumnCommon - Reference: Hormigón_PI-1/0(?); IsExternal: no; LoadBearing: yes
Type - Pset_ProductRequirements - Name: PILOTE; Category: Columns
Type - Pset_QuantityTakeOff - Reference: Hormigón_PI-1/0(?)
Type - Pset_ReinforcementBarPitchOfColumn - Reference: Hormigón_PI-1/0(?)
Material: CONCRETE/28MPa 117
BaseQuantities - GrossVolume: 3.13841 m3
Pset_ColumnCommon - Slope: 0 rad
Pset_QuantityTakeOff - sets with these values: 2
Constraints - Moves With Grids: yes; Moves With Nearby Elements: yes; Room Bounding: yes
Dimensions - Area: 0.282732 m2; Volume: 3.13841 m3
Other - Family: PILOTE 236: PILOTE 236; Family and Type: PILOTE 236: PILOTE 236; Type: PILOTE 236: PILOTE 236; Type Id: PILOTE 236: PILOTE 236
Phasing - Phase Created: New Construction

# IfcColumn: PILOTE, PILOTE 244:PILOTE 244:201237
In: Default
Type - Description: D600; PredefinedType: COLUMN; Classification: A1020110 Piles - CIP (Uniformat)
Type - Graphics - Coarse Scale Fill Color: 0
Type - Identity Data - Assembly Code: A1020110; Assembly Description: Piles - CIP; Type Name: PILOTE 244
Type - Other - Category: Columns; Family Name: PILOTE 244
Type - Pset_ColumnCommon - Reference: Hormigón_PI-1/0(?); IsExternal: no; LoadBearing: yes
Type - Pset_ProductRequirements - Name: PILOTE; Category: Columns
Type - Pset_QuantityTakeOff - Reference: Hormigón_PI-1/0(?)
Type - Pset_ReinforcementBarPitchOfColumn - Reference: Hormigón_PI-1/0(?)
Material: CONCRETE/28MPa 117
BaseQuantities - GrossVolume: 3.13841 m3
Pset_ColumnCommon - Slope: 0 rad
Pset_QuantityTakeOff - sets with these values: 2
Constraints - Moves With Grids: yes; Moves With Nearby Elements: yes; Room Bounding: yes
Dimensions - Area: 0.282732 m2; Volume: 3.13841 m3
Other - Family: PILOTE 244: PILOTE 244; Family and Type: PILOTE 244: PILOTE 244; Type: PILOTE 244: PILOTE 244; Type Id: PILOTE 244: PILOTE 244
Phasing - Phase Created: New Construction

# IfcColumn: PILOTE, PILOTE 252:PILOTE 252:201249
In: Default
Type - Description: D600; PredefinedType: COLUMN; Classification: A1020110 Piles - CIP (Uniformat)
Type - Graphics - Coarse Scale Fill Color: 0
Type - Identity Data - Assembly Code: A1020110; Assembly Description: Piles - CIP; Type Name: PILOTE 252
Type - Other - Category: Columns; Family Name: PILOTE 252
Type - Pset_ColumnCommon - Reference: Hormigón_PI-1/0(?); IsExternal: no; LoadBearing: yes
Type - Pset_ProductRequirements - Name: PILOTE; Category: Columns
Type - Pset_QuantityTakeOff - Reference: Hormigón_PI-1/0(?)
Type - Pset_ReinforcementBarPitchOfColumn - Reference: Hormigón_PI-1/0(?)
Material: CONCRETE/28MPa 117
BaseQuantities - GrossVolume: 3.13841 m3
Pset_ColumnCommon - Slope: 0 rad
Pset_QuantityTakeOff - sets with these values: 2
Constraints - Moves With Grids: yes; Moves With Nearby Elements: yes; Room Bounding: yes
Dimensions - Area: 0.282732 m2; Volume: 3.13841 m3
Other - Family: PILOTE 252: PILOTE 252; Family and Type: PILOTE 252: PILOTE 252; Type: PILOTE 252: PILOTE 252; Type Id: PILOTE 252: PILOTE 252
Phasing - Phase Created: New Construction

# IfcColumn: PILOTE, PILOTE 260:PILOTE 260:201261
In: Default
Type - Description: D600; PredefinedType: COLUMN; Classification: A1020110 Piles - CIP (Uniformat)
Type - Graphics - Coarse Scale Fill Color: 0
Type - Identity Data - Assembly Code: A1020110; Assembly Description: Piles - CIP; Type Name: PILOTE 260
Type - Other - Category: Columns; Family Name: PILOTE 260
Type - Pset_ColumnCommon - Reference: Hormigón_PI-1/0(?); IsExternal: no; LoadBearing: yes
Type - Pset_ProductRequirements - Name: PILOTE; Category: Columns
Type - Pset_QuantityTakeOff - Reference: Hormigón_PI-1/0(?)
Type - Pset_ReinforcementBarPitchOfColumn - Reference: Hormigón_PI-1/0(?)
Material: CONCRETE/28MPa 117
BaseQuantities - GrossVolume: 3.13841 m3
Pset_ColumnCommon - Slope: 0 rad
Pset_QuantityTakeOff - sets with these values: 2
Constraints - Moves With Grids: yes; Moves With Nearby Elements: yes; Room Bounding: yes
Dimensions - Area: 0.282732 m2; Volume: 3.13841 m3
Other - Family: PILOTE 260: PILOTE 260; Family and Type: PILOTE 260: PILOTE 260; Type: PILOTE 260: PILOTE 260; Type Id: PILOTE 260: PILOTE 260
Phasing - Phase Created: New Construction

# IfcColumn: PILOTE, PILOTE 270:PILOTE 270:201273
In: Default
Type - Description: D600; PredefinedType: COLUMN; Classification: A1020110 Piles - CIP (Uniformat)
Type - Graphics - Coarse Scale Fill Color: 0
Type - Identity Data - Assembly Code: A1020110; Assembly Description: Piles - CIP; Type Name: PILOTE 270
Type - Other - Category: Columns; Family Name: PILOTE 270
Type - Pset_ColumnCommon - Reference: Hormigón_PI-1/0(?); IsExternal: no; LoadBearing: yes
Type - Pset_ProductRequirements - Name: PILOTE; Category: Columns
Type - Pset_QuantityTakeOff - Reference: Hormigón_PI-1/0(?)
Type - Pset_ReinforcementBarPitchOfColumn - Reference: Hormigón_PI-1/0(?)
Material: CONCRETE/28MPa 117
BaseQuantities - GrossVolume: 3.13841 m3
Pset_ColumnCommon - Slope: 0 rad
Pset_QuantityTakeOff - sets with these values: 2
Constraints - Moves With Grids: yes; Moves With Nearby Elements: yes; Room Bounding: yes
Dimensions - Area: 0.282732 m2; Volume: 3.13841 m3
Other - Family: PILOTE 270: PILOTE 270; Family and Type: PILOTE 270: PILOTE 270; Type: PILOTE 270: PILOTE 270; Type Id: PILOTE 270: PILOTE 270
Phasing - Phase Created: New Construction

# IfcColumn: PILOTE, PILOTE 278:PILOTE 278:201285
In: Default
Type - Description: D600; PredefinedType: COLUMN; Classification: A1020110 Piles - CIP (Uniformat)
Type - Graphics - Coarse Scale Fill Color: 0
Type - Identity Data - Assembly Code: A1020110; Assembly Description: Piles - CIP; Type Name: PILOTE 278
Type - Other - Category: Columns; Family Name: PILOTE 278
Type - Pset_ColumnCommon - Reference: Hormigón_PI-1/0(?); IsExternal: no; LoadBearing: yes
Type - Pset_ProductRequirements - Name: PILOTE; Category: Columns
Type - Pset_QuantityTakeOff - Reference: Hormigón_PI-1/0(?)
Type - Pset_ReinforcementBarPitchOfColumn - Reference: Hormigón_PI-1/0(?)
Material: CONCRETE/28MPa 117
BaseQuantities - GrossVolume: 3.13841 m3
Pset_ColumnCommon - Slope: 0 rad
Pset_QuantityTakeOff - sets with these values: 2
Constraints - Moves With Grids: yes; Moves With Nearby Elements: yes; Room Bounding: yes
Dimensions - Area: 0.282732 m2; Volume: 3.13841 m3
Other - Family: PILOTE 278: PILOTE 278; Family and Type: PILOTE 278: PILOTE 278; Type: PILOTE 278: PILOTE 278; Type Id: PILOTE 278: PILOTE 278
Phasing - Phase Created: New Construction

# IfcColumn: PILOTE, PILOTE 288:PILOTE 288:201297
In: Default
Type - Description: D600; PredefinedType: COLUMN; Classification: A1020110 Piles - CIP (Uniformat)
Type - Graphics - Coarse Scale Fill Color: 0
Type - Identity Data - Assembly Code: A1020110; Assembly Description: Piles - CIP; Type Name: PILOTE 288
Type - Other - Category: Columns; Family Name: PILOTE 288
Type - Pset_ColumnCommon - Reference: Hormigón_PI-1/0(?); IsExternal: no; LoadBearing: yes
Type - Pset_ProductRequirements - Name: PILOTE; Category: Columns
Type - Pset_QuantityTakeOff - Reference: Hormigón_PI-1/0(?)
Type - Pset_ReinforcementBarPitchOfColumn - Reference: Hormigón_PI-1/0(?)
Material: CONCRETE/28MPa 117
BaseQuantities - GrossVolume: 3.13841 m3
Pset_ColumnCommon - Slope: 0 rad
Pset_QuantityTakeOff - sets with these values: 2
Constraints - Moves With Grids: yes; Moves With Nearby Elements: yes; Room Bounding: yes
Dimensions - Area: 0.282732 m2; Volume: 3.13841 m3
Other - Family: PILOTE 288: PILOTE 288; Family and Type: PILOTE 288: PILOTE 288; Type: PILOTE 288: PILOTE 288; Type Id: PILOTE 288: PILOTE 288
Phasing - Phase Created: New Construction

# IfcColumn: PILOTE, PILOTE 296:PILOTE 296:201309
In: Default
Type - Description: D600; PredefinedType: COLUMN; Classification: A1020110 Piles - CIP (Uniformat)
Type - Graphics - Coarse Scale Fill Color: 0
Type - Identity Data - Assembly Code: A1020110; Assembly Description: Piles - CIP; Type Name: PILOTE 296
Type - Other - Category: Columns; Family Name: PILOTE 296
Type - Pset_ColumnCommon - Reference: Hormigón_PI-1/0(?); IsExternal: no; LoadBearing: yes
Type - Pset_ProductRequirements - Name: PILOTE; Category: Columns
Type - Pset_QuantityTakeOff - Reference: Hormigón_PI-1/0(?)
Type - Pset_ReinforcementBarPitchOfColumn - Reference: Hormigón_PI-1/0(?)
Material: CONCRETE/28MPa 117
BaseQuantities - GrossVolume: 3.13841 m3
Pset_ColumnCommon - Slope: 0 rad
Pset_QuantityTakeOff - sets with these values: 2
Constraints - Moves With Grids: yes; Moves With Nearby Elements: yes; Room Bounding: yes
Dimensions - Area: 0.282732 m2; Volume: 3.13841 m3
Other - Family: PILOTE 296: PILOTE 296; Family and Type: PILOTE 296: PILOTE 296; Type: PILOTE 296: PILOTE 296; Type Id: PILOTE 296: PILOTE 296
Phasing - Phase Created: New Construction

# IfcColumn: PILOTE, PILOTE 306:PILOTE 306:201321
In: Default
Type - Description: D600; PredefinedType: COLUMN; Classification: A1020110 Piles - CIP (Uniformat)
Type - Graphics - Coarse Scale Fill Color: 0
Type - Identity Data - Assembly Code: A1020110; Assembly Description: Piles - CIP; Type Name: PILOTE 306
Type - Other - Category: Columns; Family Name: PILOTE 306
Type - Pset_ColumnCommon - Reference: Hormigón_PI-1/0(?); IsExternal: no; LoadBearing: yes
Type - Pset_ProductRequirements - Name: PILOTE; Category: Columns
Type - Pset_QuantityTakeOff - Reference: Hormigón_PI-1/0(?)
Type - Pset_ReinforcementBarPitchOfColumn - Reference: Hormigón_PI-1/0(?)
Material: CONCRETE/28MPa 117
BaseQuantities - GrossVolume: 3.13841 m3
Pset_ColumnCommon - Slope: 0 rad
Pset_QuantityTakeOff - sets with these values: 2
Constraints - Moves With Grids: yes; Moves With Nearby Elements: yes; Room Bounding: yes
Dimensions - Area: 0.282732 m2; Volume: 3.13841 m3
Other - Family: PILOTE 306: PILOTE 306; Family and Type: PILOTE 306: PILOTE 306; Type: PILOTE 306: PILOTE 306; Type Id: PILOTE 306: PILOTE 306
Phasing - Phase Created: New Construction

# IfcColumn: PILOTE, PILOTE 316:PILOTE 316:201333
In: Default
Type - Description: D600; PredefinedType: COLUMN; Classification: A1020110 Piles - CIP (Uniformat)
Type - Graphics - Coarse Scale Fill Color: 0
Type - Identity Data - Assembly Code: A1020110; Assembly Description: Piles - CIP; Type Name: PILOTE 316
Type - Other - Category: Columns; Family Name: PILOTE 316
Type - Pset_ColumnCommon - Reference: Hormigón_PI-1/0(?); IsExternal: no; LoadBearing: yes
Type - Pset_ProductRequirements - Name: PILOTE; Category: Columns
Type - Pset_QuantityTakeOff - Reference: Hormigón_PI-1/0(?)
Type - Pset_ReinforcementBarPitchOfColumn - Reference: Hormigón_PI-1/0(?)
Material: CONCRETE/28MPa 117
BaseQuantities - GrossVolume: 3.13841 m3
Pset_ColumnCommon - Slope: 0 rad
Pset_QuantityTakeOff - sets with these values: 2
Constraints - Moves With Grids: yes; Moves With Nearby Elements: yes; Room Bounding: yes
Dimensions - Area: 0.282732 m2; Volume: 3.13841 m3
Other - Family: PILOTE 316: PILOTE 316; Family and Type: PILOTE 316: PILOTE 316; Type: PILOTE 316: PILOTE 316; Type Id: PILOTE 316: PILOTE 316
Phasing - Phase Created: New Construction

# IfcColumn: PILOTE, PILOTE 326:PILOTE 326:201345
In: Default
Type - Description: D600; PredefinedType: COLUMN; Classification: A1020110 Piles - CIP (Uniformat)
Type - Graphics - Coarse Scale Fill Color: 0
Type - Identity Data - Assembly Code: A1020110; Assembly Description: Piles - CIP; Type Name: PILOTE 326
Type - Other - Category: Columns; Family Name: PILOTE 326
Type - Pset_ColumnCommon - Reference: Hormigón_PI-1/0(?); IsExternal: no; LoadBearing: yes
Type - Pset_ProductRequirements - Name: PILOTE; Category: Columns
Type - Pset_QuantityTakeOff - Reference: Hormigón_PI-1/0(?)
Type - Pset_ReinforcementBarPitchOfColumn - Reference: Hormigón_PI-1/0(?)
Material: CONCRETE/28MPa 117
BaseQuantities - GrossVolume: 3.13841 m3
Pset_ColumnCommon - Slope: 0 rad
Pset_QuantityTakeOff - sets with these values: 2
Constraints - Moves With Grids: yes; Moves With Nearby Elements: yes; Room Bounding: yes
Dimensions - Area: 0.282732 m2; Volume: 3.13841 m3
Other - Family: PILOTE 326: PILOTE 326; Family and Type: PILOTE 326: PILOTE 326; Type: PILOTE 326: PILOTE 326; Type Id: PILOTE 326: PILOTE 326
Phasing - Phase Created: New Construction

# IfcColumn: PILOTE, PILOTE 336:PILOTE 336:201357
In: Default
Type - Description: D600; PredefinedType: COLUMN; Classification: A1020110 Piles - CIP (Uniformat)
Type - Graphics - Coarse Scale Fill Color: 0
Type - Identity Data - Assembly Code: A1020110; Assembly Description: Piles - CIP; Type Name: PILOTE 336
Type - Other - Category: Columns; Family Name: PILOTE 336
Type - Pset_ColumnCommon - Reference: Hormigón_PI-1/0(?); IsExternal: no; LoadBearing: yes
Type - Pset_ProductRequirements - Name: PILOTE; Category: Columns
Type - Pset_QuantityTakeOff - Reference: Hormigón_PI-1/0(?)
Type - Pset_ReinforcementBarPitchOfColumn - Reference: Hormigón_PI-1/0(?)
Material: CONCRETE/28MPa 117
BaseQuantities - GrossVolume: 3.13841 m3
Pset_ColumnCommon - Slope: 0 rad
Pset_QuantityTakeOff - sets with these values: 2
Constraints - Moves With Grids: yes; Moves With Nearby Elements: yes; Room Bounding: yes
Dimensions - Area: 0.282732 m2; Volume: 3.13841 m3
Other - Family: PILOTE 336: PILOTE 336; Family and Type: PILOTE 336: PILOTE 336; Type: PILOTE 336: PILOTE 336; Type Id: PILOTE 336: PILOTE 336
Phasing - Phase Created: New Construction

# IfcColumn: PILOTE, PILOTE 346:PILOTE 346:201369
In: Default
Type - Description: D600; PredefinedType: COLUMN; Classification: A1020110 Piles - CIP (Uniformat)
Type - Graphics - Coarse Scale Fill Color: 0
Type - Identity Data - Assembly Code: A1020110; Assembly Description: Piles - CIP; Type Name: PILOTE 346
Type - Other - Category: Columns; Family Name: PILOTE 346
Type - Pset_ColumnCommon - Reference: Hormigón_PI-1/0(?); IsExternal: no; LoadBearing: yes
Type - Pset_ProductRequirements - Name: PILOTE; Category: Columns
Type - Pset_QuantityTakeOff - Reference: Hormigón_PI-1/0(?)
Type - Pset_ReinforcementBarPitchOfColumn - Reference: Hormigón_PI-1/0(?)
Material: CONCRETE/28MPa 117
BaseQuantities - GrossVolume: 3.13841 m3
Pset_ColumnCommon - Slope: 0 rad
Pset_QuantityTakeOff - sets with these values: 2
Constraints - Moves With Grids: yes; Moves With Nearby Elements: yes; Room Bounding: yes
Dimensions - Area: 0.282732 m2; Volume: 3.13841 m3
Other - Family: PILOTE 346: PILOTE 346; Family and Type: PILOTE 346: PILOTE 346; Type: PILOTE 346: PILOTE 346; Type Id: PILOTE 346: PILOTE 346
Phasing - Phase Created: New Construction

# IfcColumn: PILOTE, PILOTE 354:PILOTE 354:201381
In: Default
Type - Description: D600; PredefinedType: COLUMN; Classification: A1020110 Piles - CIP (Uniformat)
Type - Graphics - Coarse Scale Fill Color: 0
Type - Identity Data - Assembly Code: A1020110; Assembly Description: Piles - CIP; Type Name: PILOTE 354
Type - Other - Category: Columns; Family Name: PILOTE 354
Type - Pset_ColumnCommon - Reference: Hormigón_PI-1/0(?); IsExternal: no; LoadBearing: yes
Type - Pset_ProductRequirements - Name: PILOTE; Category: Columns
Type - Pset_QuantityTakeOff - Reference: Hormigón_PI-1/0(?)
Type - Pset_ReinforcementBarPitchOfColumn - Reference: Hormigón_PI-1/0(?)
Material: CONCRETE/28MPa 117
BaseQuantities - GrossVolume: 3.13841 m3
Pset_ColumnCommon - Slope: 0 rad
Pset_QuantityTakeOff - sets with these values: 2
Constraints - Moves With Grids: yes; Moves With Nearby Elements: yes; Room Bounding: yes
Dimensions - Area: 0.282732 m2; Volume: 3.13841 m3
Other - Family: PILOTE 354: PILOTE 354; Family and Type: PILOTE 354: PILOTE 354; Type: PILOTE 354: PILOTE 354; Type Id: PILOTE 354: PILOTE 354
Phasing - Phase Created: New Construction

# IfcColumn: PILOTE, PILOTE 362:PILOTE 362:201393
In: Default
Type - Description: D600; PredefinedType: COLUMN; Classification: A1020110 Piles - CIP (Uniformat)
Type - Graphics - Coarse Scale Fill Color: 0
Type - Identity Data - Assembly Code: A1020110; Assembly Description: Piles - CIP; Type Name: PILOTE 362
Type - Other - Category: Columns; Family Name: PILOTE 362
Type - Pset_ColumnCommon - Reference: Hormigón_PI-1/0(?); IsExternal: no; LoadBearing: yes
Type - Pset_ProductRequirements - Name: PILOTE; Category: Columns
Type - Pset_QuantityTakeOff - Reference: Hormigón_PI-1/0(?)
Type - Pset_ReinforcementBarPitchOfColumn - Reference: Hormigón_PI-1/0(?)
Material: CONCRETE/28MPa 117
BaseQuantities - GrossVolume: 3.13841 m3
Pset_ColumnCommon - Slope: 0 rad
Pset_QuantityTakeOff - sets with these values: 2
Constraints - Moves With Grids: yes; Moves With Nearby Elements: yes; Room Bounding: yes
Dimensions - Area: 0.282732 m2; Volume: 3.13841 m3
Other - Family: PILOTE 362: PILOTE 362; Family and Type: PILOTE 362: PILOTE 362; Type: PILOTE 362: PILOTE 362; Type Id: PILOTE 362: PILOTE 362
Phasing - Phase Created: New Construction

# IfcColumn: PILOTE, PILOTE 370:PILOTE 370:201405
In: Default
Type - Description: D600; PredefinedType: COLUMN; Classification: A1020110 Piles - CIP (Uniformat)
Type - Graphics - Coarse Scale Fill Color: 0
Type - Identity Data - Assembly Code: A1020110; Assembly Description: Piles - CIP; Type Name: PILOTE 370
Type - Other - Category: Columns; Family Name: PILOTE 370
Type - Pset_ColumnCommon - Reference: Hormigón_PI-1/0(?); IsExternal: no; LoadBearing: yes
Type - Pset_ProductRequirements - Name: PILOTE; Category: Columns
Type - Pset_QuantityTakeOff - Reference: Hormigón_PI-1/0(?)
Type - Pset_ReinforcementBarPitchOfColumn - Reference: Hormigón_PI-1/0(?)
Material: CONCRETE/28MPa 117
BaseQuantities - GrossVolume: 3.13841 m3
Pset_ColumnCommon - Slope: 0 rad
Pset_QuantityTakeOff - sets with these values: 2
Constraints - Moves With Grids: yes; Moves With Nearby Elements: yes; Room Bounding: yes
Dimensions - Area: 0.282732 m2; Volume: 3.13841 m3
Other - Family: PILOTE 370: PILOTE 370; Family and Type: PILOTE 370: PILOTE 370; Type: PILOTE 370: PILOTE 370; Type Id: PILOTE 370: PILOTE 370
Phasing - Phase Created: New Construction

# IfcColumn: PILOTE, PILOTE 378:PILOTE 378:201417
In: Default
Type - Description: D600; PredefinedType: COLUMN; Classification: A1020110 Piles - CIP (Uniformat)
Type - Graphics - Coarse Scale Fill Color: 0
Type - Identity Data - Assembly Code: A1020110; Assembly Description: Piles - CIP; Type Name: PILOTE 378
Type - Other - Category: Columns; Family Name: PILOTE 378
Type - Pset_ColumnCommon - Reference: Hormigón_PI-1/0(?); IsExternal: no; LoadBearing: yes
Type - Pset_ProductRequirements - Name: PILOTE; Category: Columns
Type - Pset_QuantityTakeOff - Reference: Hormigón_PI-1/0(?)
Type - Pset_ReinforcementBarPitchOfColumn - Reference: Hormigón_PI-1/0(?)
Material: CONCRETE/28MPa 117
BaseQuantities - GrossVolume: 3.13841 m3
Pset_ColumnCommon - Slope: 0 rad
Pset_QuantityTakeOff - sets with these values: 2
Constraints - Moves With Grids: yes; Moves With Nearby Elements: yes; Room Bounding: yes
Dimensions - Area: 0.282732 m2; Volume: 3.13841 m3
Other - Family: PILOTE 378: PILOTE 378; Family and Type: PILOTE 378: PILOTE 378; Type: PILOTE 378: PILOTE 378; Type Id: PILOTE 378: PILOTE 378
Phasing - Phase Created: New Construction

# IfcColumn: PILOTE, PILOTE 388:PILOTE 388:201429
In: Default
Type - Description: D600; PredefinedType: COLUMN; Classification: A1020110 Piles - CIP (Uniformat)
Type - Graphics - Coarse Scale Fill Color: 0
Type - Identity Data - Assembly Code: A1020110; Assembly Description: Piles - CIP; Type Name: PILOTE 388
Type - Other - Category: Columns; Family Name: PILOTE 388
Type - Pset_ColumnCommon - Reference: Hormigón_PI-1/0(?); IsExternal: no; LoadBearing: yes
Type - Pset_ProductRequirements - Name: PILOTE; Category: Columns
Type - Pset_QuantityTakeOff - Reference: Hormigón_PI-1/0(?)
Type - Pset_ReinforcementBarPitchOfColumn - Reference: Hormigón_PI-1/0(?)
Material: CONCRETE/28MPa 117
BaseQuantities - GrossVolume: 3.13841 m3
Pset_ColumnCommon - Slope: 0 rad
Pset_QuantityTakeOff - sets with these values: 2
Constraints - Moves With Grids: yes; Moves With Nearby Elements: yes; Room Bounding: yes
Dimensions - Area: 0.282732 m2; Volume: 3.13841 m3
Other - Family: PILOTE 388: PILOTE 388; Family and Type: PILOTE 388: PILOTE 388; Type: PILOTE 388: PILOTE 388; Type Id: PILOTE 388: PILOTE 388
Phasing - Phase Created: New Construction

# IfcColumn: PILOTE, PILOTE 396:PILOTE 396:201441
In: Default
Type - Description: D600; PredefinedType: COLUMN; Classification: A1020110 Piles - CIP (Uniformat)
Type - Graphics - Coarse Scale Fill Color: 0
Type - Identity Data - Assembly Code: A1020110; Assembly Description: Piles - CIP; Type Name: PILOTE 396
Type - Other - Category: Columns; Family Name: PILOTE 396
Type - Pset_ColumnCommon - Reference: Hormigón_PI-1/0(?); IsExternal: no; LoadBearing: yes
Type - Pset_ProductRequirements - Name: PILOTE; Category: Columns
Type - Pset_QuantityTakeOff - Reference: Hormigón_PI-1/0(?)
Type - Pset_ReinforcementBarPitchOfColumn - Reference: Hormigón_PI-1/0(?)
Material: CONCRETE/28MPa 117
BaseQuantities - GrossVolume: 3.13841 m3
Pset_ColumnCommon - Slope: 0 rad
Pset_QuantityTakeOff - sets with these values: 2
Constraints - Moves With Grids: yes; Moves With Nearby Elements: yes; Room Bounding: yes
Dimensions - Area: 0.282732 m2; Volume: 3.13841 m3
Other - Family: PILOTE 396: PILOTE 396; Family and Type: PILOTE 396: PILOTE 396; Type: PILOTE 396: PILOTE 396; Type Id: PILOTE 396: PILOTE 396
Phasing - Phase Created: New Construction

# IfcColumn: PILOTE, PILOTE 406:PILOTE 406:201453
In: Default
Type - Description: D600; PredefinedType: COLUMN; Classification: A1020110 Piles - CIP (Uniformat)
Type - Graphics - Coarse Scale Fill Color: 0
Type - Identity Data - Assembly Code: A1020110; Assembly Description: Piles - CIP; Type Name: PILOTE 406
Type - Other - Category: Columns; Family Name: PILOTE 406
Type - Pset_ColumnCommon - Reference: Hormigón_PI-1/0(?); IsExternal: no; LoadBearing: yes
Type - Pset_ProductRequirements - Name: PILOTE; Category: Columns
Type - Pset_QuantityTakeOff - Reference: Hormigón_PI-1/0(?)
Type - Pset_ReinforcementBarPitchOfColumn - Reference: Hormigón_PI-1/0(?)
Material: CONCRETE/28MPa 117
BaseQuantities - GrossVolume: 3.13841 m3
Pset_ColumnCommon - Slope: 0 rad
Pset_QuantityTakeOff - sets with these values: 2
Constraints - Moves With Grids: yes; Moves With Nearby Elements: yes; Room Bounding: yes
Dimensions - Area: 0.282732 m2; Volume: 3.13841 m3
Other - Family: PILOTE 406: PILOTE 406; Family and Type: PILOTE 406: PILOTE 406; Type: PILOTE 406: PILOTE 406; Type Id: PILOTE 406: PILOTE 406
Phasing - Phase Created: New Construction

# IfcColumn: PILOTE, PILOTE 414:PILOTE 414:201465
In: Default
Type - Description: D600; PredefinedType: COLUMN; Classification: A1020110 Piles - CIP (Uniformat)
Type - Graphics - Coarse Scale Fill Color: 0
Type - Identity Data - Assembly Code: A1020110; Assembly Description: Piles - CIP; Type Name: PILOTE 414
Type - Other - Category: Columns; Family Name: PILOTE 414
Type - Pset_ColumnCommon - Reference: Hormigón_PI-1/0(?); IsExternal: no; LoadBearing: yes
Type - Pset_ProductRequirements - Name: PILOTE; Category: Columns
Type - Pset_QuantityTakeOff - Reference: Hormigón_PI-1/0(?)
Type - Pset_ReinforcementBarPitchOfColumn - Reference: Hormigón_PI-1/0(?)
Material: CONCRETE/28MPa 117
BaseQuantities - GrossVolume: 3.13841 m3
Pset_ColumnCommon - Slope: 0 rad
Pset_QuantityTakeOff - sets with these values: 2
Constraints - Moves With Grids: yes; Moves With Nearby Elements: yes; Room Bounding: yes
Dimensions - Area: 0.282732 m2; Volume: 3.13841 m3
Other - Family: PILOTE 414: PILOTE 414; Family and Type: PILOTE 414: PILOTE 414; Type: PILOTE 414: PILOTE 414; Type Id: PILOTE 414: PILOTE 414
Phasing - Phase Created: New Construction

# IfcColumn: PILOTE, PILOTE 422:PILOTE 422:201477
In: Default
Type - Description: D600; PredefinedType: COLUMN; Classification: A1020110 Piles - CIP (Uniformat)
Type - Graphics - Coarse Scale Fill Color: 0
Type - Identity Data - Assembly Code: A1020110; Assembly Description: Piles - CIP; Type Name: PILOTE 422
Type - Other - Category: Columns; Family Name: PILOTE 422
Type - Pset_ColumnCommon - Reference: Hormigón_PI-1/0(?); IsExternal: no; LoadBearing: yes
Type - Pset_ProductRequirements - Name: PILOTE; Category: Columns
Type - Pset_QuantityTakeOff - Reference: Hormigón_PI-1/0(?)
Type - Pset_ReinforcementBarPitchOfColumn - Reference: Hormigón_PI-1/0(?)
Material: CONCRETE/28MPa 117
BaseQuantities - GrossVolume: 3.13841 m3
Pset_ColumnCommon - Slope: 0 rad
Pset_QuantityTakeOff - sets with these values: 2
Constraints - Moves With Grids: yes; Moves With Nearby Elements: yes; Room Bounding: yes
Dimensions - Area: 0.282732 m2; Volume: 3.13841 m3
Other - Family: PILOTE 422: PILOTE 422; Family and Type: PILOTE 422: PILOTE 422; Type: PILOTE 422: PILOTE 422; Type Id: PILOTE 422: PILOTE 422
Phasing - Phase Created: New Construction

# IfcColumn: PILOTE, PILOTE 432:PILOTE 432:201489
In: Default
Type - Description: D600; PredefinedType: COLUMN; Classification: A1020110 Piles - CIP (Uniformat)
Type - Graphics - Coarse Scale Fill Color: 0
Type - Identity Data - Assembly Code: A1020110; Assembly Description: Piles - CIP; Type Name: PILOTE 432
Type - Other - Category: Columns; Family Name: PILOTE 432
Type - Pset_ColumnCommon - Reference: Hormigón_PI-1/0(?); IsExternal: no; LoadBearing: yes
Type - Pset_ProductRequirements - Name: PILOTE; Category: Columns
Type - Pset_QuantityTakeOff - Reference: Hormigón_PI-1/0(?)
Type - Pset_ReinforcementBarPitchOfColumn - Reference: Hormigón_PI-1/0(?)
Material: CONCRETE/28MPa 117
BaseQuantities - GrossVolume: 3.13841 m3
Pset_ColumnCommon - Slope: 0 rad
Pset_QuantityTakeOff - sets with these values: 2
Constraints - Moves With Grids: yes; Moves With Nearby Elements: yes; Room Bounding: yes
Dimensions - Area: 0.282732 m2; Volume: 3.13841 m3
Other - Family: PILOTE 432: PILOTE 432; Family and Type: PILOTE 432: PILOTE 432; Type: PILOTE 432: PILOTE 432; Type Id: PILOTE 432: PILOTE 432
Phasing - Phase Created: New Construction

# IfcColumn: PILOTE, PILOTE 440:PILOTE 440:201501
In: Default
Type - Description: D600; PredefinedType: COLUMN; Classification: A1020110 Piles - CIP (Uniformat)
Type - Graphics - Coarse Scale Fill Color: 0
Type - Identity Data - Assembly Code: A1020110; Assembly Description: Piles - CIP; Type Name: PILOTE 440
Type - Other - Category: Columns; Family Name: PILOTE 440
Type - Pset_ColumnCommon - Reference: Hormigón_PI-1/0(?); IsExternal: no; LoadBearing: yes
Type - Pset_ProductRequirements - Name: PILOTE; Category: Columns
Type - Pset_QuantityTakeOff - Reference: Hormigón_PI-1/0(?)
Type - Pset_ReinforcementBarPitchOfColumn - Reference: Hormigón_PI-1/0(?)
Material: CONCRETE/28MPa 117
BaseQuantities - GrossVolume: 3.13841 m3
Pset_ColumnCommon - Slope: 0 rad
Pset_QuantityTakeOff - sets with these values: 2
Constraints - Moves With Grids: yes; Moves With Nearby Elements: yes; Room Bounding: yes
Dimensions - Area: 0.282732 m2; Volume: 3.13841 m3
Other - Family: PILOTE 440: PILOTE 440; Family and Type: PILOTE 440: PILOTE 440; Type: PILOTE 440: PILOTE 440; Type Id: PILOTE 440: PILOTE 440
Phasing - Phase Created: New Construction

# IfcColumn: PILOTE, PILOTE 448:PILOTE 448:201513
In: Default
Type - Description: D600; PredefinedType: COLUMN; Classification: A1020110 Piles - CIP (Uniformat)
Type - Graphics - Coarse Scale Fill Color: 0
Type - Identity Data - Assembly Code: A1020110; Assembly Description: Piles - CIP; Type Name: PILOTE 448
Type - Other - Category: Columns; Family Name: PILOTE 448
Type - Pset_ColumnCommon - Reference: Hormigón_PI-1/0(?); IsExternal: no; LoadBearing: yes
Type - Pset_ProductRequirements - Name: PILOTE; Category: Columns
Type - Pset_QuantityTakeOff - Reference: Hormigón_PI-1/0(?)
Type - Pset_ReinforcementBarPitchOfColumn - Reference: Hormigón_PI-1/0(?)
Material: CONCRETE/28MPa 117
BaseQuantities - GrossVolume: 3.13841 m3
Pset_ColumnCommon - Slope: 0 rad
Pset_QuantityTakeOff - sets with these values: 2
Constraints - Moves With Grids: yes; Moves With Nearby Elements: yes; Room Bounding: yes
Dimensions - Area: 0.282732 m2; Volume: 3.13841 m3
Other - Family: PILOTE 448: PILOTE 448; Family and Type: PILOTE 448: PILOTE 448; Type: PILOTE 448: PILOTE 448; Type Id: PILOTE 448: PILOTE 448
Phasing - Phase Created: New Construction

# IfcColumn: PILOTE, PILOTE 456:PILOTE 456:201525
In: Default
Type - Description: D600; PredefinedType: COLUMN; Classification: A1020110 Piles - CIP (Uniformat)
Type - Graphics - Coarse Scale Fill Color: 0
Type - Identity Data - Assembly Code: A1020110; Assembly Description: Piles - CIP; Type Name: PILOTE 456
Type - Other - Category: Columns; Family Name: PILOTE 456
Type - Pset_ColumnCommon - Reference: Hormigón_PI-1/0(?); IsExternal: no; LoadBearing: yes
Type - Pset_ProductRequirements - Name: PILOTE; Category: Columns
Type - Pset_QuantityTakeOff - Reference: Hormigón_PI-1/0(?)
Type - Pset_ReinforcementBarPitchOfColumn - Reference: Hormigón_PI-1/0(?)
Material: CONCRETE/28MPa 117
BaseQuantities - GrossVolume: 3.13841 m3
Pset_ColumnCommon - Slope: 0 rad
Pset_QuantityTakeOff - sets with these values: 2
Constraints - Moves With Grids: yes; Moves With Nearby Elements: yes; Room Bounding: yes
Dimensions - Area: 0.282732 m2; Volume: 3.13841 m3
Other - Family: PILOTE 456: PILOTE 456; Family and Type: PILOTE 456: PILOTE 456; Type: PILOTE 456: PILOTE 456; Type Id: PILOTE 456: PILOTE 456
Phasing - Phase Created: New Construction

# IfcColumn: PILOTE, PILOTE 466:PILOTE 466:201537
In: Default
Type - Description: D600; PredefinedType: COLUMN; Classification: A1020110 Piles - CIP (Uniformat)
Type - Graphics - Coarse Scale Fill Color: 0
Type - Identity Data - Assembly Code: A1020110; Assembly Description: Piles - CIP; Type Name: PILOTE 466
Type - Other - Category: Columns; Family Name: PILOTE 466
Type - Pset_ColumnCommon - Reference: Hormigón_PI-1/0(?); IsExternal: no; LoadBearing: yes
Type - Pset_ProductRequirements - Name: PILOTE; Category: Columns
Type - Pset_QuantityTakeOff - Reference: Hormigón_PI-1/0(?)
Type - Pset_ReinforcementBarPitchOfColumn - Reference: Hormigón_PI-1/0(?)
Material: CONCRETE/28MPa 117
BaseQuantities - GrossVolume: 3.13841 m3
Pset_ColumnCommon - Slope: 0 rad
Pset_QuantityTakeOff - sets with these values: 2
Constraints - Moves With Grids: yes; Moves With Nearby Elements: yes; Room Bounding: yes
Dimensions - Area: 0.282732 m2; Volume: 3.13841 m3
Other - Family: PILOTE 466: PILOTE 466; Family and Type: PILOTE 466: PILOTE 466; Type: PILOTE 466: PILOTE 466; Type Id: PILOTE 466: PILOTE 466
Phasing - Phase Created: New Construction

# IfcColumn: PILOTE, PILOTE 474:PILOTE 474:201549
In: Default
Type - Description: D600; PredefinedType: COLUMN; Classification: A1020110 Piles - CIP (Uniformat)
Type - Graphics - Coarse Scale Fill Color: 0
Type - Identity Data - Assembly Code: A1020110; Assembly Description: Piles - CIP; Type Name: PILOTE 474
Type - Other - Category: Columns; Family Name: PILOTE 474
Type - Pset_ColumnCommon - Reference: Hormigón_PI-1/0(?); IsExternal: no; LoadBearing: yes
Type - Pset_ProductRequirements - Name: PILOTE; Category: Columns
Type - Pset_QuantityTakeOff - Reference: Hormigón_PI-1/0(?)
Type - Pset_ReinforcementBarPitchOfColumn - Reference: Hormigón_PI-1/0(?)
Material: CONCRETE/28MPa 117
BaseQuantities - GrossVolume: 3.13841 m3
Pset_ColumnCommon - Slope: 0 rad
Pset_QuantityTakeOff - sets with these values: 2
Constraints - Moves With Grids: yes; Moves With Nearby Elements: yes; Room Bounding: yes
Dimensions - Area: 0.282732 m2; Volume: 3.13841 m3
Other - Family: PILOTE 474: PILOTE 474; Family and Type: PILOTE 474: PILOTE 474; Type: PILOTE 474: PILOTE 474; Type Id: PILOTE 474: PILOTE 474
Phasing - Phase Created: New Construction

# IfcColumn: PILOTE, PILOTE 482:PILOTE 482:201561
In: Default
Type - Description: D600; PredefinedType: COLUMN; Classification: A1020110 Piles - CIP (Uniformat)
Type - Graphics - Coarse Scale Fill Color: 0
Type - Identity Data - Assembly Code: A1020110; Assembly Description: Piles - CIP; Type Name: PILOTE 482
Type - Other - Category: Columns; Family Name: PILOTE 482
Type - Pset_ColumnCommon - Reference: Hormigón_PI-1/0(?); IsExternal: no; LoadBearing: yes
Type - Pset_ProductRequirements - Name: PILOTE; Category: Columns
Type - Pset_QuantityTakeOff - Reference: Hormigón_PI-1/0(?)
Type - Pset_ReinforcementBarPitchOfColumn - Reference: Hormigón_PI-1/0(?)
Material: CONCRETE/28MPa 117
BaseQuantities - GrossVolume: 3.13841 m3
Pset_ColumnCommon - Slope: 0 rad
Pset_QuantityTakeOff - sets with these values: 2
Constraints - Moves With Grids: yes; Moves With Nearby Elements: yes; Room Bounding: yes
Dimensions - Area: 0.282732 m2; Volume: 3.13841 m3
Other - Family: PILOTE 482: PILOTE 482; Family and Type: PILOTE 482: PILOTE 482; Type: PILOTE 482: PILOTE 482; Type Id: PILOTE 482: PILOTE 482
Phasing - Phase Created: New Construction

# IfcColumn: PILOTE, PILOTE 490:PILOTE 490:201573
In: Default
Type - Description: D600; PredefinedType: COLUMN; Classification: A1020110 Piles - CIP (Uniformat)
Type - Graphics - Coarse Scale Fill Color: 0
Type - Identity Data - Assembly Code: A1020110; Assembly Description: Piles - CIP; Type Name: PILOTE 490
Type - Other - Category: Columns; Family Name: PILOTE 490
Type - Pset_ColumnCommon - Reference: Hormigón_PI-1/0(?); IsExternal: no; LoadBearing: yes
Type - Pset_ProductRequirements - Name: PILOTE; Category: Columns
Type - Pset_QuantityTakeOff - Reference: Hormigón_PI-1/0(?)
Type - Pset_ReinforcementBarPitchOfColumn - Reference: Hormigón_PI-1/0(?)
Material: CONCRETE/28MPa 117
BaseQuantities - GrossVolume: 3.13841 m3
Pset_ColumnCommon - Slope: 0 rad
Pset_QuantityTakeOff - sets with these values: 2
Constraints - Moves With Grids: yes; Moves With Nearby Elements: yes; Room Bounding: yes
Dimensions - Area: 0.282732 m2; Volume: 3.13841 m3
Other - Family: PILOTE 490: PILOTE 490; Family and Type: PILOTE 490: PILOTE 490; Type: PILOTE 490: PILOTE 490; Type Id: PILOTE 490: PILOTE 490
Phasing - Phase Created: New Construction

# IfcColumn: PILOTE, PILOTE 498:PILOTE 498:201585
In: Default
Type - Description: D600; PredefinedType: COLUMN; Classification: A1020110 Piles - CIP (Uniformat)
Type - Graphics - Coarse Scale Fill Color: 0
Type - Identity Data - Assembly Code: A1020110; Assembly Description: Piles - CIP; Type Name: PILOTE 498
Type - Other - Category: Columns; Family Name: PILOTE 498
Type - Pset_ColumnCommon - Reference: Hormigón_PI-1/0(?); IsExternal: no; LoadBearing: yes
Type - Pset_ProductRequirements - Name: PILOTE; Category: Columns
Type - Pset_QuantityTakeOff - Reference: Hormigón_PI-1/0(?)
Type - Pset_ReinforcementBarPitchOfColumn - Reference: Hormigón_PI-1/0(?)
Material: CONCRETE/28MPa 117
BaseQuantities - GrossVolume: 3.13841 m3
Pset_ColumnCommon - Slope: 0 rad
Pset_QuantityTakeOff - sets with these values: 2
Constraints - Moves With Grids: yes; Moves With Nearby Elements: yes; Room Bounding: yes
Dimensions - Area: 0.282732 m2; Volume: 3.13841 m3
Other - Family: PILOTE 498: PILOTE 498; Family and Type: PILOTE 498: PILOTE 498; Type: PILOTE 498: PILOTE 498; Type Id: PILOTE 498: PILOTE 498
Phasing - Phase Created: New Construction

# IfcColumn: PILOTE, PILOTE 506:PILOTE 506:201597
In: Default
Type - Description: D600; PredefinedType: COLUMN; Classification: A1020110 Piles - CIP (Uniformat)
Type - Graphics - Coarse Scale Fill Color: 0
Type - Identity Data - Assembly Code: A1020110; Assembly Description: Piles - CIP; Type Name: PILOTE 506
Type - Other - Category: Columns; Family Name: PILOTE 506
Type - Pset_ColumnCommon - Reference: Hormigón_PI-1/0(?); IsExternal: no; LoadBearing: yes
Type - Pset_ProductRequirements - Name: PILOTE; Category: Columns
Type - Pset_QuantityTakeOff - Reference: Hormigón_PI-1/0(?)
Type - Pset_ReinforcementBarPitchOfColumn - Reference: Hormigón_PI-1/0(?)
Material: CONCRETE/28MPa 117
BaseQuantities - GrossVolume: 3.13841 m3
Pset_ColumnCommon - Slope: 0 rad
Pset_QuantityTakeOff - sets with these values: 2
Constraints - Moves With Grids: yes; Moves With Nearby Elements: yes; Room Bounding: yes
Dimensions - Area: 0.282732 m2; Volume: 3.13841 m3
Other - Family: PILOTE 506: PILOTE 506; Family and Type: PILOTE 506: PILOTE 506; Type: PILOTE 506: PILOTE 506; Type Id: PILOTE 506: PILOTE 506
Phasing - Phase Created: New Construction

# IfcColumn: PILOTE, PILOTE 514:PILOTE 514:201609
In: Default
Type - Description: D600; PredefinedType: COLUMN; Classification: A1020110 Piles - CIP (Uniformat)
Type - Graphics - Coarse Scale Fill Color: 0
Type - Identity Data - Assembly Code: A1020110; Assembly Description: Piles - CIP; Type Name: PILOTE 514
Type - Other - Category: Columns; Family Name: PILOTE 514
Type - Pset_ColumnCommon - Reference: Hormigón_PI-1/0(?); IsExternal: no; LoadBearing: yes
Type - Pset_ProductRequirements - Name: PILOTE; Category: Columns
Type - Pset_QuantityTakeOff - Reference: Hormigón_PI-1/0(?)
Type - Pset_ReinforcementBarPitchOfColumn - Reference: Hormigón_PI-1/0(?)
Material: CONCRETE/28MPa 117
BaseQuantities - GrossVolume: 3.13841 m3
Pset_ColumnCommon - Slope: 0 rad
Pset_QuantityTakeOff - sets with these values: 2
Constraints - Moves With Grids: yes; Moves With Nearby Elements: yes; Room Bounding: yes
Dimensions - Area: 0.282732 m2; Volume: 3.13841 m3
Other - Family: PILOTE 514: PILOTE 514; Family and Type: PILOTE 514: PILOTE 514; Type: PILOTE 514: PILOTE 514; Type Id: PILOTE 514: PILOTE 514
Phasing - Phase Created: New Construction

# IfcColumn: PILOTE, PILOTE 524:PILOTE 524:201621
In: Default
Type - Description: D600; PredefinedType: COLUMN; Classification: A1020110 Piles - CIP (Uniformat)
Type - Graphics - Coarse Scale Fill Color: 0
Type - Identity Data - Assembly Code: A1020110; Assembly Description: Piles - CIP; Type Name: PILOTE 524
Type - Other - Category: Columns; Family Name: PILOTE 524
Type - Pset_ColumnCommon - Reference: Hormigón_PI-1/0(?); IsExternal: no; LoadBearing: yes
Type - Pset_ProductRequirements - Name: PILOTE; Category: Columns
Type - Pset_QuantityTakeOff - Reference: Hormigón_PI-1/0(?)
Type - Pset_ReinforcementBarPitchOfColumn - Reference: Hormigón_PI-1/0(?)
Material: CONCRETE/28MPa 117
BaseQuantities - GrossVolume: 3.13841 m3
Pset_ColumnCommon - Slope: 0 rad
Pset_QuantityTakeOff - sets with these values: 2
Constraints - Moves With Grids: yes; Moves With Nearby Elements: yes; Room Bounding: yes
Dimensions - Area: 0.282732 m2; Volume: 3.13841 m3
Other - Family: PILOTE 524: PILOTE 524; Family and Type: PILOTE 524: PILOTE 524; Type: PILOTE 524: PILOTE 524; Type Id: PILOTE 524: PILOTE 524
Phasing - Phase Created: New Construction

# IfcColumn: PILOTE, PILOTE 532:PILOTE 532:201633
In: Default
Type - Description: D600; PredefinedType: COLUMN; Classification: A1020110 Piles - CIP (Uniformat)
Type - Graphics - Coarse Scale Fill Color: 0
Type - Identity Data - Assembly Code: A1020110; Assembly Description: Piles - CIP; Type Name: PILOTE 532
Type - Other - Category: Columns; Family Name: PILOTE 532
Type - Pset_ColumnCommon - Reference: Hormigón_PI-1/0(?); IsExternal: no; LoadBearing: yes
Type - Pset_ProductRequirements - Name: PILOTE; Category: Columns
Type - Pset_QuantityTakeOff - Reference: Hormigón_PI-1/0(?)
Type - Pset_ReinforcementBarPitchOfColumn - Reference: Hormigón_PI-1/0(?)
Material: CONCRETE/28MPa 117
BaseQuantities - GrossVolume: 3.13841 m3
Pset_ColumnCommon - Slope: 0 rad
Pset_QuantityTakeOff - sets with these values: 2
Constraints - Moves With Grids: yes; Moves With Nearby Elements: yes; Room Bounding: yes
Dimensions - Area: 0.282732 m2; Volume: 3.13841 m3
Other - Family: PILOTE 532: PILOTE 532; Family and Type: PILOTE 532: PILOTE 532; Type: PILOTE 532: PILOTE 532; Type Id: PILOTE 532: PILOTE 532
Phasing - Phase Created: New Construction

# IfcColumn: PILOTE, PILOTE 540:PILOTE 540:201645
In: Default
Type - Description: D600; PredefinedType: COLUMN; Classification: A1020110 Piles - CIP (Uniformat)
Type - Graphics - Coarse Scale Fill Color: 0
Type - Identity Data - Assembly Code: A1020110; Assembly Description: Piles - CIP; Type Name: PILOTE 540
Type - Other - Category: Columns; Family Name: PILOTE 540
Type - Pset_ColumnCommon - Reference: Hormigón_PI-1/0(?); IsExternal: no; LoadBearing: yes
Type - Pset_ProductRequirements - Name: PILOTE; Category: Columns
Type - Pset_QuantityTakeOff - Reference: Hormigón_PI-1/0(?)
Type - Pset_ReinforcementBarPitchOfColumn - Reference: Hormigón_PI-1/0(?)
Material: CONCRETE/28MPa 117
BaseQuantities - GrossVolume: 3.13841 m3
Pset_ColumnCommon - Slope: 0 rad
Pset_QuantityTakeOff - sets with these values: 2
Constraints - Moves With Grids: yes; Moves With Nearby Elements: yes; Room Bounding: yes
Dimensions - Area: 0.282732 m2; Volume: 3.13841 m3
Other - Family: PILOTE 540: PILOTE 540; Family and Type: PILOTE 540: PILOTE 540; Type: PILOTE 540: PILOTE 540; Type Id: PILOTE 540: PILOTE 540
Phasing - Phase Created: New Construction

# IfcColumn: PILOTE, PILOTE 550:PILOTE 550:201657
In: Default
Type - Description: D600; PredefinedType: COLUMN; Classification: A1020110 Piles - CIP (Uniformat)
Type - Graphics - Coarse Scale Fill Color: 0
Type - Identity Data - Assembly Code: A1020110; Assembly Description: Piles - CIP; Type Name: PILOTE 550
Type - Other - Category: Columns; Family Name: PILOTE 550
Type - Pset_ColumnCommon - Reference: Hormigón_PI-1/0(?); IsExternal: no; LoadBearing: yes
Type - Pset_ProductRequirements - Name: PILOTE; Category: Columns
Type - Pset_QuantityTakeOff - Reference: Hormigón_PI-1/0(?)
Type - Pset_ReinforcementBarPitchOfColumn - Reference: Hormigón_PI-1/0(?)
Material: CONCRETE/28MPa 117
BaseQuantities - GrossVolume: 3.13841 m3
Pset_ColumnCommon - Slope: 0 rad
Pset_QuantityTakeOff - sets with these values: 2
Constraints - Moves With Grids: yes; Moves With Nearby Elements: yes; Room Bounding: yes
Dimensions - Area: 0.282732 m2; Volume: 3.13841 m3
Other - Family: PILOTE 550: PILOTE 550; Family and Type: PILOTE 550: PILOTE 550; Type: PILOTE 550: PILOTE 550; Type Id: PILOTE 550: PILOTE 550
Phasing - Phase Created: New Construction

# IfcColumn: PILOTE, PILOTE 558:PILOTE 558:201669
In: Default
Type - Description: D600; PredefinedType: COLUMN; Classification: A1020110 Piles - CIP (Uniformat)
Type - Graphics - Coarse Scale Fill Color: 0
Type - Identity Data - Assembly Code: A1020110; Assembly Description: Piles - CIP; Type Name: PILOTE 558
Type - Other - Category: Columns; Family Name: PILOTE 558
Type - Pset_ColumnCommon - Reference: Hormigón_PI-1/0(?); IsExternal: no; LoadBearing: yes
Type - Pset_ProductRequirements - Name: PILOTE; Category: Columns
Type - Pset_QuantityTakeOff - Reference: Hormigón_PI-1/0(?)
Type - Pset_ReinforcementBarPitchOfColumn - Reference: Hormigón_PI-1/0(?)
Material: CONCRETE/28MPa 117
BaseQuantities - GrossVolume: 3.13841 m3
Pset_ColumnCommon - Slope: 0 rad
Pset_QuantityTakeOff - sets with these values: 2
Constraints - Moves With Grids: yes; Moves With Nearby Elements: yes; Room Bounding: yes
Dimensions - Area: 0.282732 m2; Volume: 3.13841 m3
Other - Family: PILOTE 558: PILOTE 558; Family and Type: PILOTE 558: PILOTE 558; Type: PILOTE 558: PILOTE 558; Type Id: PILOTE 558: PILOTE 558
Phasing - Phase Created: New Construction

# IfcColumn: PILOTE, PILOTE 566:PILOTE 566:201681
In: Default
Type - Description: D600; PredefinedType: COLUMN; Classification: A1020110 Piles - CIP (Uniformat)
Type - Graphics - Coarse Scale Fill Color: 0
Type - Identity Data - Assembly Code: A1020110; Assembly Description: Piles - CIP; Type Name: PILOTE 566
Type - Other - Category: Columns; Family Name: PILOTE 566
Type - Pset_ColumnCommon - Reference: Hormigón_PI-1/0(?); IsExternal: no; LoadBearing: yes
Type - Pset_ProductRequirements - Name: PILOTE; Category: Columns
Type - Pset_QuantityTakeOff - Reference: Hormigón_PI-1/0(?)
Type - Pset_ReinforcementBarPitchOfColumn - Reference: Hormigón_PI-1/0(?)
Material: CONCRETE/28MPa 117
BaseQuantities - GrossVolume: 3.13841 m3
Pset_ColumnCommon - Slope: 0 rad
Pset_QuantityTakeOff - sets with these values: 2
Constraints - Moves With Grids: yes; Moves With Nearby Elements: yes; Room Bounding: yes
Dimensions - Area: 0.282732 m2; Volume: 3.13841 m3
Other - Family: PILOTE 566: PILOTE 566; Family and Type: PILOTE 566: PILOTE 566; Type: PILOTE 566: PILOTE 566; Type Id: PILOTE 566: PILOTE 566
Phasing - Phase Created: New Construction

# IfcColumn: PILOTE, PILOTE 574:PILOTE 574:201693
In: Default
Type - Description: D600; PredefinedType: COLUMN; Classification: A1020110 Piles - CIP (Uniformat)
Type - Graphics - Coarse Scale Fill Color: 0
Type - Identity Data - Assembly Code: A1020110; Assembly Description: Piles - CIP; Type Name: PILOTE 574
Type - Other - Category: Columns; Family Name: PILOTE 574
Type - Pset_ColumnCommon - Reference: Hormigón_PI-1/0(?); IsExternal: no; LoadBearing: yes
Type - Pset_ProductRequirements - Name: PILOTE; Category: Columns
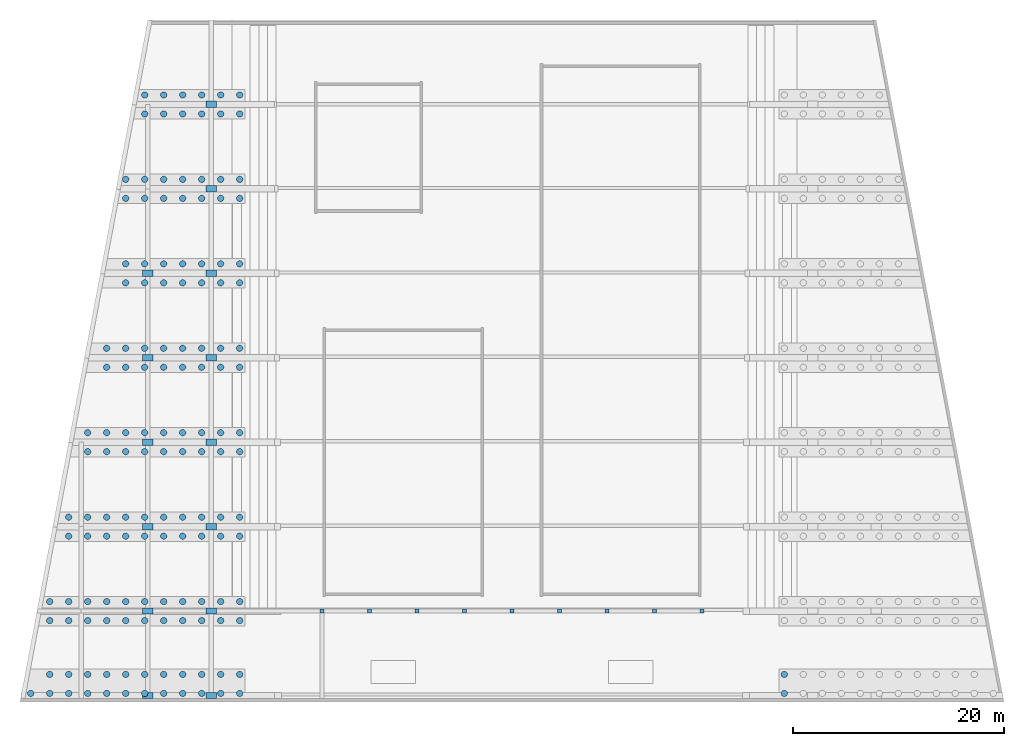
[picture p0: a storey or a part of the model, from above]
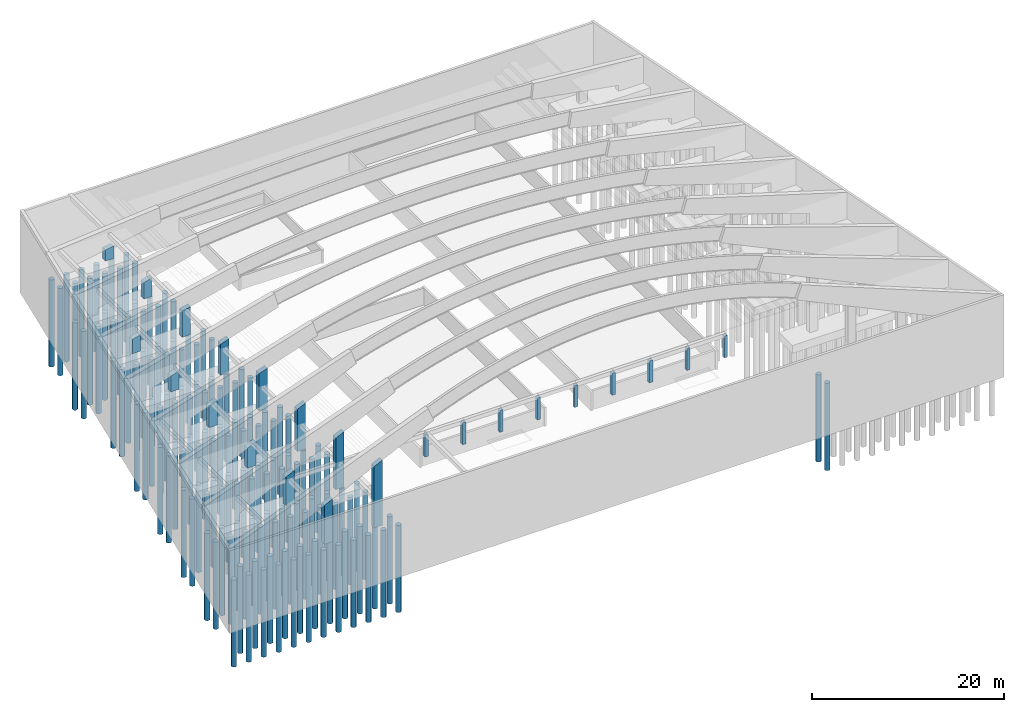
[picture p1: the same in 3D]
Properties of the parts of a building model (IFC2X3), part 4 of 5

# IfcColumn: PILOTE, PILOTE 574:PILOTE 574:201693
Type - Pset_QuantityTakeOff - Reference: Hormigón_PI-1/0(?)
Type - Pset_ReinforcementBarPitchOfColumn - Reference: Hormigón_PI-1/0(?)
Material: CONCRETE/28MPa 117
BaseQuantities - GrossVolume: 3.13841 m3
Pset_ColumnCommon - Slope: 0 rad
Pset_QuantityTakeOff - sets with these values: 2
Constraints - Moves With Grids: yes; Moves With Nearby Elements: yes; Room Bounding: yes
Dimensions - Area: 0.282732 m2; Volume: 3.13841 m3
Other - Family: PILOTE 574: PILOTE 574; Family and Type: PILOTE 574: PILOTE 574; Type: PILOTE 574: PILOTE 574; Type Id: PILOTE 574: PILOTE 574
Phasing - Phase Created: New Construction

# IfcColumn: PILOTE, PILOTE 584:PILOTE 584:201705
In: Default
Type - Description: D600; PredefinedType: COLUMN; Classification: A1020110 Piles - CIP (Uniformat)
Type - Graphics - Coarse Scale Fill Color: 0
Type - Identity Data - Assembly Code: A1020110; Assembly Description: Piles - CIP; Type Name: PILOTE 584
Type - Other - Category: Columns; Family Name: PILOTE 584
Type - Pset_ColumnCommon - Reference: Hormigón_PI-1/0(?); IsExternal: no; LoadBearing: yes
Type - Pset_ProductRequirements - Name: PILOTE; Category: Columns
Type - Pset_QuantityTakeOff - Reference: Hormigón_PI-1/0(?)
Type - Pset_ReinforcementBarPitchOfColumn - Reference: Hormigón_PI-1/0(?)
Material: CONCRETE/28MPa 117
BaseQuantities - GrossVolume: 3.13841 m3
Pset_ColumnCommon - Slope: 0 rad
Pset_QuantityTakeOff - sets with these values: 2
Constraints - Moves With Grids: yes; Moves With Nearby Elements: yes; Room Bounding: yes
Dimensions - Area: 0.282732 m2; Volume: 3.13841 m3
Other - Family: PILOTE 584: PILOTE 584; Family and Type: PILOTE 584: PILOTE 584; Type: PILOTE 584: PILOTE 584; Type Id: PILOTE 584: PILOTE 584
Phasing - Phase Created: New Construction

# IfcColumn: PILOTE, PILOTE 592:PILOTE 592:201717
In: Default
Type - Description: D600; PredefinedType: COLUMN; Classification: A1020110 Piles - CIP (Uniformat)
Type - Graphics - Coarse Scale Fill Color: 0
Type - Identity Data - Assembly Code: A1020110; Assembly Description: Piles - CIP; Type Name: PILOTE 592
Type - Other - Category: Columns; Family Name: PILOTE 592
Type - Pset_ColumnCommon - Reference: Hormigón_PI-1/0(?); IsExternal: no; LoadBearing: yes
Type - Pset_ProductRequirements - Name: PILOTE; Category: Columns
Type - Pset_QuantityTakeOff - Reference: Hormigón_PI-1/0(?)
Type - Pset_ReinforcementBarPitchOfColumn - Reference: Hormigón_PI-1/0(?)
Material: CONCRETE/28MPa 117
BaseQuantities - GrossVolume: 3.13841 m3
Pset_ColumnCommon - Slope: 0 rad
Pset_QuantityTakeOff - sets with these values: 2
Constraints - Moves With Grids: yes; Moves With Nearby Elements: yes; Room Bounding: yes
Dimensions - Area: 0.282732 m2; Volume: 3.13841 m3
Other - Family: PILOTE 592: PILOTE 592; Family and Type: PILOTE 592: PILOTE 592; Type: PILOTE 592: PILOTE 592; Type Id: PILOTE 592: PILOTE 592
Phasing - Phase Created: New Construction

# IfcColumn: PILOTE, PILOTE 600:PILOTE 600:201729
In: Default
Type - Description: D600; PredefinedType: COLUMN; Classification: A1020110 Piles - CIP (Uniformat)
Type - Graphics - Coarse Scale Fill Color: 0
Type - Identity Data - Assembly Code: A1020110; Assembly Description: Piles - CIP; Type Name: PILOTE 600
Type - Other - Category: Columns; Family Name: PILOTE 600
Type - Pset_ColumnCommon - Reference: Hormigón_PI-1/0(?); IsExternal: no; LoadBearing: yes
Type - Pset_ProductRequirements - Name: PILOTE; Category: Columns
Type - Pset_QuantityTakeOff - Reference: Hormigón_PI-1/0(?)
Type - Pset_ReinforcementBarPitchOfColumn - Reference: Hormigón_PI-1/0(?)
Material: CONCRETE/28MPa 117
BaseQuantities - GrossVolume: 3.13841 m3
Pset_ColumnCommon - Slope: 0 rad
Pset_QuantityTakeOff - sets with these values: 2
Constraints - Moves With Grids: yes; Moves With Nearby Elements: yes; Room Bounding: yes
Dimensions - Area: 0.282732 m2; Volume: 3.13841 m3
Other - Family: PILOTE 600: PILOTE 600; Family and Type: PILOTE 600: PILOTE 600; Type: PILOTE 600: PILOTE 600; Type Id: PILOTE 600: PILOTE 600
Phasing - Phase Created: New Construction

# IfcColumn: PILOTE, PILOTE 608:PILOTE 608:201741
In: Default
Type - Description: D600; PredefinedType: COLUMN; Classification: A1020110 Piles - CIP (Uniformat)
Type - Graphics - Coarse Scale Fill Color: 0
Type - Identity Data - Assembly Code: A1020110; Assembly Description: Piles - CIP; Type Name: PILOTE 608
Type - Other - Category: Columns; Family Name: PILOTE 608
Type - Pset_ColumnCommon - Reference: Hormigón_PI-1/0(?); IsExternal: no; LoadBearing: yes
Type - Pset_ProductRequirements - Name: PILOTE; Category: Columns
Type - Pset_QuantityTakeOff - Reference: Hormigón_PI-1/0(?)
Type - Pset_ReinforcementBarPitchOfColumn - Reference: Hormigón_PI-1/0(?)
Material: CONCRETE/28MPa 117
BaseQuantities - GrossVolume: 3.13841 m3
Pset_ColumnCommon - Slope: 0 rad
Pset_QuantityTakeOff - sets with these values: 2
Constraints - Moves With Grids: yes; Moves With Nearby Elements: yes; Room Bounding: yes
Dimensions - Area: 0.282732 m2; Volume: 3.13841 m3
Other - Family: PILOTE 608: PILOTE 608; Family and Type: PILOTE 608: PILOTE 608; Type: PILOTE 608: PILOTE 608; Type Id: PILOTE 608: PILOTE 608
Phasing - Phase Created: New Construction

# IfcColumn: PILOTE, PILOTE 616:PILOTE 616:201753
In: Default
Type - Description: D600; PredefinedType: COLUMN; Classification: A1020110 Piles - CIP (Uniformat)
Type - Graphics - Coarse Scale Fill Color: 0
Type - Identity Data - Assembly Code: A1020110; Assembly Description: Piles - CIP; Type Name: PILOTE 616
Type - Other - Category: Columns; Family Name: PILOTE 616
Type - Pset_ColumnCommon - Reference: Hormigón_PI-1/0(?); IsExternal: no; LoadBearing: yes
Type - Pset_ProductRequirements - Name: PILOTE; Category: Columns
Type - Pset_QuantityTakeOff - Reference: Hormigón_PI-1/0(?)
Type - Pset_ReinforcementBarPitchOfColumn - Reference: Hormigón_PI-1/0(?)
Material: CONCRETE/28MPa 117
BaseQuantities - GrossVolume: 3.13841 m3
Pset_ColumnCommon - Slope: 0 rad
Pset_QuantityTakeOff - sets with these values: 2
Constraints - Moves With Grids: yes; Moves With Nearby Elements: yes; Room Bounding: yes
Dimensions - Area: 0.282732 m2; Volume: 3.13841 m3
Other - Family: PILOTE 616: PILOTE 616; Family and Type: PILOTE 616: PILOTE 616; Type: PILOTE 616: PILOTE 616; Type Id: PILOTE 616: PILOTE 616
Phasing - Phase Created: New Construction

# IfcColumn: PILOTE, PILOTE 624:PILOTE 624:201765
In: Default
Type - Description: D600; PredefinedType: COLUMN; Classification: A1020110 Piles - CIP (Uniformat)
Type - Graphics - Coarse Scale Fill Color: 0
Type - Identity Data - Assembly Code: A1020110; Assembly Description: Piles - CIP; Type Name: PILOTE 624
Type - Other - Category: Columns; Family Name: PILOTE 624
Type - Pset_ColumnCommon - Reference: Hormigón_PI-1/0(?); IsExternal: no; LoadBearing: yes
Type - Pset_ProductRequirements - Name: PILOTE; Category: Columns
Type - Pset_QuantityTakeOff - Reference: Hormigón_PI-1/0(?)
Type - Pset_ReinforcementBarPitchOfColumn - Reference: Hormigón_PI-1/0(?)
Material: CONCRETE/28MPa 117
BaseQuantities - GrossVolume: 3.13841 m3
Pset_ColumnCommon - Slope: 0 rad
Pset_QuantityTakeOff - sets with these values: 2
Constraints - Moves With Grids: yes; Moves With Nearby Elements: yes; Room Bounding: yes
Dimensions - Area: 0.282732 m2; Volume: 3.13841 m3
Other - Family: PILOTE 624: PILOTE 624; Family and Type: PILOTE 624: PILOTE 624; Type: PILOTE 624: PILOTE 624; Type Id: PILOTE 624: PILOTE 624
Phasing - Phase Created: New Construction

# IfcColumn: PILOTE, PILOTE 632:PILOTE 632:201777
In: Default
Type - Description: D600; PredefinedType: COLUMN; Classification: A1020110 Piles - CIP (Uniformat)
Type - Graphics - Coarse Scale Fill Color: 0
Type - Identity Data - Assembly Code: A1020110; Assembly Description: Piles - CIP; Type Name: PILOTE 632
Type - Other - Category: Columns; Family Name: PILOTE 632
Type - Pset_ColumnCommon - Reference: Hormigón_PI-1/0(?); IsExternal: no; LoadBearing: yes
Type - Pset_ProductRequirements - Name: PILOTE; Category: Columns
Type - Pset_QuantityTakeOff - Reference: Hormigón_PI-1/0(?)
Type - Pset_ReinforcementBarPitchOfColumn - Reference: Hormigón_PI-1/0(?)
Material: CONCRETE/28MPa 117
BaseQuantities - GrossVolume: 3.13841 m3
Pset_ColumnCommon - Slope: 0 rad
Pset_QuantityTakeOff - sets with these values: 2
Constraints - Moves With Grids: yes; Moves With Nearby Elements: yes; Room Bounding: yes
Dimensions - Area: 0.282732 m2; Volume: 3.13841 m3
Other - Family: PILOTE 632: PILOTE 632; Family and Type: PILOTE 632: PILOTE 632; Type: PILOTE 632: PILOTE 632; Type Id: PILOTE 632: PILOTE 632
Phasing - Phase Created: New Construction

# IfcColumn: PILOTE, PILOTE 642:PILOTE 642:201789
In: Default
Type - Description: D600; PredefinedType: COLUMN; Classification: A1020110 Piles - CIP (Uniformat)
Type - Graphics - Coarse Scale Fill Color: 0
Type - Identity Data - Assembly Code: A1020110; Assembly Description: Piles - CIP; Type Name: PILOTE 642
Type - Other - Category: Columns; Family Name: PILOTE 642
Type - Pset_ColumnCommon - Reference: Hormigón_PI-1/0(?); IsExternal: no; LoadBearing: yes
Type - Pset_ProductRequirements - Name: PILOTE; Category: Columns
Type - Pset_QuantityTakeOff - Reference: Hormigón_PI-1/0(?)
Type - Pset_ReinforcementBarPitchOfColumn - Reference: Hormigón_PI-1/0(?)
Material: CONCRETE/28MPa 117
BaseQuantities - GrossVolume: 3.13841 m3
Pset_ColumnCommon - Slope: 0 rad
Pset_QuantityTakeOff - sets with these values: 2
Constraints - Moves With Grids: yes; Moves With Nearby Elements: yes; Room Bounding: yes
Dimensions - Area: 0.282732 m2; Volume: 3.13841 m3
Other - Family: PILOTE 642: PILOTE 642; Family and Type: PILOTE 642: PILOTE 642; Type: PILOTE 642: PILOTE 642; Type Id: PILOTE 642: PILOTE 642
Phasing - Phase Created: New Construction

# IfcColumn: PILOTE, PILOTE 650:PILOTE 650:201801
In: Default
Type - Description: D600; PredefinedType: COLUMN; Classification: A1020110 Piles - CIP (Uniformat)
Type - Graphics - Coarse Scale Fill Color: 0
Type - Identity Data - Assembly Code: A1020110; Assembly Description: Piles - CIP; Type Name: PILOTE 650
Type - Other - Category: Columns; Family Name: PILOTE 650
Type - Pset_ColumnCommon - Reference: Hormigón_PI-1/0(?); IsExternal: no; LoadBearing: yes
Type - Pset_ProductRequirements - Name: PILOTE; Category: Columns
Type - Pset_QuantityTakeOff - Reference: Hormigón_PI-1/0(?)
Type - Pset_ReinforcementBarPitchOfColumn - Reference: Hormigón_PI-1/0(?)
Material: CONCRETE/28MPa 117
BaseQuantities - GrossVolume: 3.13841 m3
Pset_ColumnCommon - Slope: 0 rad
Pset_QuantityTakeOff - sets with these values: 2
Constraints - Moves With Grids: yes; Moves With Nearby Elements: yes; Room Bounding: yes
Dimensions - Area: 0.282732 m2; Volume: 3.13841 m3
Other - Family: PILOTE 650: PILOTE 650; Family and Type: PILOTE 650: PILOTE 650; Type: PILOTE 650: PILOTE 650; Type Id: PILOTE 650: PILOTE 650
Phasing - Phase Created: New Construction

# IfcColumn: PILOTE, PILOTE 658:PILOTE 658:201813
In: Default
Type - Description: D600; PredefinedType: COLUMN; Classification: A1020110 Piles - CIP (Uniformat)
Type - Graphics - Coarse Scale Fill Color: 0
Type - Identity Data - Assembly Code: A1020110; Assembly Description: Piles - CIP; Type Name: PILOTE 658
Type - Other - Category: Columns; Family Name: PILOTE 658
Type - Pset_ColumnCommon - Reference: Hormigón_PI-1/0(?); IsExternal: no; LoadBearing: yes
Type - Pset_ProductRequirements - Name: PILOTE; Category: Columns
Type - Pset_QuantityTakeOff - Reference: Hormigón_PI-1/0(?)
Type - Pset_ReinforcementBarPitchOfColumn - Reference: Hormigón_PI-1/0(?)
Material: CONCRETE/28MPa 117
BaseQuantities - GrossVolume: 3.13841 m3
Pset_ColumnCommon - Slope: 0 rad
Pset_QuantityTakeOff - sets with these values: 2
Constraints - Moves With Grids: yes; Moves With Nearby Elements: yes; Room Bounding: yes
Dimensions - Area: 0.282732 m2; Volume: 3.13841 m3
Other - Family: PILOTE 658: PILOTE 658; Family and Type: PILOTE 658: PILOTE 658; Type: PILOTE 658: PILOTE 658; Type Id: PILOTE 658: PILOTE 658
Phasing - Phase Created: New Construction

# IfcColumn: PILOTE, PILOTE 666:PILOTE 666:201825
In: Default
Type - Description: D600; PredefinedType: COLUMN; Classification: A1020110 Piles - CIP (Uniformat)
Type - Graphics - Coarse Scale Fill Color: 0
Type - Identity Data - Assembly Code: A1020110; Assembly Description: Piles - CIP; Type Name: PILOTE 666
Type - Other - Category: Columns; Family Name: PILOTE 666
Type - Pset_ColumnCommon - Reference: Hormigón_PI-1/0(?); IsExternal: no; LoadBearing: yes
Type - Pset_ProductRequirements - Name: PILOTE; Category: Columns
Type - Pset_QuantityTakeOff - Reference: Hormigón_PI-1/0(?)
Type - Pset_ReinforcementBarPitchOfColumn - Reference: Hormigón_PI-1/0(?)
Material: CONCRETE/28MPa 117
BaseQuantities - GrossVolume: 3.13841 m3
Pset_ColumnCommon - Slope: 0 rad
Pset_QuantityTakeOff - sets with these values: 2
Constraints - Moves With Grids: yes; Moves With Nearby Elements: yes; Room Bounding: yes
Dimensions - Area: 0.282732 m2; Volume: 3.13841 m3
Other - Family: PILOTE 666: PILOTE 666; Family and Type: PILOTE 666: PILOTE 666; Type: PILOTE 666: PILOTE 666; Type Id: PILOTE 666: PILOTE 666
Phasing - Phase Created: New Construction

# IfcColumn: PILOTE, PILOTE 674:PILOTE 674:201837
In: Default
Type - Description: D600; PredefinedType: COLUMN; Classification: A1020110 Piles - CIP (Uniformat)
Type - Graphics - Coarse Scale Fill Color: 0
Type - Identity Data - Assembly Code: A1020110; Assembly Description: Piles - CIP; Type Name: PILOTE 674
Type - Other - Category: Columns; Family Name: PILOTE 674
Type - Pset_ColumnCommon - Reference: Hormigón_PI-1/0(?); IsExternal: no; LoadBearing: yes
Type - Pset_ProductRequirements - Name: PILOTE; Category: Columns
Type - Pset_QuantityTakeOff - Reference: Hormigón_PI-1/0(?)
Type - Pset_ReinforcementBarPitchOfColumn - Reference: Hormigón_PI-1/0(?)
Material: CONCRETE/28MPa 117
BaseQuantities - GrossVolume: 3.13841 m3
Pset_ColumnCommon - Slope: 0 rad
Pset_QuantityTakeOff - sets with these values: 2
Constraints - Moves With Grids: yes; Moves With Nearby Elements: yes; Room Bounding: yes
Dimensions - Area: 0.282732 m2; Volume: 3.13841 m3
Other - Family: PILOTE 674: PILOTE 674; Family and Type: PILOTE 674: PILOTE 674; Type: PILOTE 674: PILOTE 674; Type Id: PILOTE 674: PILOTE 674
Phasing - Phase Created: New Construction

# IfcColumn: PILOTE, PILOTE 682:PILOTE 682:201849
In: Default
Type - Description: D600; PredefinedType: COLUMN; Classification: A1020110 Piles - CIP (Uniformat)
Type - Graphics - Coarse Scale Fill Color: 0
Type - Identity Data - Assembly Code: A1020110; Assembly Description: Piles - CIP; Type Name: PILOTE 682
Type - Other - Category: Columns; Family Name: PILOTE 682
Type - Pset_ColumnCommon - Reference: Hormigón_PI-1/0(?); IsExternal: no; LoadBearing: yes
Type - Pset_ProductRequirements - Name: PILOTE; Category: Columns
Type - Pset_QuantityTakeOff - Reference: Hormigón_PI-1/0(?)
Type - Pset_ReinforcementBarPitchOfColumn - Reference: Hormigón_PI-1/0(?)
Material: CONCRETE/28MPa 117
BaseQuantities - GrossVolume: 3.13841 m3
Pset_ColumnCommon - Slope: 0 rad
Pset_QuantityTakeOff - sets with these values: 2
Constraints - Moves With Grids: yes; Moves With Nearby Elements: yes; Room Bounding: yes
Dimensions - Area: 0.282732 m2; Volume: 3.13841 m3
Other - Family: PILOTE 682: PILOTE 682; Family and Type: PILOTE 682: PILOTE 682; Type: PILOTE 682: PILOTE 682; Type Id: PILOTE 682: PILOTE 682
Phasing - Phase Created: New Construction

# IfcColumn: PILOTE, PILOTE 690:PILOTE 690:201861
In: Default
Type - Description: D600; PredefinedType: COLUMN; Classification: A1020110 Piles - CIP (Uniformat)
Type - Graphics - Coarse Scale Fill Color: 0
Type - Identity Data - Assembly Code: A1020110; Assembly Description: Piles - CIP; Type Name: PILOTE 690
Type - Other - Category: Columns; Family Name: PILOTE 690
Type - Pset_ColumnCommon - Reference: Hormigón_PI-1/0(?); IsExternal: no; LoadBearing: yes
Type - Pset_ProductRequirements - Name: PILOTE; Category: Columns
Type - Pset_QuantityTakeOff - Reference: Hormigón_PI-1/0(?)
Type - Pset_ReinforcementBarPitchOfColumn - Reference: Hormigón_PI-1/0(?)
Material: CONCRETE/28MPa 117
BaseQuantities - GrossVolume: 3.13841 m3
Pset_ColumnCommon - Slope: 0 rad
Pset_QuantityTakeOff - sets with these values: 2
Constraints - Moves With Grids: yes; Moves With Nearby Elements: yes; Room Bounding: yes
Dimensions - Area: 0.282732 m2; Volume: 3.13841 m3
Other - Family: PILOTE 690: PILOTE 690; Family and Type: PILOTE 690: PILOTE 690; Type: PILOTE 690: PILOTE 690; Type Id: PILOTE 690: PILOTE 690
Phasing - Phase Created: New Construction

# IfcColumn: PILOTE, PILOTE 698:PILOTE 698:201873
In: Default
Type - Description: D600; PredefinedType: COLUMN; Classification: A1020110 Piles - CIP (Uniformat)
Type - Graphics - Coarse Scale Fill Color: 0
Type - Identity Data - Assembly Code: A1020110; Assembly Description: Piles - CIP; Type Name: PILOTE 698
Type - Other - Category: Columns; Family Name: PILOTE 698
Type - Pset_ColumnCommon - Reference: Hormigón_PI-1/0(?); IsExternal: no; LoadBearing: yes
Type - Pset_ProductRequirements - Name: PILOTE; Category: Columns
Type - Pset_QuantityTakeOff - Reference: Hormigón_PI-1/0(?)
Type - Pset_ReinforcementBarPitchOfColumn - Reference: Hormigón_PI-1/0(?)
Material: CONCRETE/28MPa 117
BaseQuantities - GrossVolume: 3.13841 m3
Pset_ColumnCommon - Slope: 0 rad
Pset_QuantityTakeOff - sets with these values: 2
Constraints - Moves With Grids: yes; Moves With Nearby Elements: yes; Room Bounding: yes
Dimensions - Area: 0.282732 m2; Volume: 3.13841 m3
Other - Family: PILOTE 698: PILOTE 698; Family and Type: PILOTE 698: PILOTE 698; Type: PILOTE 698: PILOTE 698; Type Id: PILOTE 698: PILOTE 698
Phasing - Phase Created: New Construction

# IfcColumn: PILOTE, PILOTE 706:PILOTE 706:201885
In: Default
Type - Description: D600; PredefinedType: COLUMN; Classification: A1020110 Piles - CIP (Uniformat)
Type - Graphics - Coarse Scale Fill Color: 0
Type - Identity Data - Assembly Code: A1020110; Assembly Description: Piles - CIP; Type Name: PILOTE 706
Type - Other - Category: Columns; Family Name: PILOTE 706
Type - Pset_ColumnCommon - Reference: Hormigón_PI-1/0(?); IsExternal: no; LoadBearing: yes
Type - Pset_ProductRequirements - Name: PILOTE; Category: Columns
Type - Pset_QuantityTakeOff - Reference: Hormigón_PI-1/0(?)
Type - Pset_ReinforcementBarPitchOfColumn - Reference: Hormigón_PI-1/0(?)
Material: CONCRETE/28MPa 117
BaseQuantities - GrossVolume: 3.13841 m3
Pset_ColumnCommon - Slope: 0 rad
Pset_QuantityTakeOff - sets with these values: 2
Constraints - Moves With Grids: yes; Moves With Nearby Elements: yes; Room Bounding: yes
Dimensions - Area: 0.282732 m2; Volume: 3.13841 m3
Other - Family: PILOTE 706: PILOTE 706; Family and Type: PILOTE 706: PILOTE 706; Type: PILOTE 706: PILOTE 706; Type Id: PILOTE 706: PILOTE 706
Phasing - Phase Created: New Construction

# IfcColumn: PILOTE, PILOTE 714:PILOTE 714:201897
In: Default
Type - Description: D600; PredefinedType: COLUMN; Classification: A1020110 Piles - CIP (Uniformat)
Type - Graphics - Coarse Scale Fill Color: 0
Type - Identity Data - Assembly Code: A1020110; Assembly Description: Piles - CIP; Type Name: PILOTE 714
Type - Other - Category: Columns; Family Name: PILOTE 714
Type - Pset_ColumnCommon - Reference: Hormigón_PI-1/0(?); IsExternal: no; LoadBearing: yes
Type - Pset_ProductRequirements - Name: PILOTE; Category: Columns
Type - Pset_QuantityTakeOff - Reference: Hormigón_PI-1/0(?)
Type - Pset_ReinforcementBarPitchOfColumn - Reference: Hormigón_PI-1/0(?)
Material: CONCRETE/28MPa 117
BaseQuantities - GrossVolume: 3.13841 m3
Pset_ColumnCommon - Slope: 0 rad
Pset_QuantityTakeOff - sets with these values: 2
Constraints - Moves With Grids: yes; Moves With Nearby Elements: yes; Room Bounding: yes
Dimensions - Area: 0.282732 m2; Volume: 3.13841 m3
Other - Family: PILOTE 714: PILOTE 714; Family and Type: PILOTE 714: PILOTE 714; Type: PILOTE 714: PILOTE 714; Type Id: PILOTE 714: PILOTE 714
Phasing - Phase Created: New Construction

# IfcColumn: PILOTE, PILOTE 722:PILOTE 722:201909
In: Default
Type - Description: D600; PredefinedType: COLUMN; Classification: A1020110 Piles - CIP (Uniformat)
Type - Graphics - Coarse Scale Fill Color: 0
Type - Identity Data - Assembly Code: A1020110; Assembly Description: Piles - CIP; Type Name: PILOTE 722
Type - Other - Category: Columns; Family Name: PILOTE 722
Type - Pset_ColumnCommon - Reference: Hormigón_PI-1/0(?); IsExternal: no; LoadBearing: yes
Type - Pset_ProductRequirements - Name: PILOTE; Category: Columns
Type - Pset_QuantityTakeOff - Reference: Hormigón_PI-1/0(?)
Type - Pset_ReinforcementBarPitchOfColumn - Reference: Hormigón_PI-1/0(?)
Material: CONCRETE/28MPa 117
BaseQuantities - GrossVolume: 3.13841 m3
Pset_ColumnCommon - Slope: 0 rad
Pset_QuantityTakeOff - sets with these values: 2
Constraints - Moves With Grids: yes; Moves With Nearby Elements: yes; Room Bounding: yes
Dimensions - Area: 0.282732 m2; Volume: 3.13841 m3
Other - Family: PILOTE 722: PILOTE 722; Family and Type: PILOTE 722: PILOTE 722; Type: PILOTE 722: PILOTE 722; Type Id: PILOTE 722: PILOTE 722
Phasing - Phase Created: New Construction

# IfcColumn: PILOTE, PILOTE 730:PILOTE 730:201921
In: Default
Type - Description: D600; PredefinedType: COLUMN; Classification: A1020110 Piles - CIP (Uniformat)
Type - Graphics - Coarse Scale Fill Color: 0
Type - Identity Data - Assembly Code: A1020110; Assembly Description: Piles - CIP; Type Name: PILOTE 730
Type - Other - Category: Columns; Family Name: PILOTE 730
Type - Pset_ColumnCommon - Reference: Hormigón_PI-1/0(?); IsExternal: no; LoadBearing: yes
Type - Pset_ProductRequirements - Name: PILOTE; Category: Columns
Type - Pset_QuantityTakeOff - Reference: Hormigón_PI-1/0(?)
Type - Pset_ReinforcementBarPitchOfColumn - Reference: Hormigón_PI-1/0(?)
Material: CONCRETE/28MPa 117
BaseQuantities - GrossVolume: 3.13841 m3
Pset_ColumnCommon - Slope: 0 rad
Pset_QuantityTakeOff - sets with these values: 2
Constraints - Moves With Grids: yes; Moves With Nearby Elements: yes; Room Bounding: yes
Dimensions - Area: 0.282732 m2; Volume: 3.13841 m3
Other - Family: PILOTE 730: PILOTE 730; Family and Type: PILOTE 730: PILOTE 730; Type: PILOTE 730: PILOTE 730; Type Id: PILOTE 730: PILOTE 730
Phasing - Phase Created: New Construction

# IfcColumn: PILOTE, PILOTE 738:PILOTE 738:201933
In: Default
Type - Description: D600; PredefinedType: COLUMN; Classification: A1020110 Piles - CIP (Uniformat)
Type - Graphics - Coarse Scale Fill Color: 0
Type - Identity Data - Assembly Code: A1020110; Assembly Description: Piles - CIP; Type Name: PILOTE 738
Type - Other - Category: Columns; Family Name: PILOTE 738
Type - Pset_ColumnCommon - Reference: Hormigón_PI-1/0(?); IsExternal: no; LoadBearing: yes
Type - Pset_ProductRequirements - Name: PILOTE; Category: Columns
Type - Pset_QuantityTakeOff - Reference: Hormigón_PI-1/0(?)
Type - Pset_ReinforcementBarPitchOfColumn - Reference: Hormigón_PI-1/0(?)
Material: CONCRETE/28MPa 117
BaseQuantities - GrossVolume: 3.13841 m3
Pset_ColumnCommon - Slope: 0 rad
Pset_QuantityTakeOff - sets with these values: 2
Constraints - Moves With Grids: yes; Moves With Nearby Elements: yes; Room Bounding: yes
Dimensions - Area: 0.282732 m2; Volume: 3.13841 m3
Other - Family: PILOTE 738: PILOTE 738; Family and Type: PILOTE 738: PILOTE 738; Type: PILOTE 738: PILOTE 738; Type Id: PILOTE 738: PILOTE 738
Phasing - Phase Created: New Construction

# IfcColumn: PILOTE, PILOTE 746:PILOTE 746:201945
In: Default
Type - Description: D600; PredefinedType: COLUMN; Classification: A1020110 Piles - CIP (Uniformat)
Type - Graphics - Coarse Scale Fill Color: 0
Type - Identity Data - Assembly Code: A1020110; Assembly Description: Piles - CIP; Type Name: PILOTE 746
Type - Other - Category: Columns; Family Name: PILOTE 746
Type - Pset_ColumnCommon - Reference: Hormigón_PI-1/0(?); IsExternal: no; LoadBearing: yes
Type - Pset_ProductRequirements - Name: PILOTE; Category: Columns
Type - Pset_QuantityTakeOff - Reference: Hormigón_PI-1/0(?)
Type - Pset_ReinforcementBarPitchOfColumn - Reference: Hormigón_PI-1/0(?)
Material: CONCRETE/28MPa 117
BaseQuantities - GrossVolume: 3.13841 m3
Pset_ColumnCommon - Slope: 0 rad
Pset_QuantityTakeOff - sets with these values: 2
Constraints - Moves With Grids: yes; Moves With Nearby Elements: yes; Room Bounding: yes
Dimensions - Area: 0.282732 m2; Volume: 3.13841 m3
Other - Family: PILOTE 746: PILOTE 746; Family and Type: PILOTE 746: PILOTE 746; Type: PILOTE 746: PILOTE 746; Type Id: PILOTE 746: PILOTE 746
Phasing - Phase Created: New Construction

# IfcColumn: PILOTE, PILOTE 754:PILOTE 754:201957
In: Default
Type - Description: D600; PredefinedType: COLUMN; Classification: A1020110 Piles - CIP (Uniformat)
Type - Graphics - Coarse Scale Fill Color: 0
Type - Identity Data - Assembly Code: A1020110; Assembly Description: Piles - CIP; Type Name: PILOTE 754
Type - Other - Category: Columns; Family Name: PILOTE 754
Type - Pset_ColumnCommon - Reference: Hormigón_PI-1/0(?); IsExternal: no; LoadBearing: yes
Type - Pset_ProductRequirements - Name: PILOTE; Category: Columns
Type - Pset_QuantityTakeOff - Reference: Hormigón_PI-1/0(?)
Type - Pset_ReinforcementBarPitchOfColumn - Reference: Hormigón_PI-1/0(?)
Material: CONCRETE/28MPa 117
BaseQuantities - GrossVolume: 3.13841 m3
Pset_ColumnCommon - Slope: 0 rad
Pset_QuantityTakeOff - sets with these values: 2
Constraints - Moves With Grids: yes; Moves With Nearby Elements: yes; Room Bounding: yes
Dimensions - Area: 0.282732 m2; Volume: 3.13841 m3
Other - Family: PILOTE 754: PILOTE 754; Family and Type: PILOTE 754: PILOTE 754; Type: PILOTE 754: PILOTE 754; Type Id: PILOTE 754: PILOTE 754
Phasing - Phase Created: New Construction

# IfcColumn: PILOTE, PILOTE 762:PILOTE 762:201969
In: Default
Type - Description: D600; PredefinedType: COLUMN; Classification: A1020110 Piles - CIP (Uniformat)
Type - Graphics - Coarse Scale Fill Color: 0
Type - Identity Data - Assembly Code: A1020110; Assembly Description: Piles - CIP; Type Name: PILOTE 762
Type - Other - Category: Columns; Family Name: PILOTE 762
Type - Pset_ColumnCommon - Reference: Hormigón_PI-1/0(?); IsExternal: no; LoadBearing: yes
Type - Pset_ProductRequirements - Name: PILOTE; Category: Columns
Type - Pset_QuantityTakeOff - Reference: Hormigón_PI-1/0(?)
Type - Pset_ReinforcementBarPitchOfColumn - Reference: Hormigón_PI-1/0(?)
Material: CONCRETE/28MPa 117
BaseQuantities - GrossVolume: 3.13841 m3
Pset_ColumnCommon - Slope: 0 rad
Pset_QuantityTakeOff - sets with these values: 2
Constraints - Moves With Grids: yes; Moves With Nearby Elements: yes; Room Bounding: yes
Dimensions - Area: 0.282732 m2; Volume: 3.13841 m3
Other - Family: PILOTE 762: PILOTE 762; Family and Type: PILOTE 762: PILOTE 762; Type: PILOTE 762: PILOTE 762; Type Id: PILOTE 762: PILOTE 762
Phasing - Phase Created: New Construction

# IfcColumn: PILOTE, PILOTE 770:PILOTE 770:201981
In: Default
Type - Description: D600; PredefinedType: COLUMN; Classification: A1020110 Piles - CIP (Uniformat)
Type - Graphics - Coarse Scale Fill Color: 0
Type - Identity Data - Assembly Code: A1020110; Assembly Description: Piles - CIP; Type Name: PILOTE 770
Type - Other - Category: Columns; Family Name: PILOTE 770
Type - Pset_ColumnCommon - Reference: Hormigón_PI-1/0(?); IsExternal: no; LoadBearing: yes
Type - Pset_ProductRequirements - Name: PILOTE; Category: Columns
Type - Pset_QuantityTakeOff - Reference: Hormigón_PI-1/0(?)
Type - Pset_ReinforcementBarPitchOfColumn - Reference: Hormigón_PI-1/0(?)
Material: CONCRETE/28MPa 117
BaseQuantities - GrossVolume: 3.13841 m3
Pset_ColumnCommon - Slope: 0 rad
Pset_QuantityTakeOff - sets with these values: 2
Constraints - Moves With Grids: yes; Moves With Nearby Elements: yes; Room Bounding: yes
Dimensions - Area: 0.282732 m2; Volume: 3.13841 m3
Other - Family: PILOTE 770: PILOTE 770; Family and Type: PILOTE 770: PILOTE 770; Type: PILOTE 770: PILOTE 770; Type Id: PILOTE 770: PILOTE 770
Phasing - Phase Created: New Construction

# IfcColumn: PILOTE, PILOTE 778:PILOTE 778:201993
In: Default
Type - Description: D600; PredefinedType: COLUMN; Classification: A1020110 Piles - CIP (Uniformat)
Type - Graphics - Coarse Scale Fill Color: 0
Type - Identity Data - Assembly Code: A1020110; Assembly Description: Piles - CIP; Type Name: PILOTE 778
Type - Other - Category: Columns; Family Name: PILOTE 778
Type - Pset_ColumnCommon - Reference: Hormigón_PI-1/0(?); IsExternal: no; LoadBearing: yes
Type - Pset_ProductRequirements - Name: PILOTE; Category: Columns
Type - Pset_QuantityTakeOff - Reference: Hormigón_PI-1/0(?)
Type - Pset_ReinforcementBarPitchOfColumn - Reference: Hormigón_PI-1/0(?)
Material: CONCRETE/28MPa 117
BaseQuantities - GrossVolume: 3.13841 m3
Pset_ColumnCommon - Slope: 0 rad
Pset_QuantityTakeOff - sets with these values: 2
Constraints - Moves With Grids: yes; Moves With Nearby Elements: yes; Room Bounding: yes
Dimensions - Area: 0.282732 m2; Volume: 3.13841 m3
Other - Family: PILOTE 778: PILOTE 778; Family and Type: PILOTE 778: PILOTE 778; Type: PILOTE 778: PILOTE 778; Type Id: PILOTE 778: PILOTE 778
Phasing - Phase Created: New Construction

# IfcColumn: PILOTE, PILOTE 788:PILOTE 788:202005
In: Default
Type - Description: D600; PredefinedType: COLUMN; Classification: A1020110 Piles - CIP (Uniformat)
Type - Graphics - Coarse Scale Fill Color: 0
Type - Identity Data - Assembly Code: A1020110; Assembly Description: Piles - CIP; Type Name: PILOTE 788
Type - Other - Category: Columns; Family Name: PILOTE 788
Type - Pset_ColumnCommon - Reference: Hormigón_PI-1/0(?); IsExternal: no; LoadBearing: yes
Type - Pset_ProductRequirements - Name: PILOTE; Category: Columns
Type - Pset_QuantityTakeOff - Reference: Hormigón_PI-1/0(?)
Type - Pset_ReinforcementBarPitchOfColumn - Reference: Hormigón_PI-1/0(?)
Material: CONCRETE/28MPa 117
BaseQuantities - GrossVolume: 3.13841 m3
Pset_ColumnCommon - Slope: 0 rad
Pset_QuantityTakeOff - sets with these values: 2
Constraints - Moves With Grids: yes; Moves With Nearby Elements: yes; Room Bounding: yes
Dimensions - Area: 0.282732 m2; Volume: 3.13841 m3
Other - Family: PILOTE 788: PILOTE 788; Family and Type: PILOTE 788: PILOTE 788; Type: PILOTE 788: PILOTE 788; Type Id: PILOTE 788: PILOTE 788
Phasing - Phase Created: New Construction

# IfcColumn: PILOTE, PILOTE 798:PILOTE 798:202017
In: Default
Type - Description: D600; PredefinedType: COLUMN; Classification: A1020110 Piles - CIP (Uniformat)
Type - Graphics - Coarse Scale Fill Color: 0
Type - Identity Data - Assembly Code: A1020110; Assembly Description: Piles - CIP; Type Name: PILOTE 798
Type - Other - Category: Columns; Family Name: PILOTE 798
Type - Pset_ColumnCommon - Reference: Hormigón_PI-1/0(?); IsExternal: no; LoadBearing: yes
Type - Pset_ProductRequirements - Name: PILOTE; Category: Columns
Type - Pset_QuantityTakeOff - Reference: Hormigón_PI-1/0(?)
Type - Pset_ReinforcementBarPitchOfColumn - Reference: Hormigón_PI-1/0(?)
Material: CONCRETE/28MPa 117
BaseQuantities - GrossVolume: 3.13841 m3
Pset_ColumnCommon - Slope: 0 rad
Pset_QuantityTakeOff - sets with these values: 2
Constraints - Moves With Grids: yes; Moves With Nearby Elements: yes; Room Bounding: yes
Dimensions - Area: 0.282732 m2; Volume: 3.13841 m3
Other - Family: PILOTE 798: PILOTE 798; Family and Type: PILOTE 798: PILOTE 798; Type: PILOTE 798: PILOTE 798; Type Id: PILOTE 798: PILOTE 798
Phasing - Phase Created: New Construction

# IfcColumn: PILOTE, PILOTE 806:PILOTE 806:202029
In: Default
Type - Description: D600; PredefinedType: COLUMN; Classification: A1020110 Piles - CIP (Uniformat)
Type - Graphics - Coarse Scale Fill Color: 0
Type - Identity Data - Assembly Code: A1020110; Assembly Description: Piles - CIP; Type Name: PILOTE 806
Type - Other - Category: Columns; Family Name: PILOTE 806
Type - Pset_ColumnCommon - Reference: Hormigón_PI-1/0(?); IsExternal: no; LoadBearing: yes
Type - Pset_ProductRequirements - Name: PILOTE; Category: Columns
Type - Pset_QuantityTakeOff - Reference: Hormigón_PI-1/0(?)
Type - Pset_ReinforcementBarPitchOfColumn - Reference: Hormigón_PI-1/0(?)
Material: CONCRETE/28MPa 117
BaseQuantities - GrossVolume: 3.13841 m3
Pset_ColumnCommon - Slope: 0 rad
Pset_QuantityTakeOff - sets with these values: 2
Constraints - Moves With Grids: yes; Moves With Nearby Elements: yes; Room Bounding: yes
Dimensions - Area: 0.282732 m2; Volume: 3.13841 m3
Other - Family: PILOTE 806: PILOTE 806; Family and Type: PILOTE 806: PILOTE 806; Type: PILOTE 806: PILOTE 806; Type Id: PILOTE 806: PILOTE 806
Phasing - Phase Created: New Construction

# IfcColumn: PILOTE, PILOTE 816:PILOTE 816:202041
In: Default
Type - Description: D600; PredefinedType: COLUMN; Classification: A1020110 Piles - CIP (Uniformat)
Type - Graphics - Coarse Scale Fill Color: 0
Type - Identity Data - Assembly Code: A1020110; Assembly Description: Piles - CIP; Type Name: PILOTE 816
Type - Other - Category: Columns; Family Name: PILOTE 816
Type - Pset_ColumnCommon - Reference: Hormigón_PI-1/0(?); IsExternal: no; LoadBearing: yes
Type - Pset_ProductRequirements - Name: PILOTE; Category: Columns
Type - Pset_QuantityTakeOff - Reference: Hormigón_PI-1/0(?)
Type - Pset_ReinforcementBarPitchOfColumn - Reference: Hormigón_PI-1/0(?)
Material: CONCRETE/28MPa 117
BaseQuantities - GrossVolume: 3.13841 m3
Pset_ColumnCommon - Slope: 0 rad
Pset_QuantityTakeOff - sets with these values: 2
Constraints - Moves With Grids: yes; Moves With Nearby Elements: yes; Room Bounding: yes
Dimensions - Area: 0.282732 m2; Volume: 3.13841 m3
Other - Family: PILOTE 816: PILOTE 816; Family and Type: PILOTE 816: PILOTE 816; Type: PILOTE 816: PILOTE 816; Type Id: PILOTE 816: PILOTE 816
Phasing - Phase Created: New Construction

# IfcColumn: PILOTE, PILOTE 824:PILOTE 824:202053
In: Default
Type - Description: D600; PredefinedType: COLUMN; Classification: A1020110 Piles - CIP (Uniformat)
Type - Graphics - Coarse Scale Fill Color: 0
Type - Identity Data - Assembly Code: A1020110; Assembly Description: Piles - CIP; Type Name: PILOTE 824
Type - Other - Category: Columns; Family Name: PILOTE 824
Type - Pset_ColumnCommon - Reference: Hormigón_PI-1/0(?); IsExternal: no; LoadBearing: yes
Type - Pset_ProductRequirements - Name: PILOTE; Category: Columns
Type - Pset_QuantityTakeOff - Reference: Hormigón_PI-1/0(?)
Type - Pset_ReinforcementBarPitchOfColumn - Reference: Hormigón_PI-1/0(?)
Material: CONCRETE/28MPa 117
BaseQuantities - GrossVolume: 3.13841 m3
Pset_ColumnCommon - Slope: 0 rad
Pset_QuantityTakeOff - sets with these values: 2
Constraints - Moves With Grids: yes; Moves With Nearby Elements: yes; Room Bounding: yes
Dimensions - Area: 0.282732 m2; Volume: 3.13841 m3
Other - Family: PILOTE 824: PILOTE 824; Family and Type: PILOTE 824: PILOTE 824; Type: PILOTE 824: PILOTE 824; Type Id: PILOTE 824: PILOTE 824
Phasing - Phase Created: New Construction

# IfcColumn: PILOTE, PILOTE 832:PILOTE 832:202065
In: Default
Type - Description: D600; PredefinedType: COLUMN; Classification: A1020110 Piles - CIP (Uniformat)
Type - Graphics - Coarse Scale Fill Color: 0
Type - Identity Data - Assembly Code: A1020110; Assembly Description: Piles - CIP; Type Name: PILOTE 832
Type - Other - Category: Columns; Family Name: PILOTE 832
Type - Pset_ColumnCommon - Reference: Hormigón_PI-1/0(?); IsExternal: no; LoadBearing: yes
Type - Pset_ProductRequirements - Name: PILOTE; Category: Columns
Type - Pset_QuantityTakeOff - Reference: Hormigón_PI-1/0(?)
Type - Pset_ReinforcementBarPitchOfColumn - Reference: Hormigón_PI-1/0(?)
Material: CONCRETE/28MPa 117
BaseQuantities - GrossVolume: 3.13841 m3
Pset_ColumnCommon - Slope: 0 rad
Pset_QuantityTakeOff - sets with these values: 2
Constraints - Moves With Grids: yes; Moves With Nearby Elements: yes; Room Bounding: yes
Dimensions - Area: 0.282732 m2; Volume: 3.13841 m3
Other - Family: PILOTE 832: PILOTE 832; Family and Type: PILOTE 832: PILOTE 832; Type: PILOTE 832: PILOTE 832; Type Id: PILOTE 832: PILOTE 832
Phasing - Phase Created: New Construction

# IfcColumn: PILOTE, PILOTE 840:PILOTE 840:202077
In: Default
Type - Description: D600; PredefinedType: COLUMN; Classification: A1020110 Piles - CIP (Uniformat)
Type - Graphics - Coarse Scale Fill Color: 0
Type - Identity Data - Assembly Code: A1020110; Assembly Description: Piles - CIP; Type Name: PILOTE 840
Type - Other - Category: Columns; Family Name: PILOTE 840
Type - Pset_ColumnCommon - Reference: Hormigón_PI-1/0(?); IsExternal: no; LoadBearing: yes
Type - Pset_ProductRequirements - Name: PILOTE; Category: Columns
Type - Pset_QuantityTakeOff - Reference: Hormigón_PI-1/0(?)
Type - Pset_ReinforcementBarPitchOfColumn - Reference: Hormigón_PI-1/0(?)
Material: CONCRETE/28MPa 117
BaseQuantities - GrossVolume: 3.13841 m3
Pset_ColumnCommon - Slope: 0 rad
Pset_QuantityTakeOff - sets with these values: 2
Constraints - Moves With Grids: yes; Moves With Nearby Elements: yes; Room Bounding: yes
Dimensions - Area: 0.282732 m2; Volume: 3.13841 m3
Other - Family: PILOTE 840: PILOTE 840; Family and Type: PILOTE 840: PILOTE 840; Type: PILOTE 840: PILOTE 840; Type Id: PILOTE 840: PILOTE 840
Phasing - Phase Created: New Construction

# IfcColumn: PILOTE, PILOTE 848:PILOTE 848:202089
In: Default
Type - Description: D600; PredefinedType: COLUMN; Classification: A1020110 Piles - CIP (Uniformat)
Type - Graphics - Coarse Scale Fill Color: 0
Type - Identity Data - Assembly Code: A1020110; Assembly Description: Piles - CIP; Type Name: PILOTE 848
Type - Other - Category: Columns; Family Name: PILOTE 848
Type - Pset_ColumnCommon - Reference: Hormigón_PI-1/0(?); IsExternal: no; LoadBearing: yes
Type - Pset_ProductRequirements - Name: PILOTE; Category: Columns
Type - Pset_QuantityTakeOff - Reference: Hormigón_PI-1/0(?)
Type - Pset_ReinforcementBarPitchOfColumn - Reference: Hormigón_PI-1/0(?)
Material: CONCRETE/28MPa 117
BaseQuantities - GrossVolume: 3.13841 m3
Pset_ColumnCommon - Slope: 0 rad
Pset_QuantityTakeOff - sets with these values: 2
Constraints - Moves With Grids: yes; Moves With Nearby Elements: yes; Room Bounding: yes
Dimensions - Area: 0.282732 m2; Volume: 3.13841 m3
Other - Family: PILOTE 848: PILOTE 848; Family and Type: PILOTE 848: PILOTE 848; Type: PILOTE 848: PILOTE 848; Type Id: PILOTE 848: PILOTE 848
Phasing - Phase Created: New Construction

# IfcColumn: PILOTE, PILOTE 856:PILOTE 856:202101
In: Default
Type - Description: D600; PredefinedType: COLUMN; Classification: A1020110 Piles - CIP (Uniformat)
Type - Graphics - Coarse Scale Fill Color: 0
Type - Identity Data - Assembly Code: A1020110; Assembly Description: Piles - CIP; Type Name: PILOTE 856
Type - Other - Category: Columns; Family Name: PILOTE 856
Type - Pset_ColumnCommon - Reference: Hormigón_PI-1/0(?); IsExternal: no; LoadBearing: yes
Type - Pset_ProductRequirements - Name: PILOTE; Category: Columns
Type - Pset_QuantityTakeOff - Reference: Hormigón_PI-1/0(?)
Type - Pset_ReinforcementBarPitchOfColumn - Reference: Hormigón_PI-1/0(?)
Material: CONCRETE/28MPa 117
BaseQuantities - GrossVolume: 3.13841 m3
Pset_ColumnCommon - Slope: 0 rad
Pset_QuantityTakeOff - sets with these values: 2
Constraints - Moves With Grids: yes; Moves With Nearby Elements: yes; Room Bounding: yes
Dimensions - Area: 0.282732 m2; Volume: 3.13841 m3
Other - Family: PILOTE 856: PILOTE 856; Family and Type: PILOTE 856: PILOTE 856; Type: PILOTE 856: PILOTE 856; Type Id: PILOTE 856: PILOTE 856
Phasing - Phase Created: New Construction

# IfcColumn: PILOTE, PILOTE 864:PILOTE 864:202113
In: Default
Type - Description: D600; PredefinedType: COLUMN; Classification: A1020110 Piles - CIP (Uniformat)
Type - Graphics - Coarse Scale Fill Color: 0
Type - Identity Data - Assembly Code: A1020110; Assembly Description: Piles - CIP; Type Name: PILOTE 864
Type - Other - Category: Columns; Family Name: PILOTE 864
Type - Pset_ColumnCommon - Reference: Hormigón_PI-1/0(?); IsExternal: no; LoadBearing: yes
Type - Pset_ProductRequirements - Name: PILOTE; Category: Columns
Type - Pset_QuantityTakeOff - Reference: Hormigón_PI-1/0(?)
Type - Pset_ReinforcementBarPitchOfColumn - Reference: Hormigón_PI-1/0(?)
Material: CONCRETE/28MPa 117
BaseQuantities - GrossVolume: 3.13841 m3
Pset_ColumnCommon - Slope: 0 rad
Pset_QuantityTakeOff - sets with these values: 2
Constraints - Moves With Grids: yes; Moves With Nearby Elements: yes; Room Bounding: yes
Dimensions - Area: 0.282732 m2; Volume: 3.13841 m3
Other - Family: PILOTE 864: PILOTE 864; Family and Type: PILOTE 864: PILOTE 864; Type: PILOTE 864: PILOTE 864; Type Id: PILOTE 864: PILOTE 864
Phasing - Phase Created: New Construction

# IfcColumn: PILOTE, PILOTE 872:PILOTE 872:202125
In: Default
Type - Description: D600; PredefinedType: COLUMN; Classification: A1020110 Piles - CIP (Uniformat)
Type - Graphics - Coarse Scale Fill Color: 0
Type - Identity Data - Assembly Code: A1020110; Assembly Description: Piles - CIP; Type Name: PILOTE 872
Type - Other - Category: Columns; Family Name: PILOTE 872
Type - Pset_ColumnCommon - Reference: Hormigón_PI-1/0(?); IsExternal: no; LoadBearing: yes
Type - Pset_ProductRequirements - Name: PILOTE; Category: Columns
Type - Pset_QuantityTakeOff - Reference: Hormigón_PI-1/0(?)
Type - Pset_ReinforcementBarPitchOfColumn - Reference: Hormigón_PI-1/0(?)
Material: CONCRETE/28MPa 117
BaseQuantities - GrossVolume: 3.13841 m3
Pset_ColumnCommon - Slope: 0 rad
Pset_QuantityTakeOff - sets with these values: 2
Constraints - Moves With Grids: yes; Moves With Nearby Elements: yes; Room Bounding: yes
Dimensions - Area: 0.282732 m2; Volume: 3.13841 m3
Other - Family: PILOTE 872: PILOTE 872; Family and Type: PILOTE 872: PILOTE 872; Type: PILOTE 872: PILOTE 872; Type Id: PILOTE 872: PILOTE 872
Phasing - Phase Created: New Construction

# IfcColumn: PILOTE, PILOTE 882:PILOTE 882:202137
In: Default
Type - Description: D600; PredefinedType: COLUMN; Classification: A1020110 Piles - CIP (Uniformat)
Type - Graphics - Coarse Scale Fill Color: 0
Type - Identity Data - Assembly Code: A1020110; Assembly Description: Piles - CIP; Type Name: PILOTE 882
Type - Other - Category: Columns; Family Name: PILOTE 882
Type - Pset_ColumnCommon - Reference: Hormigón_PI-1/0(?); IsExternal: no; LoadBearing: yes
Type - Pset_ProductRequirements - Name: PILOTE; Category: Columns
Type - Pset_QuantityTakeOff - Reference: Hormigón_PI-1/0(?)
Type - Pset_ReinforcementBarPitchOfColumn - Reference: Hormigón_PI-1/0(?)
Material: CONCRETE/28MPa 117
BaseQuantities - GrossVolume: 3.13841 m3
Pset_ColumnCommon - Slope: 0 rad
Pset_QuantityTakeOff - sets with these values: 2
Constraints - Moves With Grids: yes; Moves With Nearby Elements: yes; Room Bounding: yes
Dimensions - Area: 0.282732 m2; Volume: 3.13841 m3
Other - Family: PILOTE 882: PILOTE 882; Family and Type: PILOTE 882: PILOTE 882; Type: PILOTE 882: PILOTE 882; Type Id: PILOTE 882: PILOTE 882
Phasing - Phase Created: New Construction

# IfcColumn: PILOTE, PILOTE 890:PILOTE 890:202149
In: Default
Type - Description: D600; PredefinedType: COLUMN; Classification: A1020110 Piles - CIP (Uniformat)
Type - Graphics - Coarse Scale Fill Color: 0
Type - Identity Data - Assembly Code: A1020110; Assembly Description: Piles - CIP; Type Name: PILOTE 890
Type - Other - Category: Columns; Family Name: PILOTE 890
Type - Pset_ColumnCommon - Reference: Hormigón_PI-1/0(?); IsExternal: no; LoadBearing: yes
Type - Pset_ProductRequirements - Name: PILOTE; Category: Columns
Type - Pset_QuantityTakeOff - Reference: Hormigón_PI-1/0(?)
Type - Pset_ReinforcementBarPitchOfColumn - Reference: Hormigón_PI-1/0(?)
Material: CONCRETE/28MPa 117
BaseQuantities - GrossVolume: 3.13841 m3
Pset_ColumnCommon - Slope: 0 rad
Pset_QuantityTakeOff - sets with these values: 2
Constraints - Moves With Grids: yes; Moves With Nearby Elements: yes; Room Bounding: yes
Dimensions - Area: 0.282732 m2; Volume: 3.13841 m3
Other - Family: PILOTE 890: PILOTE 890; Family and Type: PILOTE 890: PILOTE 890; Type: PILOTE 890: PILOTE 890; Type Id: PILOTE 890: PILOTE 890
Phasing - Phase Created: New Construction

# IfcColumn: PILOTE, PILOTE 898:PILOTE 898:202161
In: Default
Type - Description: D600; PredefinedType: COLUMN; Classification: A1020110 Piles - CIP (Uniformat)
Type - Graphics - Coarse Scale Fill Color: 0
Type - Identity Data - Assembly Code: A1020110; Assembly Description: Piles - CIP; Type Name: PILOTE 898
Type - Other - Category: Columns; Family Name: PILOTE 898
Type - Pset_ColumnCommon - Reference: Hormigón_PI-1/0(?); IsExternal: no; LoadBearing: yes
Type - Pset_ProductRequirements - Name: PILOTE; Category: Columns
Type - Pset_QuantityTakeOff - Reference: Hormigón_PI-1/0(?)
Type - Pset_ReinforcementBarPitchOfColumn - Reference: Hormigón_PI-1/0(?)
Material: CONCRETE/28MPa 117
BaseQuantities - GrossVolume: 3.13841 m3
Pset_ColumnCommon - Slope: 0 rad
Pset_QuantityTakeOff - sets with these values: 2
Constraints - Moves With Grids: yes; Moves With Nearby Elements: yes; Room Bounding: yes
Dimensions - Area: 0.282732 m2; Volume: 3.13841 m3
Other - Family: PILOTE 898: PILOTE 898; Family and Type: PILOTE 898: PILOTE 898; Type: PILOTE 898: PILOTE 898; Type Id: PILOTE 898: PILOTE 898
Phasing - Phase Created: New Construction

# IfcColumn: PILOTE, PILOTE 906:PILOTE 906:202173
In: Default
Type - Description: D600; PredefinedType: COLUMN; Classification: A1020110 Piles - CIP (Uniformat)
Type - Graphics - Coarse Scale Fill Color: 0
Type - Identity Data - Assembly Code: A1020110; Assembly Description: Piles - CIP; Type Name: PILOTE 906
Type - Other - Category: Columns; Family Name: PILOTE 906
Type - Pset_ColumnCommon - Reference: Hormigón_PI-1/0(?); IsExternal: no; LoadBearing: yes
Type - Pset_ProductRequirements - Name: PILOTE; Category: Columns
Type - Pset_QuantityTakeOff - Reference: Hormigón_PI-1/0(?)
Type - Pset_ReinforcementBarPitchOfColumn - Reference: Hormigón_PI-1/0(?)
Material: CONCRETE/28MPa 117
BaseQuantities - GrossVolume: 3.13841 m3
Pset_ColumnCommon - Slope: 0 rad
Pset_QuantityTakeOff - sets with these values: 2
Constraints - Moves With Grids: yes; Moves With Nearby Elements: yes; Room Bounding: yes
Dimensions - Area: 0.282732 m2; Volume: 3.13841 m3
Other - Family: PILOTE 906: PILOTE 906; Family and Type: PILOTE 906: PILOTE 906; Type: PILOTE 906: PILOTE 906; Type Id: PILOTE 906: PILOTE 906
Phasing - Phase Created: New Construction

# IfcColumn: PILOTE, PILOTE 914:PILOTE 914:202185
In: Default
Type - Description: D600; PredefinedType: COLUMN; Classification: A1020110 Piles - CIP (Uniformat)
Type - Graphics - Coarse Scale Fill Color: 0
Type - Identity Data - Assembly Code: A1020110; Assembly Description: Piles - CIP; Type Name: PILOTE 914
Type - Other - Category: Columns; Family Name: PILOTE 914
Type - Pset_ColumnCommon - Reference: Hormigón_PI-1/0(?); IsExternal: no; LoadBearing: yes
Type - Pset_ProductRequirements - Name: PILOTE; Category: Columns
Type - Pset_QuantityTakeOff - Reference: Hormigón_PI-1/0(?)
Type - Pset_ReinforcementBarPitchOfColumn - Reference: Hormigón_PI-1/0(?)
Material: CONCRETE/28MPa 117
BaseQuantities - GrossVolume: 3.13841 m3
Pset_ColumnCommon - Slope: 0 rad
Pset_QuantityTakeOff - sets with these values: 2
Constraints - Moves With Grids: yes; Moves With Nearby Elements: yes; Room Bounding: yes
Dimensions - Area: 0.282732 m2; Volume: 3.13841 m3
Other - Family: PILOTE 914: PILOTE 914; Family and Type: PILOTE 914: PILOTE 914; Type: PILOTE 914: PILOTE 914; Type Id: PILOTE 914: PILOTE 914
Phasing - Phase Created: New Construction

# IfcColumn: PILOTE, PILOTE 922:PILOTE 922:202197
In: Default
Type - Description: D600; PredefinedType: COLUMN; Classification: A1020110 Piles - CIP (Uniformat)
Type - Graphics - Coarse Scale Fill Color: 0
Type - Identity Data - Assembly Code: A1020110; Assembly Description: Piles - CIP; Type Name: PILOTE 922
Type - Other - Category: Columns; Family Name: PILOTE 922
Type - Pset_ColumnCommon - Reference: Hormigón_PI-1/0(?); IsExternal: no; LoadBearing: yes
Type - Pset_ProductRequirements - Name: PILOTE; Category: Columns
Type - Pset_QuantityTakeOff - Reference: Hormigón_PI-1/0(?)
Type - Pset_ReinforcementBarPitchOfColumn - Reference: Hormigón_PI-1/0(?)
Material: CONCRETE/28MPa 117
BaseQuantities - GrossVolume: 3.13841 m3
Pset_ColumnCommon - Slope: 0 rad
Pset_QuantityTakeOff - sets with these values: 2
Constraints - Moves With Grids: yes; Moves With Nearby Elements: yes; Room Bounding: yes
Dimensions - Area: 0.282732 m2; Volume: 3.13841 m3
Other - Family: PILOTE 922: PILOTE 922; Family and Type: PILOTE 922: PILOTE 922; Type: PILOTE 922: PILOTE 922; Type Id: PILOTE 922: PILOTE 922
Phasing - Phase Created: New Construction

# IfcColumn: PILOTE, PILOTE 930:PILOTE 930:202209
In: Default
Type - Description: D600; PredefinedType: COLUMN; Classification: A1020110 Piles - CIP (Uniformat)
Type - Graphics - Coarse Scale Fill Color: 0
Type - Identity Data - Assembly Code: A1020110; Assembly Description: Piles - CIP; Type Name: PILOTE 930
Type - Other - Category: Columns; Family Name: PILOTE 930
Type - Pset_ColumnCommon - Reference: Hormigón_PI-1/0(?); IsExternal: no; LoadBearing: yes
Type - Pset_ProductRequirements - Name: PILOTE; Category: Columns
Type - Pset_QuantityTakeOff - Reference: Hormigón_PI-1/0(?)
Type - Pset_ReinforcementBarPitchOfColumn - Reference: Hormigón_PI-1/0(?)
Material: CONCRETE/28MPa 117
BaseQuantities - GrossVolume: 3.13841 m3
Pset_ColumnCommon - Slope: 0 rad
Pset_QuantityTakeOff - sets with these values: 2
Constraints - Moves With Grids: yes; Moves With Nearby Elements: yes; Room Bounding: yes
Dimensions - Area: 0.282732 m2; Volume: 3.13841 m3
Other - Family: PILOTE 930: PILOTE 930; Family and Type: PILOTE 930: PILOTE 930; Type: PILOTE 930: PILOTE 930; Type Id: PILOTE 930: PILOTE 930
Phasing - Phase Created: New Construction

# IfcColumn: PILOTE, PILOTE 940:PILOTE 940:202221
In: Default
Type - Description: D600; PredefinedType: COLUMN; Classification: A1020110 Piles - CIP (Uniformat)
Type - Graphics - Coarse Scale Fill Color: 0
Type - Identity Data - Assembly Code: A1020110; Assembly Description: Piles - CIP; Type Name: PILOTE 940
Type - Other - Category: Columns; Family Name: PILOTE 940
Type - Pset_ColumnCommon - Reference: Hormigón_PI-1/0(?); IsExternal: no; LoadBearing: yes
Type - Pset_ProductRequirements - Name: PILOTE; Category: Columns
Type - Pset_QuantityTakeOff - Reference: Hormigón_PI-1/0(?)
Type - Pset_ReinforcementBarPitchOfColumn - Reference: Hormigón_PI-1/0(?)
Material: CONCRETE/28MPa 117
BaseQuantities - GrossVolume: 3.13841 m3
Pset_ColumnCommon - Slope: 0 rad
Pset_QuantityTakeOff - sets with these values: 2
Constraints - Moves With Grids: yes; Moves With Nearby Elements: yes; Room Bounding: yes
Dimensions - Area: 0.282732 m2; Volume: 3.13841 m3
Other - Family: PILOTE 940: PILOTE 940; Family and Type: PILOTE 940: PILOTE 940; Type: PILOTE 940: PILOTE 940; Type Id: PILOTE 940: PILOTE 940
Phasing - Phase Created: New Construction

# IfcColumn: PILOTE, PILOTE 948:PILOTE 948:202233
In: Default
Type - Description: D600; PredefinedType: COLUMN; Classification: A1020110 Piles - CIP (Uniformat)
Type - Graphics - Coarse Scale Fill Color: 0
Type - Identity Data - Assembly Code: A1020110; Assembly Description: Piles - CIP; Type Name: PILOTE 948
Type - Other - Category: Columns; Family Name: PILOTE 948
Type - Pset_ColumnCommon - Reference: Hormigón_PI-1/0(?); IsExternal: no; LoadBearing: yes
Type - Pset_ProductRequirements - Name: PILOTE; Category: Columns
Type - Pset_QuantityTakeOff - Reference: Hormigón_PI-1/0(?)
Type - Pset_ReinforcementBarPitchOfColumn - Reference: Hormigón_PI-1/0(?)
Material: CONCRETE/28MPa 117
BaseQuantities - GrossVolume: 3.13841 m3
Pset_ColumnCommon - Slope: 0 rad
Pset_QuantityTakeOff - sets with these values: 2
Constraints - Moves With Grids: yes; Moves With Nearby Elements: yes; Room Bounding: yes
Dimensions - Area: 0.282732 m2; Volume: 3.13841 m3
Other - Family: PILOTE 948: PILOTE 948; Family and Type: PILOTE 948: PILOTE 948; Type: PILOTE 948: PILOTE 948; Type Id: PILOTE 948: PILOTE 948
Phasing - Phase Created: New Construction

# IfcColumn: PILOTE, PILOTE 958:PILOTE 958:202245
In: Default
Type - Description: D600; PredefinedType: COLUMN; Classification: A1020110 Piles - CIP (Uniformat)
Type - Graphics - Coarse Scale Fill Color: 0
Type - Identity Data - Assembly Code: A1020110; Assembly Description: Piles - CIP; Type Name: PILOTE 958
Type - Other - Category: Columns; Family Name: PILOTE 958
Type - Pset_ColumnCommon - Reference: Hormigón_PI-1/0(?); IsExternal: no; LoadBearing: yes
Type - Pset_ProductRequirements - Name: PILOTE; Category: Columns
Type - Pset_QuantityTakeOff - Reference: Hormigón_PI-1/0(?)
Type - Pset_ReinforcementBarPitchOfColumn - Reference: Hormigón_PI-1/0(?)
Material: CONCRETE/28MPa 117
BaseQuantities - GrossVolume: 3.13841 m3
Pset_ColumnCommon - Slope: 0 rad
Pset_QuantityTakeOff - sets with these values: 2
Constraints - Moves With Grids: yes; Moves With Nearby Elements: yes; Room Bounding: yes
Dimensions - Area: 0.282732 m2; Volume: 3.13841 m3
Other - Family: PILOTE 958: PILOTE 958; Family and Type: PILOTE 958: PILOTE 958; Type: PILOTE 958: PILOTE 958; Type Id: PILOTE 958: PILOTE 958
Phasing - Phase Created: New Construction

# IfcColumn: PILOTE, PILOTE 966:PILOTE 966:202257
In: Default
Type - Description: D600; PredefinedType: COLUMN; Classification: A1020110 Piles - CIP (Uniformat)
Type - Graphics - Coarse Scale Fill Color: 0
Type - Identity Data - Assembly Code: A1020110; Assembly Description: Piles - CIP; Type Name: PILOTE 966
Type - Other - Category: Columns; Family Name: PILOTE 966
Type - Pset_ColumnCommon - Reference: Hormigón_PI-1/0(?); IsExternal: no; LoadBearing: yes
Type - Pset_ProductRequirements - Name: PILOTE; Category: Columns
Type - Pset_QuantityTakeOff - Reference: Hormigón_PI-1/0(?)
Type - Pset_ReinforcementBarPitchOfColumn - Reference: Hormigón_PI-1/0(?)
Material: CONCRETE/28MPa 117
BaseQuantities - GrossVolume: 3.13841 m3
Pset_ColumnCommon - Slope: 0 rad
Pset_QuantityTakeOff - sets with these values: 2
Constraints - Moves With Grids: yes; Moves With Nearby Elements: yes; Room Bounding: yes
Dimensions - Area: 0.282732 m2; Volume: 3.13841 m3
Other - Family: PILOTE 966: PILOTE 966; Family and Type: PILOTE 966: PILOTE 966; Type: PILOTE 966: PILOTE 966; Type Id: PILOTE 966: PILOTE 966
Phasing - Phase Created: New Construction

# IfcColumn: PILOTE, PILOTE 974:PILOTE 974:202269
In: Default
Type - Description: D600; PredefinedType: COLUMN; Classification: A1020110 Piles - CIP (Uniformat)
Type - Graphics - Coarse Scale Fill Color: 0
Type - Identity Data - Assembly Code: A1020110; Assembly Description: Piles - CIP; Type Name: PILOTE 974
Type - Other - Category: Columns; Family Name: PILOTE 974
Type - Pset_ColumnCommon - Reference: Hormigón_PI-1/0(?); IsExternal: no; LoadBearing: yes
Type - Pset_ProductRequirements - Name: PILOTE; Category: Columns
Type - Pset_QuantityTakeOff - Reference: Hormigón_PI-1/0(?)
Type - Pset_ReinforcementBarPitchOfColumn - Reference: Hormigón_PI-1/0(?)
Material: CONCRETE/28MPa 117
BaseQuantities - GrossVolume: 3.13841 m3
Pset_ColumnCommon - Slope: 0 rad
Pset_QuantityTakeOff - sets with these values: 2
Constraints - Moves With Grids: yes; Moves With Nearby Elements: yes; Room Bounding: yes
Dimensions - Area: 0.282732 m2; Volume: 3.13841 m3
Other - Family: PILOTE 974: PILOTE 974; Family and Type: PILOTE 974: PILOTE 974; Type: PILOTE 974: PILOTE 974; Type Id: PILOTE 974: PILOTE 974
Phasing - Phase Created: New Construction

# IfcColumn: PILOTE, PILOTE 982:PILOTE 982:202281
In: Default
Type - Description: D600; PredefinedType: COLUMN; Classification: A1020110 Piles - CIP (Uniformat)
Type - Graphics - Coarse Scale Fill Color: 0
Type - Identity Data - Assembly Code: A1020110; Assembly Description: Piles - CIP; Type Name: PILOTE 982
Type - Other - Category: Columns; Family Name: PILOTE 982
Type - Pset_ColumnCommon - Reference: Hormigón_PI-1/0(?); IsExternal: no; LoadBearing: yes
Type - Pset_ProductRequirements - Name: PILOTE; Category: Columns
Type - Pset_QuantityTakeOff - Reference: Hormigón_PI-1/0(?)
Type - Pset_ReinforcementBarPitchOfColumn - Reference: Hormigón_PI-1/0(?)
Material: CONCRETE/28MPa 117
BaseQuantities - GrossVolume: 3.13841 m3
Pset_ColumnCommon - Slope: 0 rad
Pset_QuantityTakeOff - sets with these values: 2
Constraints - Moves With Grids: yes; Moves With Nearby Elements: yes; Room Bounding: yes
Dimensions - Area: 0.282732 m2; Volume: 3.13841 m3
Other - Family: PILOTE 982: PILOTE 982; Family and Type: PILOTE 982: PILOTE 982; Type: PILOTE 982: PILOTE 982; Type Id: PILOTE 982: PILOTE 982
Phasing - Phase Created: New Construction

# IfcColumn: PILOTE, PILOTE 992:PILOTE 992:202293
In: Default
Type - Description: D600; PredefinedType: COLUMN; Classification: A1020110 Piles - CIP (Uniformat)
Type - Graphics - Coarse Scale Fill Color: 0
Type - Identity Data - Assembly Code: A1020110; Assembly Description: Piles - CIP; Type Name: PILOTE 992
Type - Other - Category: Columns; Family Name: PILOTE 992
Type - Pset_ColumnCommon - Reference: Hormigón_PI-1/0(?); IsExternal: no; LoadBearing: yes
Type - Pset_ProductRequirements - Name: PILOTE; Category: Columns
Type - Pset_QuantityTakeOff - Reference: Hormigón_PI-1/0(?)
Type - Pset_ReinforcementBarPitchOfColumn - Reference: Hormigón_PI-1/0(?)
Material: CONCRETE/28MPa 117
BaseQuantities - GrossVolume: 3.13841 m3
Pset_ColumnCommon - Slope: 0 rad
Pset_QuantityTakeOff - sets with these values: 2
Constraints - Moves With Grids: yes; Moves With Nearby Elements: yes; Room Bounding: yes
Dimensions - Area: 0.282732 m2; Volume: 3.13841 m3
Other - Family: PILOTE 992: PILOTE 992; Family and Type: PILOTE 992: PILOTE 992; Type: PILOTE 992: PILOTE 992; Type Id: PILOTE 992: PILOTE 992
Phasing - Phase Created: New Construction

# IfcOpeningElement: Opening, PANTALLA
In: Default
Description: 10500*300; Classification: A1010210 Foundation Walls - CIP (Uniformat)
BaseQuantities - Depth: 188620 mm; Height: 94309.8 mm; Width: 188620 mm
Constraints - Moves With Nearby Elements: no; Elevation: 0 mm
Other - Category: IfcOpeningElements; Family: Opening: Opening; Family and Type: Opening: Opening; Type: Opening: Opening; Type Id: Opening: Opening
Pset_ElementShading - Roughness: 304.8 mm
Pset_ProductRequirements - Name: PANTALLA; Category: Walls
Pset_QuantityTakeOff - Reference: Hormigón_MP-1/0(?); sets with these values: 2
Identity Data(Type) - Type Name: Opening
Other(Type) - Category: IfcOpeningElements; Family Name: Opening

# IfcSlab: CONTRAPISO, CONTRAPISO 5434:CONTRAPISO 5434:203745
In: Default
Type - Description: 200*64300; PredefinedType: FLOOR; Material: Default Roof
Type - Identity Data - Assembly Code: A1030110; Assembly Description: SOG - Reinforced; Type Name: CONTRAPISO 5434
Type - Other - Category: Floors; Family Name: CONTRAPISO 5434
Type - Pset_ProductRequirements - Name: CONTRAPISO; Category: Floors
Type - Pset_QuantityTakeOff - Reference: Hormigón_LC-1/0(?)
Type - Pset_ReinforcementBarPitchOfSlab - Reference: Hormigón_LC-1/0(?)
Type - Pset_SlabCommon - IsExternal: no; LoadBearing: yes; Reference: Hormigón_LC-1/0(?)
Classification: A1030110 SOG - Reinforced (Uniformat)
Pset_QuantityTakeOff - sets with these values: 2
Pset_SlabCommon - PitchAngle: 0 rad
BaseQuantities - GrossArea: 3966.93 m2; NetArea: 8043.24 m2; GrossVolume: 793385 m3; NetVolume: 793.385 m3; Perimeter: 292954 mm; Width: 200 mm
Constraints - Room Bounding: yes; Moves With Nearby Elements: no
Dimensions - Area: 3966.93 m2; Volume: 793.385 m3
Other - Family: CONTRAPISO 5434: CONTRAPISO 5434; Family and Type: CONTRAPISO 5434: CONTRAPISO 5434; Type: CONTRAPISO 5434: CONTRAPISO 5434; Type Id: CONTRAPISO 5434: CONTRAPISO 5434
Phasing - Phase Created: New Construction

# IfcSlab: CONTRAPISO, CONTRAPISO:CONTRAPISO:202814
In: Default
Type - Description: 39500*668; PredefinedType: FLOOR; Material: CONCRETE/28MPa
Type - Identity Data - Assembly Code: C2010120; Assembly Description: Stairs - Precast; Type Name: CONTRAPISO
Type - Other - Category: Floors; Family Name: CONTRAPISO
Type - Pset_ProductRequirements - Name: CONTRAPISO; Category: Floors
Type - Pset_QuantityTakeOff - Reference: Hormigón_LC-1/0(?)
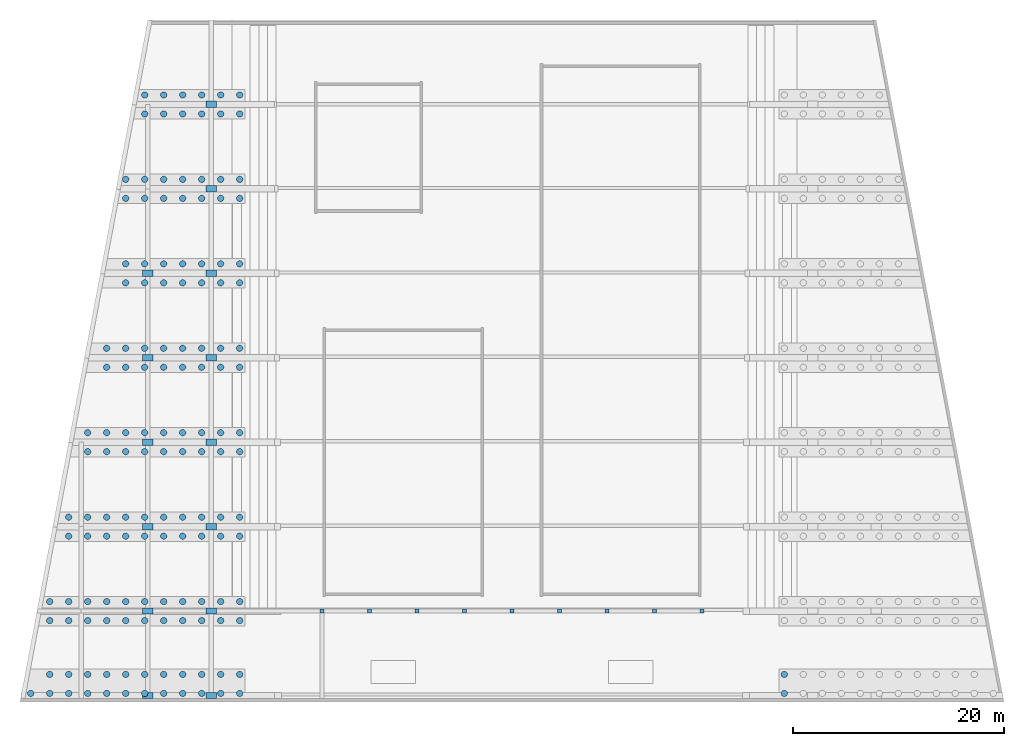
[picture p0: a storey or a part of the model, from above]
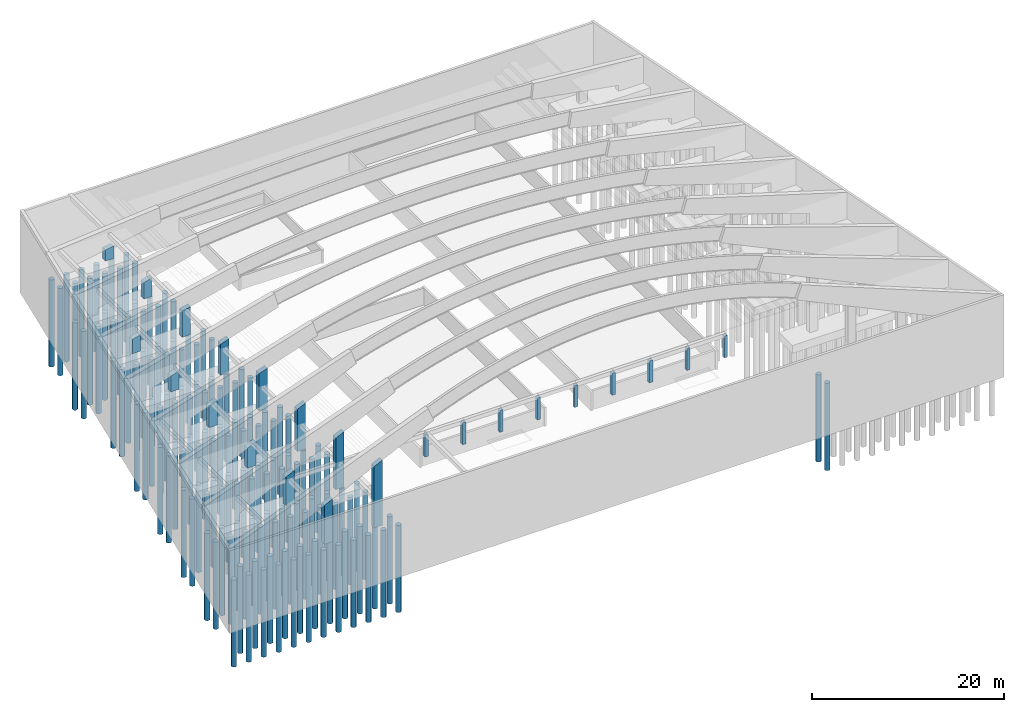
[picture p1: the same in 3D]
Properties of the parts of a building model (IFC2X3), part 5 of 5

# IfcSlab: CONTRAPISO, CONTRAPISO:CONTRAPISO:202814
Type - Pset_ReinforcementBarPitchOfSlab - Reference: Hormigón_LC-1/0(?)
Type - Pset_SlabCommon - IsExternal: no; LoadBearing: yes; Reference: Hormigón_LC-1/0(?)
Classification: C2010120 Stairs - Precast (Uniformat)
Pset_QuantityTakeOff - sets with these values: 2
Pset_SlabCommon - PitchAngle: 0 rad
BaseQuantities - GrossArea: 2.14254 m2; NetArea: 492.188 m2; GrossVolume: 84630.3 m3; NetVolume: 84.6303 m3; Perimeter: 12352 mm; Width: 39500 mm
Constraints - Room Bounding: yes; Moves With Nearby Elements: no
Dimensions - Area: 2.14254 m2; Volume: 84.6303 m3
Other - Family: CONTRAPISO: CONTRAPISO; Family and Type: CONTRAPISO: CONTRAPISO; Type: CONTRAPISO: CONTRAPISO; Type Id: CONTRAPISO: CONTRAPISO
Phasing - Phase Created: New Construction

# IfcSlab: CONTRAPISO, CONTRAPISO 2626:CONTRAPISO 2626:203393
In: Default
Type - Description: 39500*668; PredefinedType: FLOOR; Material: CONCRETE/28MPa
Type - Identity Data - Assembly Code: C2010120; Assembly Description: Stairs - Precast; Type Name: CONTRAPISO 2626
Type - Materials and Finishes - Structural Material: CONCRETE/28MPa 1864
Type - Other - Category: Floors; Family Name: CONTRAPISO 2626
Type - Pset_ProductRequirements - Name: CONTRAPISO; Category: Floors
Type - Pset_QuantityTakeOff - Reference: Hormigón_LC-1/0(?)
Type - Pset_ReinforcementBarPitchOfSlab - Reference: Hormigón_LC-1/0(?)
Type - Pset_SlabCommon - IsExternal: no; LoadBearing: yes; Reference: Hormigón_LC-1/0(?)
Classification: C2010120 Stairs - Precast (Uniformat)
Pset_QuantityTakeOff - sets with these values: 2
Pset_SlabCommon - PitchAngle: 0 rad
BaseQuantities - GrossArea: 2.14254 m2; NetArea: 492.188 m2; GrossVolume: 84630.3 m3; NetVolume: 84.6303 m3; Perimeter: 12352 mm; Width: 39500 mm
Constraints - Room Bounding: yes; Moves With Nearby Elements: no
Dimensions - Area: 2.14254 m2; Volume: 84.6303 m3
Other - Family: CONTRAPISO 2626: CONTRAPISO 2626; Family and Type: CONTRAPISO 2626: CONTRAPISO 2626; Type: CONTRAPISO 2626: CONTRAPISO 2626; Type Id: CONTRAPISO 2626: CONTRAPISO 2626
Phasing - Phase Created: New Construction

# IfcSlab: ENTREPISO, ENTREPISO:ENTREPISO:203781
In: Default
Type - Description: 300*64300; PredefinedType: FLOOR; Material: Concrete, Cast-in-Place gray
Type - Identity Data - Assembly Code: B1010410; Assembly Description: CIP Slabs - One Way; Type Name: ENTREPISO
Type - Other - Category: Floors; Family Name: ENTREPISO
Type - Pset_ProductRequirements - Name: ENTREPISO; Category: Floors
Type - Pset_QuantityTakeOff - Reference: P/0(?)
Type - Pset_ReinforcementBarPitchOfSlab - Reference: P/0(?)
Type - Pset_SlabCommon - IsExternal: no; LoadBearing: yes; Reference: P/0(?)
Classification: B1010410 CIP Slabs - One Way (Uniformat)
Pset_QuantityTakeOff - sets with these values: 2
Pset_SlabCommon - PitchAngle: 0 rad
BaseQuantities - GrossArea: 2210.98 m2; NetArea: 4550.95 m2; GrossVolume: 663294 m3; NetVolume: 663.294 m3; Perimeter: 404352 mm; Width: 300 mm
Constraints - Room Bounding: yes; Level: Level: Undefined; Moves With Nearby Elements: no
Dimensions - Area: 2210.98 m2; Volume: 663.294 m3
Other - Family: ENTREPISO: ENTREPISO; Family and Type: ENTREPISO: ENTREPISO; Type: ENTREPISO: ENTREPISO; Type Id: ENTREPISO: ENTREPISO
Phasing - Phase Created: New Construction

# IfcSlab: LOSA, LOSA 1499:LOSA 1499:202836
In: Default
Type - Description: 15680*665; PredefinedType: FLOOR; Material: CONCRETE/28MPa
Type - Identity Data - Assembly Code: C2010120; Assembly Description: Stairs - Precast; Type Name: LOSA 1499
Type - Other - Category: Floors; Family Name: LOSA 1499
Type - Pset_ProductRequirements - Name: LOSA; Category: Floors
Type - Pset_QuantityTakeOff - Reference: Hormigón_GR-1/0(?)
Type - Pset_ReinforcementBarPitchOfSlab - Reference: Hormigón_GR-1/0(?)
Type - Pset_SlabCommon - IsExternal: no; LoadBearing: yes; Reference: Hormigón_GR-1/0(?)
Classification: C2010120 Stairs - Precast (Uniformat)
Pset_QuantityTakeOff - sets with these values: 2
Pset_SlabCommon - PitchAngle: 0 rad
BaseQuantities - GrossArea: 1.26043 m2; NetArea: 120.397 m2; GrossVolume: 19763.6 m3; NetVolume: 19.7636 m3; Perimeter: 7517.63 mm; Width: 15680 mm
Constraints - Room Bounding: yes; Moves With Nearby Elements: no
Dimensions - Area: 1.26043 m2; Volume: 19.7636 m3
Other - Family: LOSA 1499: LOSA 1499; Family and Type: LOSA 1499: LOSA 1499; Type: LOSA 1499: LOSA 1499; Type Id: LOSA 1499: LOSA 1499
Phasing - Phase Created: New Construction

# IfcSlab: LOSA, LOSA 3033:LOSA 3033:203458
In: Default
Type - Description: 15680*665; PredefinedType: FLOOR; Material: CONCRETE/28MPa
Type - Identity Data - Assembly Code: C2010120; Assembly Description: Stairs - Precast; Type Name: LOSA 3033
Type - Other - Category: Floors; Family Name: LOSA 3033
Type - Pset_ProductRequirements - Name: LOSA; Category: Floors
Type - Pset_QuantityTakeOff - Reference: Hormigón_GR-1/0(?)
Type - Pset_ReinforcementBarPitchOfSlab - Reference: Hormigón_GR-1/0(?)
Type - Pset_SlabCommon - IsExternal: no; LoadBearing: yes; Reference: Hormigón_GR-1/0(?)
Classification: C2010120 Stairs - Precast (Uniformat)
Pset_QuantityTakeOff - sets with these values: 2
Pset_SlabCommon - PitchAngle: 0 rad
BaseQuantities - GrossArea: 1.26043 m2; NetArea: 120.397 m2; GrossVolume: 19763.6 m3; NetVolume: 19.7636 m3; Perimeter: 7517.63 mm; Width: 15680 mm
Constraints - Room Bounding: yes; Moves With Nearby Elements: no
Dimensions - Area: 1.26043 m2; Volume: 19.7636 m3
Other - Family: LOSA 3033: LOSA 3033; Family and Type: LOSA 3033: LOSA 3033; Type: LOSA 3033: LOSA 3033; Type Id: LOSA 3033: LOSA 3033
Phasing - Phase Created: New Construction

# IfcSlab: LOSA, LOSA 2692:LOSA 2692:203430
In: Default
Type - Description: 250*10000; PredefinedType: FLOOR; Material: CONCRETE/28MPa 1537
Type - Identity Data - Assembly Code: A1030200; Assembly Description: Structural Slab on Grade; Type Name: LOSA 2692
Type - Other - Category: Floors; Family Name: LOSA 2692
Type - Pset_ProductRequirements - Name: LOSA; Category: Floors
Type - Pset_QuantityTakeOff - Reference: Hormigón_GR-1/0(?)
Type - Pset_ReinforcementBarPitchOfSlab - Reference: Hormigón_GR-1/0(?)
Type - Pset_SlabCommon - IsExternal: no; LoadBearing: yes; Reference: Hormigón_GR-1/0(?)
Classification: A1030200 Structural Slab on Grade (Uniformat)
Pset_QuantityTakeOff - sets with these values: 2
Pset_SlabCommon - PitchAngle: 0 rad
BaseQuantities - GrossArea: 120 m2; NetArea: 251 m2; GrossVolume: 30000 m3; NetVolume: 30 m3; Perimeter: 44000 mm; Width: 250 mm
Constraints - Room Bounding: yes; Moves With Nearby Elements: no
Dimensions - Area: 120 m2; Volume: 30 m3
Other - Family: LOSA 2692: LOSA 2692; Family and Type: LOSA 2692: LOSA 2692; Type: LOSA 2692: LOSA 2692; Type Id: LOSA 2692: LOSA 2692
Phasing - Phase Created: New Construction

# IfcSlab: LOSA, LOSA 2655:LOSA 2655:203416
In: Default
Type - Description: 250*15000; PredefinedType: FLOOR; Material: CONCRETE/28MPa 1537
Type - Identity Data - Assembly Code: A1030200; Assembly Description: Structural Slab on Grade; Type Name: LOSA 2655
Type - Other - Category: Floors; Family Name: LOSA 2655
Type - Pset_ProductRequirements - Name: LOSA; Category: Floors
Type - Pset_QuantityTakeOff - Reference: Hormigón_GR-1/0(?)
Type - Pset_ReinforcementBarPitchOfSlab - Reference: Hormigón_GR-1/0(?)
Type - Pset_SlabCommon - IsExternal: no; LoadBearing: yes; Reference: Hormigón_GR-1/0(?)
Classification: A1030200 Structural Slab on Grade (Uniformat)
Pset_QuantityTakeOff - sets with these values: 2
Pset_SlabCommon - PitchAngle: 0 rad
BaseQuantities - GrossArea: 375 m2; NetArea: 770 m2; GrossVolume: 93750 m3; NetVolume: 93.75 m3; Perimeter: 80000 mm; Width: 250 mm
Constraints - Room Bounding: yes; Moves With Nearby Elements: no
Dimensions - Area: 375 m2; Volume: 93.75 m3
Other - Family: LOSA 2655: LOSA 2655; Family and Type: LOSA 2655: LOSA 2655; Type: LOSA 2655: LOSA 2655; Type Id: LOSA 2655: LOSA 2655
Phasing - Phase Created: New Construction

# IfcSlab: LOSA, LOSA 2725:LOSA 2725:203444
In: Default
Type - Description: 250*15000; PredefinedType: FLOOR; Material: CONCRETE/28MPa 1537
Type - Identity Data - Assembly Code: A1030200; Assembly Description: Structural Slab on Grade; Type Name: LOSA 2725
Type - Other - Category: Floors; Family Name: LOSA 2725
Type - Pset_ProductRequirements - Name: LOSA; Category: Floors
Type - Pset_QuantityTakeOff - Reference: Hormigón_GR-1/0(?)
Type - Pset_ReinforcementBarPitchOfSlab - Reference: Hormigón_GR-1/0(?)
Type - Pset_SlabCommon - IsExternal: no; LoadBearing: yes; Reference: Hormigón_GR-1/0(?)
Classification: A1030200 Structural Slab on Grade (Uniformat)
Pset_QuantityTakeOff - sets with these values: 2
Pset_SlabCommon - PitchAngle: 0 rad
BaseQuantities - GrossArea: 750 m2; NetArea: 1532.5 m2; GrossVolume: 187500 m3; NetVolume: 187.5 m3; Perimeter: 130000 mm; Width: 250 mm
Constraints - Room Bounding: yes; Moves With Nearby Elements: no
Dimensions - Area: 750 m2; Volume: 187.5 m3
Other - Family: LOSA 2725: LOSA 2725; Family and Type: LOSA 2725: LOSA 2725; Type: LOSA 2725: LOSA 2725; Type Id: LOSA 2725: LOSA 2725
Phasing - Phase Created: New Construction

# IfcSlab: LOSA, LOSA 2374:LOSA 2374:203206
In: Default
Type - Description: 600*3586; PredefinedType: FLOOR; Material: Concrete, Cast-in-Place gray
Type - Identity Data - Assembly Code: B1010320; Assembly Description: Beams - Precast; Type Name: LOSA 2374
Type - Other - Category: Floors; Family Name: LOSA 2374
Type - Pset_ProductRequirements - Name: LOSA; Category: Floors
Type - Pset_QuantityTakeOff - Reference: P/0(?)
Type - Pset_ReinforcementBarPitchOfSlab - Reference: P/0(?)
Type - Pset_SlabCommon - IsExternal: no; LoadBearing: yes; Reference: P/0(?)
Classification: B1010320 Beams - Precast (Uniformat)
Pset_QuantityTakeOff - sets with these values: 2
Pset_SlabCommon - PitchAngle: 0 rad
BaseQuantities - NetArea: 90.3415 m2; NetVolume: 21.1823 m3; Width: 600 mm
Constraints - Room Bounding: yes; Level: Level: Undefined; Moves With Nearby Elements: no
Dimensions - Area: 36.3207 m2; Volume: 21.1823 m3
Other - Family: LOSA 2374: LOSA 2374; Family and Type: LOSA 2374: LOSA 2374; Type: LOSA 2374: LOSA 2374; Type Id: LOSA 2374: LOSA 2374
Phasing - Phase Created: New Construction

# IfcSlab: LOSA, LOSA 5600:LOSA 5600:203915
In: Default
Type - Description: 600*3586; PredefinedType: FLOOR; Material: Concrete, Cast-in-Place gray
Type - Identity Data - Assembly Code: B1010320; Assembly Description: Beams - Precast; Type Name: LOSA 5600
Type - Other - Category: Floors; Family Name: LOSA 5600
Type - Pset_ProductRequirements - Name: LOSA; Category: Floors
Type - Pset_QuantityTakeOff - Reference: P/0(?)
Type - Pset_ReinforcementBarPitchOfSlab - Reference: P/0(?)
Type - Pset_SlabCommon - IsExternal: no; LoadBearing: yes; Reference: P/0(?)
Classification: B1010320 Beams - Precast (Uniformat)
Pset_QuantityTakeOff - sets with these values: 2
Pset_SlabCommon - PitchAngle: 0 rad
BaseQuantities - NetArea: 90.3415 m2; NetVolume: 21.1823 m3; Width: 600 mm
Constraints - Room Bounding: yes; Level: Level: Undefined; Moves With Nearby Elements: no
Dimensions - Area: 36.3207 m2; Volume: 21.1823 m3
Other - Family: LOSA 5600: LOSA 5600; Family and Type: LOSA 5600: LOSA 5600; Type: LOSA 5600: LOSA 5600; Type Id: LOSA 5600: LOSA 5600
Phasing - Phase Created: New Construction

# IfcSlab: LOSA, LOSA 2332:LOSA 2332:203173
In: Default
Type - Description: 600*3740; PredefinedType: FLOOR; Material: Concrete, Cast-in-Place gray
Type - Identity Data - Assembly Code: B1010320; Assembly Description: Beams - Precast; Type Name: LOSA 2332
Type - Other - Category: Floors; Family Name: LOSA 2332
Type - Pset_ProductRequirements - Name: LOSA; Category: Floors
Type - Pset_QuantityTakeOff - Reference: P/0(?)
Type - Pset_ReinforcementBarPitchOfSlab - Reference: P/0(?)
Type - Pset_SlabCommon - IsExternal: no; LoadBearing: yes; Reference: P/0(?)
Classification: B1010320 Beams - Precast (Uniformat)
Pset_QuantityTakeOff - sets with these values: 2
Pset_SlabCommon - PitchAngle: 0 rad
BaseQuantities - NetArea: 101.839 m2; NetVolume: 24.0009 m3; Width: 600 mm
Constraints - Room Bounding: yes; Moves With Nearby Elements: no; Level: Level: Undefined
Dimensions - Area: 41.0251 m2; Volume: 24.0009 m3
Other - Family: LOSA 2332: LOSA 2332; Family and Type: LOSA 2332: LOSA 2332; Type: LOSA 2332: LOSA 2332; Type Id: LOSA 2332: LOSA 2332
Phasing - Phase Created: New Construction

# IfcSlab: LOSA, LOSA 5577:LOSA 5577:203882
In: Default
Type - Description: 600*3740; PredefinedType: FLOOR; Material: Concrete, Cast-in-Place gray
Type - Identity Data - Assembly Code: B1010320; Assembly Description: Beams - Precast; Type Name: LOSA 5577
Type - Other - Category: Floors; Family Name: LOSA 5577
Type - Pset_ProductRequirements - Name: LOSA; Category: Floors
Type - Pset_QuantityTakeOff - Reference: P/0(?)
Type - Pset_ReinforcementBarPitchOfSlab - Reference: P/0(?)
Type - Pset_SlabCommon - IsExternal: no; LoadBearing: yes; Reference: P/0(?)
Classification: B1010320 Beams - Precast (Uniformat)
Pset_QuantityTakeOff - sets with these values: 2
Pset_SlabCommon - PitchAngle: 0 rad
BaseQuantities - NetArea: 101.839 m2; NetVolume: 24.0009 m3; Width: 600 mm
Constraints - Room Bounding: yes; Moves With Nearby Elements: no; Level: Level: Undefined
Dimensions - Area: 41.0251 m2; Volume: 24.0009 m3
Other - Family: LOSA 5577: LOSA 5577; Family and Type: LOSA 5577: LOSA 5577; Type: LOSA 5577: LOSA 5577; Type Id: LOSA 5577: LOSA 5577
Phasing - Phase Created: New Construction

# IfcSlab: LOSA, LOSA 2247:LOSA 2247:203107
In: Default
Type - Description: 600*4036; PredefinedType: FLOOR; Material: Concrete, Cast-in-Place gray
Type - Identity Data - Assembly Code: B1010320; Assembly Description: Beams - Precast; Type Name: LOSA 2247
Type - Other - Category: Floors; Family Name: LOSA 2247
Type - Pset_ProductRequirements - Name: LOSA; Category: Floors
Type - Pset_QuantityTakeOff - Reference: P/0(?)
Type - Pset_ReinforcementBarPitchOfSlab - Reference: P/0(?)
Type - Pset_SlabCommon - IsExternal: no; LoadBearing: yes; Reference: P/0(?)
Classification: B1010320 Beams - Precast (Uniformat)
Pset_QuantityTakeOff - sets with these values: 2
Pset_SlabCommon - PitchAngle: 0 rad
BaseQuantities - NetArea: 122.069 m2; NetVolume: 28.7086 m3; Width: 600 mm
Constraints - Room Bounding: yes; Moves With Nearby Elements: no; Level: Level: Undefined
Dimensions - Area: 48.8797 m2; Volume: 28.7086 m3
Other - Family: LOSA 2247: LOSA 2247; Family and Type: LOSA 2247: LOSA 2247; Type: LOSA 2247: LOSA 2247; Type Id: LOSA 2247: LOSA 2247
Phasing - Phase Created: New Construction

# IfcSlab: LOSA, LOSA 5533:LOSA 5533:203816
In: Default
Type - Description: 600*4036; PredefinedType: FLOOR; Material: Concrete, Cast-in-Place gray
Type - Identity Data - Assembly Code: B1010320; Assembly Description: Beams - Precast; Type Name: LOSA 5533
Type - Other - Category: Floors; Family Name: LOSA 5533
Type - Pset_ProductRequirements - Name: LOSA; Category: Floors
Type - Pset_QuantityTakeOff - Reference: P/0(?)
Type - Pset_ReinforcementBarPitchOfSlab - Reference: P/0(?)
Type - Pset_SlabCommon - IsExternal: no; LoadBearing: yes; Reference: P/0(?)
Classification: B1010320 Beams - Precast (Uniformat)
Pset_QuantityTakeOff - sets with these values: 2
Pset_SlabCommon - PitchAngle: 0 rad
BaseQuantities - NetArea: 122.069 m2; NetVolume: 28.7086 m3; Width: 600 mm
Constraints - Room Bounding: yes; Level: Level: Undefined; Moves With Nearby Elements: no
Dimensions - Area: 48.8797 m2; Volume: 28.7086 m3
Other - Family: LOSA 5533: LOSA 5533; Family and Type: LOSA 5533: LOSA 5533; Type: LOSA 5533: LOSA 5533; Type Id: LOSA 5533: LOSA 5533
Phasing - Phase Created: New Construction

# IfcSlab: LOSA, LOSA 2290:LOSA 2290:203140
In: Default
Type - Description: 600*4075; PredefinedType: FLOOR; Material: Concrete, Cast-in-Place gray
Type - Identity Data - Assembly Code: B1010320; Assembly Description: Beams - Precast; Type Name: LOSA 2290
Type - Other - Category: Floors; Family Name: LOSA 2290
Type - Pset_ProductRequirements - Name: LOSA; Category: Floors
Type - Pset_QuantityTakeOff - Reference: P/0(?)
Type - Pset_ReinforcementBarPitchOfSlab - Reference: P/0(?)
Type - Pset_SlabCommon - IsExternal: no; LoadBearing: yes; Reference: P/0(?)
Classification: B1010320 Beams - Precast (Uniformat)
Pset_QuantityTakeOff - sets with these values: 2
Pset_SlabCommon - PitchAngle: 0 rad
BaseQuantities - NetArea: 107.254 m2; NetVolume: 24.8361 m3; Width: 600 mm
Constraints - Room Bounding: yes; Level: Level: Undefined; Moves With Nearby Elements: no
Dimensions - Area: 42.4221 m2; Volume: 24.8361 m3
Other - Family: LOSA 2290: LOSA 2290; Family and Type: LOSA 2290: LOSA 2290; Type: LOSA 2290: LOSA 2290; Type Id: LOSA 2290: LOSA 2290
Phasing - Phase Created: New Construction

# IfcSlab: LOSA, LOSA 5554:LOSA 5554:203849
In: Default
Type - Description: 600*4075; PredefinedType: FLOOR; Material: Concrete, Cast-in-Place gray
Type - Identity Data - Assembly Code: B1010320; Assembly Description: Beams - Precast; Type Name: LOSA 5554
Type - Other - Category: Floors; Family Name: LOSA 5554
Type - Pset_ProductRequirements - Name: LOSA; Category: Floors
Type - Pset_QuantityTakeOff - Reference: P/0(?)
Type - Pset_ReinforcementBarPitchOfSlab - Reference: P/0(?)
Type - Pset_SlabCommon - IsExternal: no; LoadBearing: yes; Reference: P/0(?)
Classification: B1010320 Beams - Precast (Uniformat)
Pset_QuantityTakeOff - sets with these values: 2
Pset_SlabCommon - PitchAngle: 0 rad
BaseQuantities - NetArea: 107.254 m2; NetVolume: 24.8361 m3; Width: 600 mm
Constraints - Room Bounding: yes; Moves With Nearby Elements: no; Level: Level: Undefined
Dimensions - Area: 42.4221 m2; Volume: 24.8361 m3
Other - Family: LOSA 5554: LOSA 5554; Family and Type: LOSA 5554: LOSA 5554; Type: LOSA 5554: LOSA 5554; Type Id: LOSA 5554: LOSA 5554
Phasing - Phase Created: New Construction

# IfcSlab: LOSA, LOSA 1805:LOSA 1805:202854
In: Default
Type - Description: 600*4338; PredefinedType: FLOOR; Material: Concrete, Cast-in-Place gray
Type - Identity Data - Assembly Code: B1010320; Assembly Description: Beams - Precast; Type Name: LOSA 1805
Type - Other - Category: Floors; Family Name: LOSA 1805
Type - Pset_ProductRequirements - Name: LOSA; Category: Floors
Type - Pset_QuantityTakeOff - Reference: Hormigón_LC-1/0(?)
Type - Pset_ReinforcementBarPitchOfSlab - Reference: Hormigón_LC-1/0(?)
Type - Pset_SlabCommon - IsExternal: no; LoadBearing: yes; Reference: Hormigón_LC-1/0(?)
Classification: B1010320 Beams - Precast (Uniformat)
Pset_QuantityTakeOff - sets with these values: 2
Pset_SlabCommon - PitchAngle: 0 rad
BaseQuantities - NetArea: 167.525 m2; NetVolume: 41.1432 m3; Width: 600 mm
Constraints - Room Bounding: yes; Moves With Nearby Elements: no; Level: Level: Undefined
Dimensions - Area: 69.608 m2; Volume: 41.1432 m3
Other - Family: LOSA 1805: LOSA 1805; Family and Type: LOSA 1805: LOSA 1805; Type: LOSA 1805: LOSA 1805; Type Id: LOSA 1805: LOSA 1805
Phasing - Phase Created: New Construction

# IfcSlab: LOSA, LOSA 5052:LOSA 5052:203491
In: Default
Type - Description: 600*4338; PredefinedType: FLOOR; Material: Concrete, Cast-in-Place gray
Type - Identity Data - Assembly Code: B1010320; Assembly Description: Beams - Precast; Type Name: LOSA 5052
Type - Other - Category: Floors; Family Name: LOSA 5052
Type - Pset_ProductRequirements - Name: LOSA; Category: Floors
Type - Pset_QuantityTakeOff - Reference: Hormigón_LC-1/0(?)
Type - Pset_ReinforcementBarPitchOfSlab - Reference: Hormigón_LC-1/0(?)
Type - Pset_SlabCommon - IsExternal: no; LoadBearing: yes; Reference: Hormigón_LC-1/0(?)
Classification: B1010320 Beams - Precast (Uniformat)
Pset_QuantityTakeOff - sets with these values: 2
Pset_SlabCommon - PitchAngle: 0 rad
BaseQuantities - NetArea: 167.525 m2; NetVolume: 41.1432 m3; Width: 600 mm
Constraints - Room Bounding: yes; Moves With Nearby Elements: no; Level: Level: Undefined
Dimensions - Area: 69.608 m2; Volume: 41.1432 m3
Other - Family: LOSA 5052: LOSA 5052; Family and Type: LOSA 5052: LOSA 5052; Type: LOSA 5052: LOSA 5052; Type Id: LOSA 5052: LOSA 5052
Phasing - Phase Created: New Construction

# IfcSlab: LOSA, LOSA 2460:LOSA 2460:203272
In: Default
Type - Description: 600*4557; PredefinedType: FLOOR; Material: Concrete, Cast-in-Place gray
Type - Identity Data - Assembly Code: B1010320; Assembly Description: Beams - Precast; Type Name: LOSA 2460
Type - Other - Category: Floors; Family Name: LOSA 2460
Type - Pset_ProductRequirements - Name: LOSA; Category: Floors
Type - Pset_QuantityTakeOff - Reference: P/0(?)
Type - Pset_ReinforcementBarPitchOfSlab - Reference: P/0(?)
Type - Pset_SlabCommon - IsExternal: no; LoadBearing: yes; Reference: P/0(?)
Classification: B1010320 Beams - Precast (Uniformat)
Pset_QuantityTakeOff - sets with these values: 2
Pset_SlabCommon - PitchAngle: 0 rad
BaseQuantities - NetArea: 132.662 m2; NetVolume: 31.0965 m3; Width: 600 mm
Constraints - Room Bounding: yes; Level: Level: Undefined; Moves With Nearby Elements: no
Dimensions - Area: 52.862 m2; Volume: 31.0965 m3
Other - Family: LOSA 2460: LOSA 2460; Family and Type: LOSA 2460: LOSA 2460; Type: LOSA 2460: LOSA 2460; Type Id: LOSA 2460: LOSA 2460
Phasing - Phase Created: New Construction

# IfcSlab: LOSA, LOSA 5648:LOSA 5648:203981
In: Default
Type - Description: 600*4557; PredefinedType: FLOOR; Material: Concrete, Cast-in-Place gray
Type - Identity Data - Assembly Code: B1010320; Assembly Description: Beams - Precast; Type Name: LOSA 5648
Type - Other - Category: Floors; Family Name: LOSA 5648
Type - Pset_ProductRequirements - Name: LOSA; Category: Floors
Type - Pset_QuantityTakeOff - Reference: P/0(?)
Type - Pset_ReinforcementBarPitchOfSlab - Reference: P/0(?)
Type - Pset_SlabCommon - IsExternal: no; LoadBearing: yes; Reference: P/0(?)
Classification: B1010320 Beams - Precast (Uniformat)
Pset_QuantityTakeOff - sets with these values: 2
Pset_SlabCommon - PitchAngle: 0 rad
BaseQuantities - NetArea: 132.662 m2; NetVolume: 31.0965 m3; Width: 600 mm
Constraints - Room Bounding: yes; Moves With Nearby Elements: no; Level: Level: Undefined
Dimensions - Area: 52.862 m2; Volume: 31.0965 m3
Other - Family: LOSA 5648: LOSA 5648; Family and Type: LOSA 5648: LOSA 5648; Type: LOSA 5648: LOSA 5648; Type Id: LOSA 5648: LOSA 5648
Phasing - Phase Created: New Construction

# IfcSlab: LOSA, LOSA 2419:LOSA 2419:203239
In: Default
Type - Description: 600*4671; PredefinedType: FLOOR; Material: Concrete, Cast-in-Place gray
Type - Identity Data - Assembly Code: B1010320; Assembly Description: Beams - Precast; Type Name: LOSA 2419
Type - Other - Category: Floors; Family Name: LOSA 2419
Type - Pset_ProductRequirements - Name: LOSA; Category: Floors
Type - Pset_QuantityTakeOff - Reference: P/0(?)
Type - Pset_ReinforcementBarPitchOfSlab - Reference: P/0(?)
Type - Pset_SlabCommon - IsExternal: no; LoadBearing: yes; Reference: P/0(?)
Classification: B1010320 Beams - Precast (Uniformat)
Pset_QuantityTakeOff - sets with these values: 2
Pset_SlabCommon - PitchAngle: 0 rad
BaseQuantities - NetArea: 175.784 m2; NetVolume: 42.8537 m3; Width: 600 mm
Constraints - Room Bounding: yes; Level: Level: Undefined; Moves With Nearby Elements: no
Dimensions - Area: 72.4813 m2; Volume: 42.8537 m3
Other - Family: LOSA 2419: LOSA 2419; Family and Type: LOSA 2419: LOSA 2419; Type: LOSA 2419: LOSA 2419; Type Id: LOSA 2419: LOSA 2419
Phasing - Phase Created: New Construction

# IfcSlab: LOSA, LOSA 5625:LOSA 5625:203948
In: Default
Type - Description: 600*4671; PredefinedType: FLOOR; Material: Concrete, Cast-in-Place gray
Type - Identity Data - Assembly Code: B1010320; Assembly Description: Beams - Precast; Type Name: LOSA 5625
Type - Other - Category: Floors; Family Name: LOSA 5625
Type - Pset_ProductRequirements - Name: LOSA; Category: Floors
Type - Pset_QuantityTakeOff - Reference: P/0(?)
Type - Pset_ReinforcementBarPitchOfSlab - Reference: P/0(?)
Type - Pset_SlabCommon - IsExternal: no; LoadBearing: yes; Reference: P/0(?)
Classification: B1010320 Beams - Precast (Uniformat)
Pset_QuantityTakeOff - sets with these values: 2
Pset_SlabCommon - PitchAngle: 0 rad
BaseQuantities - NetArea: 175.784 m2; NetVolume: 42.8537 m3; Width: 600 mm
Constraints - Room Bounding: yes; Level: Level: Undefined; Moves With Nearby Elements: no
Dimensions - Area: 72.4813 m2; Volume: 42.8537 m3
Other - Family: LOSA 5625: LOSA 5625; Family and Type: LOSA 5625: LOSA 5625; Type: LOSA 5625: LOSA 5625; Type Id: LOSA 5625: LOSA 5625
Phasing - Phase Created: New Construction

# IfcSlab: LOSA, LOSA 1398:LOSA 1398:202788
In: Default
Type - Description: 600*5253; PredefinedType: FLOOR; Material: Concrete, Cast-in-Place gray
Type - Identity Data - Assembly Code: B1010320; Assembly Description: Beams - Precast; Type Name: LOSA 1398
Type - Other - Category: Floors; Family Name: LOSA 1398
Type - Pset_ProductRequirements - Name: LOSA; Category: Floors
Type - Pset_QuantityTakeOff - Reference: P/0(?)
Type - Pset_ReinforcementBarPitchOfSlab - Reference: P/0(?)
Type - Pset_SlabCommon - IsExternal: no; LoadBearing: yes; Reference: P/0(?)
Classification: B1010320 Beams - Precast (Uniformat)
Pset_QuantityTakeOff - sets with these values: 2
Pset_SlabCommon - PitchAngle: 0 rad
BaseQuantities - GrossArea: 75.5668 m2; NetArea: 187.099 m2; GrossVolume: 45340.1 m3; NetVolume: 45.3401 m3; Perimeter: 59941.8 mm; Width: 600 mm
Constraints - Room Bounding: yes; Level: Level: Undefined; Moves With Nearby Elements: no
Dimensions - Area: 75.5668 m2; Volume: 45.3401 m3
Other - Family: LOSA 1398: LOSA 1398; Family and Type: LOSA 1398: LOSA 1398; Type: LOSA 1398: LOSA 1398; Type Id: LOSA 1398: LOSA 1398
Phasing - Phase Created: New Construction

# IfcSlab: LOSA, LOSA 5886:LOSA 5886:204103
In: Default
Type - Description: 600*5253; PredefinedType: FLOOR; Material: Concrete, Cast-in-Place gray
Type - Identity Data - Assembly Code: B1010320; Assembly Description: Beams - Precast; Type Name: LOSA 5886
Type - Other - Category: Floors; Family Name: LOSA 5886
Type - Pset_ProductRequirements - Name: LOSA; Category: Floors
Type - Pset_QuantityTakeOff - Reference: P/0(?)
Type - Pset_ReinforcementBarPitchOfSlab - Reference: P/0(?)
Type - Pset_SlabCommon - IsExternal: no; LoadBearing: yes; Reference: P/0(?)
Classification: B1010320 Beams - Precast (Uniformat)
Pset_QuantityTakeOff - sets with these values: 2
Pset_SlabCommon - PitchAngle: 0 rad
BaseQuantities - GrossArea: 75.5668 m2; NetArea: 187.099 m2; GrossVolume: 45340.1 m3; NetVolume: 45.3401 m3; Perimeter: 59941.8 mm; Width: 600 mm
Constraints - Room Bounding: yes; Level: Level: Undefined; Moves With Nearby Elements: no
Dimensions - Area: 75.5668 m2; Volume: 45.3401 m3
Other - Family: LOSA 5886: LOSA 5886; Family and Type: LOSA 5886: LOSA 5886; Type: LOSA 5886: LOSA 5886; Type Id: LOSA 5886: LOSA 5886
Phasing - Phase Created: New Construction

# IfcWallStandardCase: Basic Wall:10500*300 (4)
In: Default
Type - PredefinedType: STANDARD; Material: CONCRETE/28MPa 300 mm
Type - Analytical Properties - Absorptance: 0.1; Roughness: 1
Type - Construction - Function: Exterior; Width: 300 mm; Wrapping at Inserts: Do not wrap
Type - Graphics - Coarse Scale Fill Color: 0
Type - Identity Data - Assembly Code: A1010210; Assembly Description: Foundation Walls - CIP; Type Name: 10500*300
Type - Other - Category: Walls; Family Name: Basic Wall
Type - Pset_ElementShading - Roughness: 304.8 mm
Type - Pset_ProductRequirements - Category: Walls
Type - Pset_QuantityTakeOff - Reference: 10500*300
Type - Pset_ReinforcementBarPitchOfWall - Reference: 10500*300
Type - Pset_WallCommon - IsExternal: no; Reference: 10500*300
Description: 10500*300; Classification: A1010210 Foundation Walls - CIP (Uniformat)
BaseQuantities - Height: 10500 mm; Width: 300 mm
Constraints - Room Bounding: yes; Base Constraint: Level: Default; Base Extension Distance: 0 mm; Base is Attached: no; Base Offset: -10400 mm; Location Line: Wall Centerline; Related to Mass: no; Top Extension Distance: 0 mm; Top is Attached: no; Top Offset: 0 mm; Unconnected Height: 10500 mm
Other - Family: Basic Wall: 10500*300; Family and Type: Basic Wall: 10500*300; Type: Basic Wall: 10500*300; Type Id: Basic Wall: 10500*300
Phasing - Phase Created: New Construction
Structural - Enable Analytical Model: yes; Rebar Cover - Exterior Face: Rebar Cover Settings: Rebar Cover 1; Rebar Cover - Interior Face: Rebar Cover Settings: Rebar Cover 1; Rebar Cover - Other Faces: Rebar Cover Settings: Rebar Cover 1; Structural: yes; Structural Usage: Bearing
Pset_ProductRequirements - Name: PANTALLA
Pset_QuantityTakeOff - Reference: Hormigón_MP-1/0(?); sets with these values: 2
Pset_WallCommon - LoadBearing: yes; Reference: Hormigón_MP-1/0(?); IsExternal: yes; ExtendToStructure: no
Name | BaseQuantities, Length (mm) | GrossFootprintArea (m2) | NetVolume (m3) | NetSideArea (m2) | Area (m2) | Dimensions, Length (mm) | Volume (m3)
PANTALLA | 93225 | 27.9675 | 293658740393 | 978862468 | 978.862 | 93416.2 | 293.482
PANTALLA | 65420.5 | 19.6177 | 206074533079 | 686915110 | 686.915 | 65545 | 205.986
PANTALLA | 65420.5 | 19.6177 | 206074533124 | 686915110 | 686.915 | 65545 | 205.986
PANTALLA | 68558.6 | 20.5507 | 215959552795 | 719865176 | 719.865 | 68807.6 | 215.782

# IfcWallStandardCase: Basic Wall:1700*250 (4)
In: Default
Type - PredefinedType: STANDARD; Material: CONCRETE/28MPa 250 mm
Type - Analytical Properties - Roughness: 1; Absorptance: 0.1
Type - Construction - Function: Exterior; Wrapping at Inserts: Do not wrap; Width: 250 mm
Type - Graphics - Coarse Scale Fill Color: 0
Type - Identity Data - Assembly Code: A1010210; Assembly Description: Foundation Walls - CIP; Type Name: 1700*250
Type - Other - Category: Walls; Family Name: Basic Wall
Type - Pset_ElementShading - Roughness: 304.8 mm
Type - Pset_ProductRequirements - Category: Walls
Type - Pset_QuantityTakeOff - Reference: 1700*250
Type - Pset_ReinforcementBarPitchOfWall - Reference: 1700*250
Type - Pset_WallCommon - IsExternal: no; Reference: 1700*250
Description: 1700*250; Classification: A1010210 Foundation Walls - CIP (Uniformat)
BaseQuantities - Height: 1700 mm; Width: 250 mm
Constraints - Room Bounding: yes; Base Constraint: Level: Default; Base Extension Distance: 0 mm; Base is Attached: no; Location Line: Wall Centerline; Related to Mass: no; Top Extension Distance: 0 mm; Top is Attached: no; Top Offset: 0 mm; Base Offset: -4650 mm; Unconnected Height: 1700 mm
Other - Family: Basic Wall: 1700*250; Family and Type: Basic Wall: 1700*250; Type: Basic Wall: 1700*250; Type Id: Basic Wall: 1700*250
Phasing - Phase Created: New Construction
Structural - Enable Analytical Model: yes; Rebar Cover - Exterior Face: Rebar Cover Settings: Rebar Cover 1; Rebar Cover - Interior Face: Rebar Cover Settings: Rebar Cover 1; Rebar Cover - Other Faces: Rebar Cover Settings: Rebar Cover 1; Structural: yes; Structural Usage: Bearing
Pset_ProductRequirements - Name: PANEL
Pset_QuantityTakeOff - Reference: Hormigón_P-1/0(?); sets with these values: 2
Pset_WallCommon - LoadBearing: yes; IsExternal: yes; ExtendToStructure: no; Reference: Hormigón_P-1/0(?)
Name | BaseQuantities, Length (mm) | GrossFootprintArea (m2) | NetVolume (m3) | NetSideArea (m2) | Area (m2) | Dimensions, Length (mm) | Volume (m3)
2 x PANEL | 12500 | 3.125 | 5312500000 | 21250000 | 21.25 | 12500 | 5.3125
2 x PANEL | 9750 | 2.4375 | 4143750000 | 16575000 | 16.575 | 10000 | 4.14375

# IfcWallStandardCase: Basic Wall:2400*250 (8)
In: Default
Type - PredefinedType: STANDARD; Material: CONCRETE/28MPa 250 mm
Type - Analytical Properties - Roughness: 1; Absorptance: 0.1
Type - Construction - Function: Exterior; Wrapping at Inserts: Do not wrap; Width: 250 mm
Type - Graphics - Coarse Scale Fill Color: 0
Type - Identity Data - Assembly Code: A1010210; Assembly Description: Foundation Walls - CIP; Type Name: 2400*250
Type - Other - Category: Walls; Family Name: Basic Wall
Type - Pset_ElementShading - Roughness: 304.8 mm
Type - Pset_ProductRequirements - Category: Walls
Type - Pset_QuantityTakeOff - Reference: 2400*250
Type - Pset_ReinforcementBarPitchOfWall - Reference: 2400*250
Type - Pset_WallCommon - IsExternal: no; Reference: 2400*250
Description: 2400*250; Classification: A1010210 Foundation Walls - CIP (Uniformat)
BaseQuantities - Height: 2400 mm; Width: 250 mm
Constraints - Room Bounding: yes; Base Constraint: Level: Default; Base Extension Distance: 0 mm; Base is Attached: no; Location Line: Wall Centerline; Related to Mass: no; Top Extension Distance: 0 mm; Top is Attached: no; Top Offset: 0 mm; Base Offset: -5400 mm; Unconnected Height: 2400 mm
Other - Family: Basic Wall: 2400*250; Family and Type: Basic Wall: 2400*250; Type: Basic Wall: 2400*250; Type Id: Basic Wall: 2400*250
Phasing - Phase Created: New Construction
Structural - Enable Analytical Model: yes; Rebar Cover - Exterior Face: Rebar Cover Settings: Rebar Cover 1; Rebar Cover - Interior Face: Rebar Cover Settings: Rebar Cover 1; Rebar Cover - Other Faces: Rebar Cover Settings: Rebar Cover 1; Structural: yes; Structural Usage: Bearing
Pset_ProductRequirements - Name: PANEL
Pset_QuantityTakeOff - Reference: Hormigón_P-1/0(?); sets with these values: 2
Pset_WallCommon - LoadBearing: yes; IsExternal: yes; ExtendToStructure: no; Reference: Hormigón_P-1/0(?)
Name | BaseQuantities, Length (mm) | GrossFootprintArea (m2) | NetVolume (m3) | NetSideArea (m2) | Area (m2) | Dimensions, Length (mm) | Volume (m3)
PANEL | 50500 | 12.625 | 30299995422 | 121199982 | 121.2 | 50500 | 30.3
PANEL | 50500 | 12.625 | 30300000000 | 121200000 | 121.2 | 50500 | 30.3
4 x PANEL | 14750 | 3.6875 | 8850000000 | 35400000 | 35.4 | 15000 | 8.85
2 x PANEL | 25500 | 6.375 | 15300000000 | 61200000 | 61.2 | 25500 | 15.3
